VERSION 5.7 ;
  NOWIREEXTENSIONATPIN ON ;
  DIVIDERCHAR "/" ;
  BUSBITCHARS "[]" ;
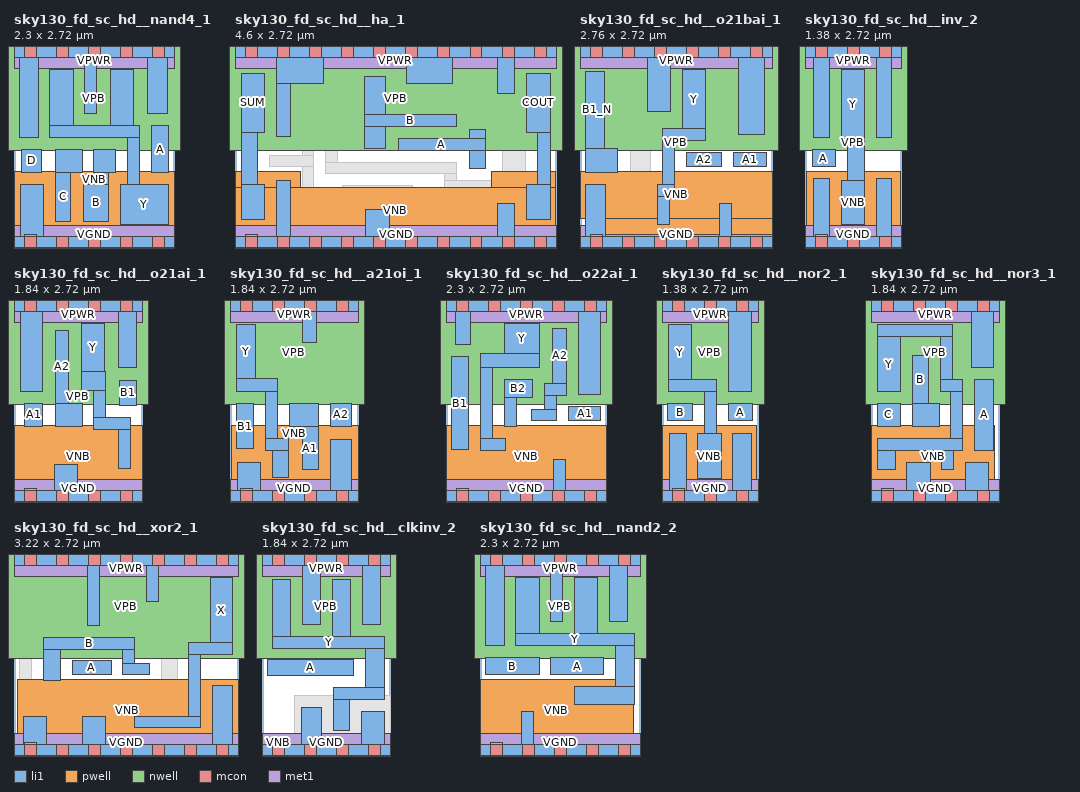
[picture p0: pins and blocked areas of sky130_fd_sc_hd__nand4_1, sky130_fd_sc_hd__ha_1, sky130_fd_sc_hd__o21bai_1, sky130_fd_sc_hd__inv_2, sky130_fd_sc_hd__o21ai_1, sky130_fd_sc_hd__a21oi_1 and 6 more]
MACRO sky130_fd_sc_hd__nand4_1
  CLASS BLOCK ;
  FOREIGN sky130_fd_sc_hd__nand4_1 ;
  ORIGIN 0.000 0.000 ;
  SIZE 2.300 BY 2.720 ;
  PIN C
    ANTENNAGATEAREA 0.247500 ;
    PORT
      LAYER li1 ;
        RECT 0.595 0.995 0.975 1.325 ;
        RECT 0.595 0.300 0.810 0.995 ;
    END
  END C
  PIN B
    ANTENNAGATEAREA 0.247500 ;
    PORT
      LAYER li1 ;
        RECT 1.145 0.995 1.455 1.325 ;
        RECT 1.145 0.825 1.350 0.995 ;
        RECT 1.000 0.300 1.350 0.825 ;
    END
  END B
  PIN Y
    ANTENNADIFFAREA 0.795000 ;
    PORT
      LAYER li1 ;
        RECT 0.515 1.665 0.845 2.465 ;
        RECT 1.385 1.665 1.715 2.465 ;
        RECT 0.515 1.495 1.795 1.665 ;
        RECT 1.625 0.825 1.795 1.495 ;
        RECT 1.520 0.255 2.215 0.825 ;
    END
  END Y
  PIN D
    ANTENNAGATEAREA 0.247500 ;
    PORT
      LAYER li1 ;
        RECT 0.110 0.995 0.395 1.325 ;
    END
  END D
  PIN A
    ANTENNAGATEAREA 0.247500 ;
    PORT
      LAYER li1 ;
        RECT 1.975 0.995 2.215 1.665 ;
    END
  END A
  PIN VNB
    PORT
      LAYER pwell ;
        RECT 0.005 0.105 2.295 1.015 ;
        RECT 0.150 -0.085 0.320 0.105 ;
    END
  END VNB
  PIN VPB
    PORT
      LAYER nwell ;
        RECT -0.190 1.305 2.490 2.910 ;
    END
  END VPB
  PIN VPWR
    USE POWER ;
    PORT
      LAYER li1 ;
        RECT 0.000 2.635 2.300 2.805 ;
        RECT 0.085 1.495 0.345 2.635 ;
        RECT 1.015 1.835 1.185 2.635 ;
        RECT 1.915 1.835 2.195 2.635 ;
      LAYER mcon ;
        RECT 0.145 2.635 0.315 2.805 ;
        RECT 0.605 2.635 0.775 2.805 ;
        RECT 1.065 2.635 1.235 2.805 ;
        RECT 1.525 2.635 1.695 2.805 ;
        RECT 1.985 2.635 2.155 2.805 ;
      LAYER met1 ;
        RECT 0.000 2.480 2.300 2.960 ;
    END
  END VPWR
  PIN VGND
    USE GROUND ;
    PORT
      LAYER li1 ;
        RECT 0.090 0.085 0.425 0.825 ;
        RECT 0.000 -0.085 2.300 0.085 ;
      LAYER mcon ;
        RECT 0.145 -0.085 0.315 0.085 ;
        RECT 0.605 -0.085 0.775 0.085 ;
        RECT 1.065 -0.085 1.235 0.085 ;
        RECT 1.525 -0.085 1.695 0.085 ;
        RECT 1.985 -0.085 2.155 0.085 ;
      LAYER met1 ;
        RECT 0.000 -0.240 2.300 0.240 ;
    END
  END VGND
END sky130_fd_sc_hd__nand4_1
MACRO sky130_fd_sc_hd__ha_1
  CLASS BLOCK ;
  FOREIGN sky130_fd_sc_hd__ha_1 ;
  ORIGIN 0.000 0.000 ;
  SIZE 4.600 BY 2.720 ;
  PIN B
    ANTENNAGATEAREA 0.252000 ;
    PORT
      LAYER li1 ;
        RECT 1.850 1.825 2.155 2.375 ;
        RECT 1.850 1.655 3.165 1.825 ;
        RECT 1.850 1.345 2.155 1.655 ;
    END
  END B
  PIN A
    ANTENNAGATEAREA 0.252000 ;
    PORT
      LAYER li1 ;
        RECT 3.360 1.485 3.585 1.615 ;
        RECT 2.335 1.315 3.585 1.485 ;
        RECT 3.360 1.055 3.585 1.315 ;
    END
  END A
  PIN COUT
    ANTENNADIFFAREA 0.429000 ;
    PORT
      LAYER li1 ;
        RECT 4.175 1.565 4.515 2.415 ;
        RECT 4.330 0.825 4.515 1.565 ;
        RECT 4.175 0.315 4.515 0.825 ;
    END
  END COUT
  PIN SUM
    ANTENNADIFFAREA 0.429000 ;
    PORT
      LAYER li1 ;
        RECT 0.090 1.565 0.425 2.415 ;
        RECT 0.090 0.825 0.320 1.565 ;
        RECT 0.090 0.315 0.425 0.825 ;
    END
  END SUM
  PIN VNB
    PORT
      LAYER pwell ;
        RECT 0.005 0.785 0.935 1.015 ;
        RECT 3.675 0.785 4.595 1.015 ;
        RECT 0.005 0.105 4.595 0.785 ;
        RECT 0.150 -0.085 0.320 0.105 ;
    END
  END VNB
  PIN VPB
    PORT
      LAYER nwell ;
        RECT -0.190 1.305 4.790 2.910 ;
    END
  END VPB
  PIN VGND
    USE GROUND ;
    PORT
      LAYER li1 ;
        RECT 0.595 0.085 0.790 0.885 ;
        RECT 1.875 0.085 2.205 0.465 ;
        RECT 3.755 0.085 4.005 0.545 ;
        RECT 0.000 -0.085 4.600 0.085 ;
      LAYER mcon ;
        RECT 0.145 -0.085 0.315 0.085 ;
        RECT 0.605 -0.085 0.775 0.085 ;
        RECT 1.065 -0.085 1.235 0.085 ;
        RECT 1.525 -0.085 1.695 0.085 ;
        RECT 1.985 -0.085 2.155 0.085 ;
        RECT 2.445 -0.085 2.615 0.085 ;
        RECT 2.905 -0.085 3.075 0.085 ;
        RECT 3.365 -0.085 3.535 0.085 ;
        RECT 3.825 -0.085 3.995 0.085 ;
        RECT 4.285 -0.085 4.455 0.085 ;
      LAYER met1 ;
        RECT 0.000 -0.240 4.600 0.240 ;
    END
  END VGND
  PIN VPWR
    USE POWER ;
    PORT
      LAYER li1 ;
        RECT 0.000 2.635 4.600 2.805 ;
        RECT 0.595 2.275 1.260 2.635 ;
        RECT 2.450 2.275 3.120 2.635 ;
        RECT 0.595 1.515 0.790 2.275 ;
        RECT 3.755 2.125 4.005 2.635 ;
      LAYER mcon ;
        RECT 0.145 2.635 0.315 2.805 ;
        RECT 0.605 2.635 0.775 2.805 ;
        RECT 1.065 2.635 1.235 2.805 ;
        RECT 1.525 2.635 1.695 2.805 ;
        RECT 1.985 2.635 2.155 2.805 ;
        RECT 2.445 2.635 2.615 2.805 ;
        RECT 2.905 2.635 3.075 2.805 ;
        RECT 3.365 2.635 3.535 2.805 ;
        RECT 3.825 2.635 3.995 2.805 ;
        RECT 4.285 2.635 4.455 2.805 ;
      LAYER met1 ;
        RECT 0.000 2.480 4.600 2.960 ;
    END
  END VPWR
  OBS
      LAYER li1 ;
        RECT 1.510 2.105 1.680 2.355 ;
        RECT 0.960 1.935 1.680 2.105 ;
        RECT 3.350 1.955 3.520 2.355 ;
        RECT 0.960 1.245 1.130 1.935 ;
        RECT 3.350 1.785 4.005 1.955 ;
        RECT 3.835 1.325 4.005 1.785 ;
        RECT 0.490 1.075 1.130 1.245 ;
        RECT 0.960 0.675 1.130 1.075 ;
        RECT 1.300 1.145 1.470 1.325 ;
        RECT 1.300 0.975 3.170 1.145 ;
        RECT 3.000 0.885 3.170 0.975 ;
        RECT 3.835 0.995 4.160 1.325 ;
        RECT 3.835 0.885 4.005 0.995 ;
        RECT 0.960 0.345 1.285 0.675 ;
        RECT 1.535 0.635 2.545 0.805 ;
        RECT 1.535 0.345 1.705 0.635 ;
        RECT 2.375 0.345 2.545 0.635 ;
        RECT 3.000 0.715 4.005 0.885 ;
        RECT 3.000 0.345 3.170 0.715 ;
  END
END sky130_fd_sc_hd__ha_1
MACRO sky130_fd_sc_hd__o21bai_1
  CLASS BLOCK ;
  FOREIGN sky130_fd_sc_hd__o21bai_1 ;
  ORIGIN 0.000 0.000 ;
  SIZE 2.760 BY 2.720 ;
  PIN A1
    ANTENNAGATEAREA 0.247500 ;
    PORT
      LAYER li1 ;
        RECT 2.195 1.075 2.675 1.285 ;
    END
  END A1
  PIN Y
    ANTENNADIFFAREA 0.474000 ;
    PORT
      LAYER li1 ;
        RECT 1.470 1.625 1.795 2.465 ;
        RECT 1.185 1.455 1.795 1.625 ;
        RECT 1.185 0.825 1.355 1.455 ;
        RECT 1.115 0.645 1.355 0.825 ;
        RECT 1.115 0.255 1.285 0.645 ;
    END
  END Y
  PIN B1_N
    ANTENNAGATEAREA 0.126000 ;
    PORT
      LAYER li1 ;
        RECT 0.085 1.345 0.355 2.445 ;
        RECT 0.085 0.995 0.535 1.345 ;
    END
  END B1_N
  PIN A2
    ANTENNAGATEAREA 0.247500 ;
    PORT
      LAYER li1 ;
        RECT 1.525 1.075 2.025 1.285 ;
    END
  END A2
  PIN VNB
    PORT
      LAYER pwell ;
        RECT 0.005 0.335 2.755 1.015 ;
        RECT 0.145 0.105 2.755 0.335 ;
        RECT 0.145 -0.085 0.315 0.105 ;
    END
  END VNB
  PIN VPB
    PORT
      LAYER nwell ;
        RECT -0.190 1.305 2.950 2.910 ;
    END
  END VPB
  PIN VPWR
    USE POWER ;
    PORT
      LAYER li1 ;
        RECT 0.000 2.635 2.760 2.805 ;
        RECT 0.970 1.875 1.300 2.635 ;
        RECT 2.270 1.535 2.645 2.635 ;
      LAYER mcon ;
        RECT 0.145 2.635 0.315 2.805 ;
        RECT 0.605 2.635 0.775 2.805 ;
        RECT 1.065 2.635 1.235 2.805 ;
        RECT 1.525 2.635 1.695 2.805 ;
        RECT 1.985 2.635 2.155 2.805 ;
        RECT 2.445 2.635 2.615 2.805 ;
      LAYER met1 ;
        RECT 0.000 2.480 2.760 2.960 ;
    END
  END VPWR
  PIN VGND
    USE GROUND ;
    PORT
      LAYER li1 ;
        RECT 0.085 0.085 0.360 0.825 ;
        RECT 1.995 0.085 2.165 0.555 ;
        RECT 0.000 -0.085 2.760 0.085 ;
      LAYER mcon ;
        RECT 0.145 -0.085 0.315 0.085 ;
        RECT 0.605 -0.085 0.775 0.085 ;
        RECT 1.065 -0.085 1.235 0.085 ;
        RECT 1.525 -0.085 1.695 0.085 ;
        RECT 1.985 -0.085 2.155 0.085 ;
        RECT 2.445 -0.085 2.615 0.085 ;
      LAYER met1 ;
        RECT 0.000 -0.240 2.760 0.240 ;
    END
  END VGND
  OBS
      LAYER li1 ;
        RECT 0.525 1.705 0.800 2.210 ;
        RECT 0.525 1.535 1.015 1.705 ;
        RECT 0.720 0.995 1.015 1.535 ;
        RECT 0.720 0.825 0.890 0.995 ;
        RECT 0.580 0.655 0.890 0.825 ;
        RECT 1.570 0.735 2.665 0.905 ;
        RECT 0.580 0.495 0.770 0.655 ;
        RECT 1.570 0.485 1.740 0.735 ;
        RECT 1.490 0.255 1.820 0.485 ;
        RECT 2.335 0.270 2.665 0.735 ;
  END
END sky130_fd_sc_hd__o21bai_1
MACRO sky130_fd_sc_hd__inv_2
  CLASS BLOCK ;
  FOREIGN sky130_fd_sc_hd__inv_2 ;
  ORIGIN 0.000 0.000 ;
  SIZE 1.380 BY 2.720 ;
  PIN A
    ANTENNAGATEAREA 0.495000 ;
    PORT
      LAYER li1 ;
        RECT 0.105 1.075 0.435 1.325 ;
    END
  END A
  PIN Y
    ANTENNADIFFAREA 0.445500 ;
    PORT
      LAYER li1 ;
        RECT 0.525 1.485 0.855 2.465 ;
        RECT 0.605 0.885 0.855 1.485 ;
        RECT 0.525 0.255 0.855 0.885 ;
    END
  END Y
  PIN VNB
    PORT
      LAYER pwell ;
        RECT 0.015 0.105 1.365 1.015 ;
        RECT 0.145 -0.085 0.315 0.105 ;
    END
  END VNB
  PIN VPB
    PORT
      LAYER nwell ;
        RECT -0.190 1.305 1.570 2.910 ;
    END
  END VPB
  PIN VPWR
    USE POWER ;
    PORT
      LAYER li1 ;
        RECT 0.000 2.635 1.380 2.805 ;
        RECT 0.125 1.495 0.355 2.635 ;
        RECT 1.025 1.495 1.235 2.635 ;
      LAYER mcon ;
        RECT 0.145 2.635 0.315 2.805 ;
        RECT 0.605 2.635 0.775 2.805 ;
        RECT 1.065 2.635 1.235 2.805 ;
      LAYER met1 ;
        RECT 0.000 2.480 1.380 2.960 ;
    END
  END VPWR
  PIN VGND
    USE GROUND ;
    PORT
      LAYER li1 ;
        RECT 0.125 0.085 0.355 0.905 ;
        RECT 1.025 0.085 1.235 0.905 ;
        RECT 0.000 -0.085 1.380 0.085 ;
      LAYER mcon ;
        RECT 0.145 -0.085 0.315 0.085 ;
        RECT 0.605 -0.085 0.775 0.085 ;
        RECT 1.065 -0.085 1.235 0.085 ;
      LAYER met1 ;
        RECT 0.000 -0.240 1.380 0.240 ;
    END
  END VGND
END sky130_fd_sc_hd__inv_2
MACRO sky130_fd_sc_hd__o21ai_1
  CLASS BLOCK ;
  FOREIGN sky130_fd_sc_hd__o21ai_1 ;
  ORIGIN 0.000 0.000 ;
  SIZE 1.840 BY 2.720 ;
  PIN A2
    ANTENNAGATEAREA 0.247500 ;
    PORT
      LAYER li1 ;
        RECT 0.590 1.325 0.785 2.375 ;
        RECT 0.590 0.995 0.975 1.325 ;
    END
  END A2
  PIN A1
    ANTENNAGATEAREA 0.247500 ;
    PORT
      LAYER li1 ;
        RECT 0.150 0.995 0.410 1.325 ;
    END
  END A1
  PIN B1
    ANTENNAGATEAREA 0.202500 ;
    PORT
      LAYER li1 ;
        RECT 1.505 1.295 1.750 1.655 ;
    END
  END B1
  PIN Y
    ANTENNADIFFAREA 0.517000 ;
    PORT
      LAYER li1 ;
        RECT 0.965 1.785 1.295 2.465 ;
        RECT 0.965 1.505 1.315 1.785 ;
        RECT 1.145 1.125 1.315 1.505 ;
        RECT 1.145 0.955 1.665 1.125 ;
        RECT 1.495 0.390 1.665 0.955 ;
    END
  END Y
  PIN VNB
    PORT
      LAYER pwell ;
        RECT 0.005 0.105 1.835 1.015 ;
        RECT 0.150 -0.085 0.320 0.105 ;
    END
  END VNB
  PIN VPB
    PORT
      LAYER nwell ;
        RECT -0.190 1.305 2.030 2.910 ;
    END
  END VPB
  PIN VGND
    USE GROUND ;
    PORT
      LAYER li1 ;
        RECT 0.575 0.085 0.905 0.445 ;
        RECT 0.000 -0.085 1.840 0.085 ;
      LAYER mcon ;
        RECT 0.145 -0.085 0.315 0.085 ;
        RECT 0.605 -0.085 0.775 0.085 ;
        RECT 1.065 -0.085 1.235 0.085 ;
        RECT 1.525 -0.085 1.695 0.085 ;
      LAYER met1 ;
        RECT 0.000 -0.240 1.840 0.240 ;
    END
  END VGND
  PIN VPWR
    USE POWER ;
    PORT
      LAYER li1 ;
        RECT 0.000 2.635 1.840 2.805 ;
        RECT 0.090 1.495 0.410 2.635 ;
        RECT 1.495 1.835 1.750 2.635 ;
      LAYER mcon ;
        RECT 0.145 2.635 0.315 2.805 ;
        RECT 0.605 2.635 0.775 2.805 ;
        RECT 1.065 2.635 1.235 2.805 ;
        RECT 1.525 2.635 1.695 2.805 ;
      LAYER met1 ;
        RECT 0.000 2.480 1.840 2.960 ;
    END
  END VPWR
  OBS
      LAYER li1 ;
        RECT 0.090 0.615 1.305 0.785 ;
        RECT 0.090 0.265 0.380 0.615 ;
        RECT 1.075 0.310 1.305 0.615 ;
  END
END sky130_fd_sc_hd__o21ai_1
MACRO sky130_fd_sc_hd__a21oi_1
  CLASS BLOCK ;
  FOREIGN sky130_fd_sc_hd__a21oi_1 ;
  ORIGIN 0.000 0.000 ;
  SIZE 1.840 BY 2.720 ;
  PIN A1
    ANTENNAGATEAREA 0.247500 ;
    PORT
      LAYER li1 ;
        RECT 0.850 0.995 1.265 1.325 ;
        RECT 1.035 0.375 1.265 0.995 ;
    END
  END A1
  PIN B1
    ANTENNAGATEAREA 0.247500 ;
    PORT
      LAYER li1 ;
        RECT 0.095 0.675 0.335 1.325 ;
    END
  END B1
  PIN Y
    ANTENNADIFFAREA 0.447000 ;
    PORT
      LAYER li1 ;
        RECT 0.095 1.685 0.370 2.455 ;
        RECT 0.095 1.495 0.680 1.685 ;
        RECT 0.505 0.825 0.680 1.495 ;
        RECT 0.505 0.645 0.835 0.825 ;
        RECT 0.610 0.265 0.835 0.645 ;
    END
  END Y
  PIN A2
    ANTENNAGATEAREA 0.247500 ;
    PORT
      LAYER li1 ;
        RECT 1.445 0.995 1.740 1.325 ;
    END
  END A2
  PIN VNB
    PORT
      LAYER pwell ;
        RECT 0.020 0.105 1.835 1.015 ;
        RECT 0.145 -0.085 0.315 0.105 ;
    END
  END VNB
  PIN VPB
    PORT
      LAYER nwell ;
        RECT -0.190 1.305 2.030 2.910 ;
    END
  END VPB
  PIN VPWR
    USE POWER ;
    PORT
      LAYER li1 ;
        RECT 0.000 2.635 1.840 2.805 ;
        RECT 1.040 2.195 1.235 2.635 ;
      LAYER mcon ;
        RECT 0.145 2.635 0.315 2.805 ;
        RECT 0.605 2.635 0.775 2.805 ;
        RECT 1.065 2.635 1.235 2.805 ;
        RECT 1.525 2.635 1.695 2.805 ;
      LAYER met1 ;
        RECT 0.000 2.480 1.840 2.960 ;
    END
  END VPWR
  PIN VGND
    USE GROUND ;
    PORT
      LAYER li1 ;
        RECT 0.110 0.085 0.440 0.475 ;
        RECT 1.445 0.085 1.745 0.815 ;
        RECT 0.000 -0.085 1.840 0.085 ;
      LAYER mcon ;
        RECT 0.145 -0.085 0.315 0.085 ;
        RECT 0.605 -0.085 0.775 0.085 ;
        RECT 1.065 -0.085 1.235 0.085 ;
        RECT 1.525 -0.085 1.695 0.085 ;
      LAYER met1 ;
        RECT 0.000 -0.240 1.840 0.240 ;
    END
  END VGND
  OBS
      LAYER li1 ;
        RECT 0.540 2.025 0.870 2.455 ;
        RECT 1.415 2.025 1.745 2.455 ;
        RECT 0.540 1.855 1.745 2.025 ;
        RECT 0.850 1.525 1.745 1.855 ;
  END
END sky130_fd_sc_hd__a21oi_1
MACRO sky130_fd_sc_hd__o22ai_1
  CLASS BLOCK ;
  FOREIGN sky130_fd_sc_hd__o22ai_1 ;
  ORIGIN 0.000 0.000 ;
  SIZE 2.300 BY 2.720 ;
  PIN A2
    ANTENNAGATEAREA 0.247500 ;
    PORT
      LAYER li1 ;
        RECT 1.525 1.615 1.725 2.405 ;
        RECT 1.405 1.445 1.725 1.615 ;
        RECT 1.405 1.245 1.585 1.445 ;
        RECT 1.220 1.075 1.585 1.245 ;
    END
  END A2
  PIN B1
    ANTENNAGATEAREA 0.247500 ;
    PORT
      LAYER li1 ;
        RECT 0.085 0.665 0.325 1.990 ;
    END
  END B1
  PIN Y
    ANTENNADIFFAREA 0.650250 ;
    PORT
      LAYER li1 ;
        RECT 0.835 2.045 1.335 2.465 ;
        RECT 0.495 1.835 1.335 2.045 ;
        RECT 0.495 0.825 0.665 1.835 ;
        RECT 0.495 0.645 0.845 0.825 ;
    END
  END Y
  PIN A1
    ANTENNAGATEAREA 0.247500 ;
    PORT
      LAYER li1 ;
        RECT 1.755 1.075 2.215 1.275 ;
    END
  END A1
  PIN B2
    ANTENNAGATEAREA 0.247500 ;
    PORT
      LAYER li1 ;
        RECT 0.835 1.415 1.235 1.665 ;
        RECT 0.835 0.995 1.005 1.415 ;
    END
  END B2
  PIN VNB
    PORT
      LAYER pwell ;
        RECT 0.005 0.105 2.295 1.015 ;
        RECT 0.145 -0.085 0.315 0.105 ;
    END
  END VNB
  PIN VPB
    PORT
      LAYER nwell ;
        RECT -0.190 1.305 2.490 2.910 ;
    END
  END VPB
  PIN VGND
    USE GROUND ;
    PORT
      LAYER li1 ;
        RECT 1.535 0.085 1.705 0.525 ;
        RECT 0.000 -0.085 2.300 0.085 ;
      LAYER mcon ;
        RECT 0.145 -0.085 0.315 0.085 ;
        RECT 0.605 -0.085 0.775 0.085 ;
        RECT 1.065 -0.085 1.235 0.085 ;
        RECT 1.525 -0.085 1.695 0.085 ;
        RECT 1.985 -0.085 2.155 0.085 ;
      LAYER met1 ;
        RECT 0.000 -0.240 2.300 0.240 ;
    END
  END VGND
  PIN VPWR
    USE POWER ;
    PORT
      LAYER li1 ;
        RECT 0.000 2.635 2.300 2.805 ;
        RECT 0.135 2.175 0.345 2.635 ;
        RECT 1.895 1.455 2.215 2.635 ;
      LAYER mcon ;
        RECT 0.145 2.635 0.315 2.805 ;
        RECT 0.605 2.635 0.775 2.805 ;
        RECT 1.065 2.635 1.235 2.805 ;
        RECT 1.525 2.635 1.695 2.805 ;
        RECT 1.985 2.635 2.155 2.805 ;
      LAYER met1 ;
        RECT 0.000 2.480 2.300 2.960 ;
    END
  END VPWR
  OBS
      LAYER li1 ;
        RECT 1.185 0.825 2.215 0.865 ;
        RECT 1.015 0.695 2.215 0.825 ;
        RECT 1.015 0.475 1.345 0.695 ;
        RECT 0.085 0.295 1.345 0.475 ;
        RECT 1.875 0.280 2.215 0.695 ;
  END
END sky130_fd_sc_hd__o22ai_1
MACRO VIA_via4_1600x1600
  CLASS BLOCK ;
  FOREIGN VIA_via4_1600x1600 ;
  ORIGIN 0.800 0.800 ;
  SIZE 1.600 BY 1.600 ;
  OBS
      LAYER met4 ;
        RECT -0.800 -0.800 0.800 0.800 ;
      LAYER via4 ;
        RECT -0.590 -0.590 0.590 0.590 ;
      LAYER met5 ;
        RECT -0.800 -0.800 0.800 0.800 ;
  END
END VIA_via4_1600x1600
MACRO sky130_fd_sc_hd__nor2_1
  CLASS BLOCK ;
  FOREIGN sky130_fd_sc_hd__nor2_1 ;
  ORIGIN 0.000 0.000 ;
  SIZE 1.380 BY 2.720 ;
  PIN B
    ANTENNAGATEAREA 0.247500 ;
    PORT
      LAYER li1 ;
        RECT 0.085 1.075 0.435 1.325 ;
    END
  END B
  PIN Y
    ANTENNADIFFAREA 0.435500 ;
    PORT
      LAYER li1 ;
        RECT 0.095 1.665 0.425 2.450 ;
        RECT 0.095 1.495 0.775 1.665 ;
        RECT 0.605 0.895 0.775 1.495 ;
        RECT 0.515 0.255 0.845 0.895 ;
    END
  END Y
  PIN A
    ANTENNAGATEAREA 0.247500 ;
    PORT
      LAYER li1 ;
        RECT 0.945 1.075 1.295 1.325 ;
    END
  END A
  PIN VNB
    PORT
      LAYER pwell ;
        RECT 0.005 0.105 1.355 1.015 ;
        RECT 0.150 -0.085 0.320 0.105 ;
    END
  END VNB
  PIN VPB
    PORT
      LAYER nwell ;
        RECT -0.190 1.305 1.570 2.910 ;
    END
  END VPB
  PIN VGND
    USE GROUND ;
    PORT
      LAYER li1 ;
        RECT 0.105 0.085 0.345 0.895 ;
        RECT 1.015 0.085 1.285 0.895 ;
        RECT 0.000 -0.085 1.380 0.085 ;
      LAYER mcon ;
        RECT 0.145 -0.085 0.315 0.085 ;
        RECT 0.605 -0.085 0.775 0.085 ;
        RECT 1.065 -0.085 1.235 0.085 ;
      LAYER met1 ;
        RECT 0.000 -0.240 1.380 0.240 ;
    END
  END VGND
  PIN VPWR
    USE POWER ;
    PORT
      LAYER li1 ;
        RECT 0.000 2.635 1.380 2.805 ;
        RECT 0.955 1.495 1.285 2.635 ;
      LAYER mcon ;
        RECT 0.145 2.635 0.315 2.805 ;
        RECT 0.605 2.635 0.775 2.805 ;
        RECT 1.065 2.635 1.235 2.805 ;
      LAYER met1 ;
        RECT 0.000 2.480 1.380 2.960 ;
    END
  END VPWR
END sky130_fd_sc_hd__nor2_1
MACRO sky130_fd_sc_hd__nor3_1
  CLASS BLOCK ;
  FOREIGN sky130_fd_sc_hd__nor3_1 ;
  ORIGIN 0.000 0.000 ;
  SIZE 1.840 BY 2.720 ;
  PIN C
    ANTENNAGATEAREA 0.247500 ;
    PORT
      LAYER li1 ;
        RECT 0.090 0.995 0.425 1.325 ;
    END
  END C
  PIN Y
    ANTENNADIFFAREA 0.604500 ;
    PORT
      LAYER li1 ;
        RECT 0.090 2.280 1.170 2.450 ;
        RECT 0.090 1.495 0.425 2.280 ;
        RECT 1.000 1.665 1.170 2.280 ;
        RECT 1.000 1.495 1.315 1.665 ;
        RECT 1.145 0.825 1.315 1.495 ;
        RECT 0.090 0.655 1.315 0.825 ;
        RECT 0.090 0.385 0.345 0.655 ;
        RECT 1.015 0.385 1.185 0.655 ;
    END
  END Y
  PIN A
    ANTENNAGATEAREA 0.247500 ;
    PORT
      LAYER li1 ;
        RECT 1.485 0.655 1.755 1.665 ;
    END
  END A
  PIN B
    ANTENNAGATEAREA 0.247500 ;
    PORT
      LAYER li1 ;
        RECT 0.595 1.325 0.830 2.005 ;
        RECT 0.595 0.995 0.975 1.325 ;
    END
  END B
  PIN VNB
    PORT
      LAYER pwell ;
        RECT 0.005 0.105 1.775 1.015 ;
        RECT 0.150 -0.085 0.320 0.105 ;
    END
  END VNB
  PIN VPB
    PORT
      LAYER nwell ;
        RECT -0.190 1.305 2.030 2.910 ;
    END
  END VPB
  PIN VGND
    USE GROUND ;
    PORT
      LAYER li1 ;
        RECT 0.515 0.085 0.845 0.485 ;
        RECT 1.355 0.085 1.685 0.485 ;
        RECT 0.000 -0.085 1.840 0.085 ;
      LAYER mcon ;
        RECT 0.145 -0.085 0.315 0.085 ;
        RECT 0.605 -0.085 0.775 0.085 ;
        RECT 1.065 -0.085 1.235 0.085 ;
        RECT 1.525 -0.085 1.695 0.085 ;
      LAYER met1 ;
        RECT 0.000 -0.240 1.840 0.240 ;
    END
  END VGND
  PIN VPWR
    USE POWER ;
    PORT
      LAYER li1 ;
        RECT 0.000 2.635 1.840 2.805 ;
        RECT 1.435 1.835 1.750 2.635 ;
      LAYER mcon ;
        RECT 0.145 2.635 0.315 2.805 ;
        RECT 0.605 2.635 0.775 2.805 ;
        RECT 1.065 2.635 1.235 2.805 ;
        RECT 1.525 2.635 1.695 2.805 ;
      LAYER met1 ;
        RECT 0.000 2.480 1.840 2.960 ;
    END
  END VPWR
END sky130_fd_sc_hd__nor3_1
MACRO VIA_via4_4200x1600
  CLASS BLOCK ;
  FOREIGN VIA_via4_4200x1600 ;
  ORIGIN 2.100 0.800 ;
  SIZE 4.200 BY 1.600 ;
  OBS
      LAYER met4 ;
        RECT -2.100 -0.800 2.100 0.800 ;
      LAYER via4 ;
        RECT -1.390 -0.590 -0.210 0.590 ;
        RECT 0.210 -0.590 1.390 0.590 ;
      LAYER met5 ;
        RECT -2.100 -0.800 2.100 0.800 ;
  END
END VIA_via4_4200x1600
MACRO sky130_fd_sc_hd__xor2_1
  CLASS BLOCK ;
  FOREIGN sky130_fd_sc_hd__xor2_1 ;
  ORIGIN 0.000 0.000 ;
  SIZE 3.220 BY 2.720 ;
  PIN B
    ANTENNAGATEAREA 0.495000 ;
    PORT
      LAYER li1 ;
        RECT 0.425 1.445 1.730 1.615 ;
        RECT 0.425 0.995 0.670 1.445 ;
        RECT 1.560 1.245 1.730 1.445 ;
        RECT 1.560 1.075 1.935 1.245 ;
    END
  END B
  PIN X
    ANTENNADIFFAREA 0.800500 ;
    PORT
      LAYER li1 ;
        RECT 2.815 1.535 3.135 2.465 ;
        RECT 2.505 1.365 3.135 1.535 ;
        RECT 2.505 0.485 2.675 1.365 ;
        RECT 1.720 0.315 2.675 0.485 ;
    END
  END X
  PIN A
    ANTENNAGATEAREA 0.495000 ;
    PORT
      LAYER li1 ;
        RECT 0.840 1.075 1.390 1.275 ;
    END
  END A
  PIN VNB
    PORT
      LAYER pwell ;
        RECT 0.045 0.105 3.215 1.015 ;
        RECT 0.145 -0.085 0.315 0.105 ;
    END
  END VNB
  PIN VPB
    PORT
      LAYER nwell ;
        RECT -0.190 1.305 3.410 2.910 ;
    END
  END VPB
  PIN VPWR
    USE POWER ;
    PORT
      LAYER li1 ;
        RECT 0.000 2.635 3.220 2.805 ;
        RECT 1.055 1.785 1.225 2.635 ;
        RECT 1.895 2.125 2.065 2.635 ;
      LAYER mcon ;
        RECT 0.145 2.635 0.315 2.805 ;
        RECT 0.605 2.635 0.775 2.805 ;
        RECT 1.065 2.635 1.235 2.805 ;
        RECT 1.525 2.635 1.695 2.805 ;
        RECT 1.985 2.635 2.155 2.805 ;
        RECT 2.445 2.635 2.615 2.805 ;
        RECT 2.905 2.635 3.075 2.805 ;
      LAYER met1 ;
        RECT 0.000 2.480 3.220 2.960 ;
    END
  END VPWR
  PIN VGND
    USE GROUND ;
    PORT
      LAYER li1 ;
        RECT 0.135 0.085 0.465 0.475 ;
        RECT 0.975 0.085 1.305 0.475 ;
        RECT 2.845 0.085 3.135 0.920 ;
        RECT 0.000 -0.085 3.220 0.085 ;
      LAYER mcon ;
        RECT 0.145 -0.085 0.315 0.085 ;
        RECT 0.605 -0.085 0.775 0.085 ;
        RECT 1.065 -0.085 1.235 0.085 ;
        RECT 1.525 -0.085 1.695 0.085 ;
        RECT 1.985 -0.085 2.155 0.085 ;
        RECT 2.445 -0.085 2.615 0.085 ;
        RECT 2.905 -0.085 3.075 0.085 ;
      LAYER met1 ;
        RECT 0.000 -0.240 3.220 0.240 ;
    END
  END VGND
  OBS
      LAYER li1 ;
        RECT 0.085 1.785 0.465 2.465 ;
        RECT 1.395 1.955 1.725 2.465 ;
        RECT 2.235 1.955 2.635 2.465 ;
        RECT 1.395 1.785 2.635 1.955 ;
        RECT 0.085 0.825 0.255 1.785 ;
        RECT 2.105 0.825 2.335 1.325 ;
        RECT 0.085 0.655 2.335 0.825 ;
        RECT 0.635 0.335 0.805 0.655 ;
  END
END sky130_fd_sc_hd__xor2_1
MACRO sky130_fd_sc_hd__clkinv_2
  CLASS BLOCK ;
  FOREIGN sky130_fd_sc_hd__clkinv_2 ;
  ORIGIN 0.000 0.000 ;
  SIZE 1.840 BY 2.720 ;
  PIN Y
    ANTENNADIFFAREA 0.662600 ;
    PORT
      LAYER li1 ;
        RECT 0.155 1.630 0.410 2.435 ;
        RECT 1.010 1.630 1.270 2.435 ;
        RECT 0.155 1.460 1.755 1.630 ;
        RECT 1.475 0.895 1.755 1.460 ;
        RECT 1.025 0.725 1.755 0.895 ;
        RECT 1.025 0.280 1.250 0.725 ;
    END
  END Y
  PIN A
    ANTENNAGATEAREA 0.576000 ;
    PORT
      LAYER li1 ;
        RECT 0.085 1.065 1.305 1.290 ;
    END
  END A
  PIN VNB
    PORT
      LAYER pwell ;
        RECT 0.145 -0.085 0.315 0.085 ;
    END
  END VNB
  PIN VPB
    PORT
      LAYER nwell ;
        RECT -0.190 1.305 2.030 2.910 ;
    END
  END VPB
  PIN VPWR
    USE POWER ;
    PORT
      LAYER li1 ;
        RECT 0.000 2.635 1.840 2.805 ;
        RECT 0.580 1.800 0.840 2.635 ;
        RECT 1.440 1.800 1.695 2.635 ;
      LAYER mcon ;
        RECT 0.145 2.635 0.315 2.805 ;
        RECT 0.605 2.635 0.775 2.805 ;
        RECT 1.065 2.635 1.235 2.805 ;
        RECT 1.525 2.635 1.695 2.805 ;
      LAYER met1 ;
        RECT 0.000 2.480 1.840 2.960 ;
    END
  END VPWR
  PIN VGND
    USE GROUND ;
    PORT
      LAYER li1 ;
        RECT 0.560 0.085 0.855 0.610 ;
        RECT 1.420 0.085 1.750 0.555 ;
        RECT 0.000 -0.085 1.840 0.085 ;
      LAYER mcon ;
        RECT 0.145 -0.085 0.315 0.085 ;
        RECT 0.605 -0.085 0.775 0.085 ;
        RECT 1.065 -0.085 1.235 0.085 ;
        RECT 1.525 -0.085 1.695 0.085 ;
      LAYER met1 ;
        RECT 0.000 -0.240 1.840 0.240 ;
    END
  END VGND
  OBS
      LAYER pwell ;
        RECT 0.470 0.105 1.835 0.785 ;
  END
END sky130_fd_sc_hd__clkinv_2
MACRO sky130_fd_sc_hd__nand2_2
  CLASS BLOCK ;
  FOREIGN sky130_fd_sc_hd__nand2_2 ;
  ORIGIN 0.000 0.000 ;
  SIZE 2.300 BY 2.720 ;
  PIN Y
    ANTENNADIFFAREA 0.715500 ;
    PORT
      LAYER li1 ;
        RECT 0.515 1.665 0.845 2.465 ;
        RECT 1.355 1.665 1.685 2.465 ;
        RECT 0.515 1.495 2.215 1.665 ;
        RECT 1.935 0.905 2.215 1.495 ;
        RECT 1.355 0.655 2.215 0.905 ;
    END
  END Y
  PIN A
    ANTENNAGATEAREA 0.495000 ;
    PORT
      LAYER li1 ;
        RECT 1.015 1.075 1.765 1.325 ;
    END
  END A
  PIN B
    ANTENNAGATEAREA 0.495000 ;
    PORT
      LAYER li1 ;
        RECT 0.085 1.075 0.845 1.325 ;
    END
  END B
  PIN VNB
    PORT
      LAYER pwell ;
        RECT 0.005 0.105 2.195 1.015 ;
        RECT 0.150 -0.085 0.320 0.105 ;
    END
  END VNB
  PIN VPB
    PORT
      LAYER nwell ;
        RECT -0.190 1.305 2.490 2.910 ;
    END
  END VPB
  PIN VGND
    USE GROUND ;
    PORT
      LAYER li1 ;
        RECT 0.595 0.085 0.765 0.545 ;
        RECT 0.000 -0.085 2.300 0.085 ;
      LAYER mcon ;
        RECT 0.145 -0.085 0.315 0.085 ;
        RECT 0.605 -0.085 0.775 0.085 ;
        RECT 1.065 -0.085 1.235 0.085 ;
        RECT 1.525 -0.085 1.695 0.085 ;
        RECT 1.985 -0.085 2.155 0.085 ;
      LAYER met1 ;
        RECT 0.000 -0.240 2.300 0.240 ;
    END
  END VGND
  PIN VPWR
    USE POWER ;
    PORT
      LAYER li1 ;
        RECT 0.000 2.635 2.300 2.805 ;
        RECT 0.085 1.495 0.345 2.635 ;
        RECT 1.015 1.835 1.185 2.635 ;
        RECT 1.855 1.835 2.110 2.635 ;
      LAYER mcon ;
        RECT 0.145 2.635 0.315 2.805 ;
        RECT 0.605 2.635 0.775 2.805 ;
        RECT 1.065 2.635 1.235 2.805 ;
        RECT 1.525 2.635 1.695 2.805 ;
        RECT 1.985 2.635 2.155 2.805 ;
      LAYER met1 ;
        RECT 0.000 2.480 2.300 2.960 ;
    END
  END VPWR
  OBS
      LAYER li1 ;
        RECT 0.085 0.715 1.185 0.885 ;
        RECT 0.085 0.255 0.425 0.715 ;
        RECT 0.935 0.465 1.185 0.715 ;
        RECT 1.775 0.465 2.105 0.485 ;
        RECT 0.935 0.255 2.105 0.465 ;
  END
END sky130_fd_sc_hd__nand2_2
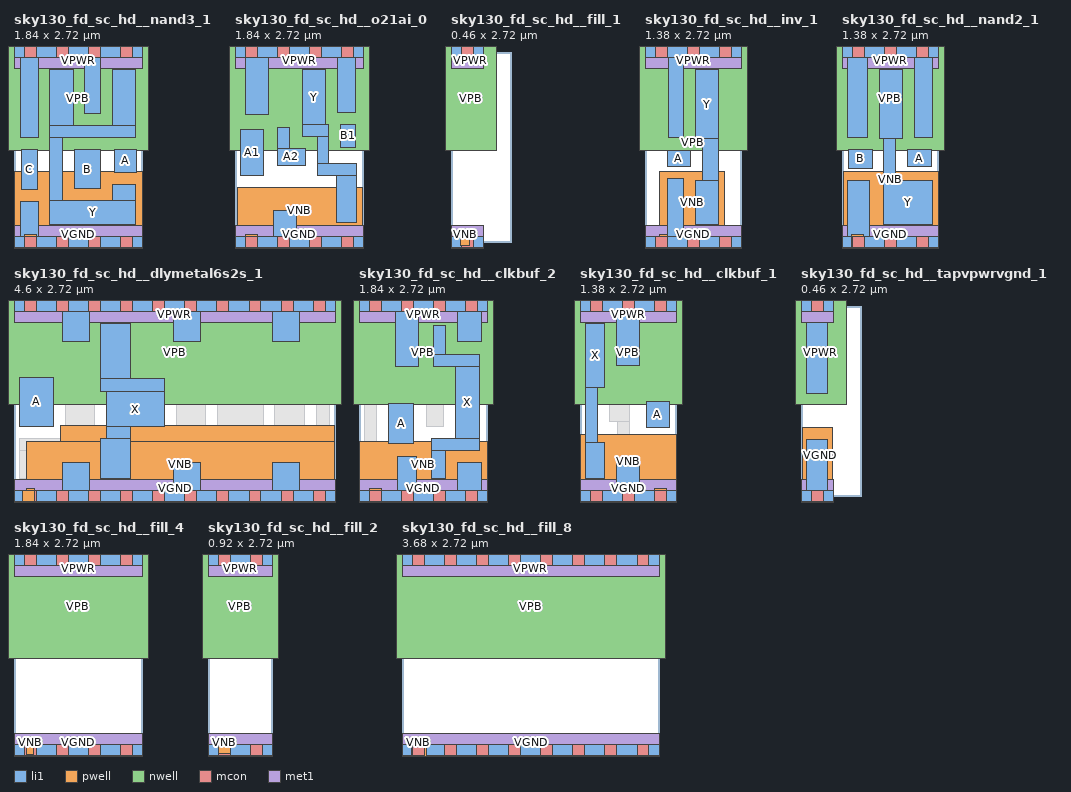
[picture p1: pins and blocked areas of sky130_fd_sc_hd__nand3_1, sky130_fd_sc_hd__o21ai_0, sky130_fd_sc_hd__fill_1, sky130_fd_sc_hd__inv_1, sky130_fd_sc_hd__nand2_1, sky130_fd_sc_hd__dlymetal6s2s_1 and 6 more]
MACRO sky130_fd_sc_hd__nand3_1
  CLASS BLOCK ;
  FOREIGN sky130_fd_sc_hd__nand3_1 ;
  ORIGIN 0.000 0.000 ;
  SIZE 1.840 BY 2.720 ;
  PIN Y
    ANTENNADIFFAREA 0.699000 ;
    PORT
      LAYER li1 ;
        RECT 0.515 1.665 0.845 2.465 ;
        RECT 1.415 1.665 1.745 2.465 ;
        RECT 0.515 1.495 1.745 1.665 ;
        RECT 0.515 0.595 0.695 1.495 ;
        RECT 1.415 0.595 1.745 0.825 ;
        RECT 0.515 0.255 1.745 0.595 ;
    END
  END Y
  PIN A
    ANTENNAGATEAREA 0.247500 ;
    PORT
      LAYER li1 ;
        RECT 1.445 0.995 1.755 1.325 ;
    END
  END A
  PIN C
    ANTENNAGATEAREA 0.247500 ;
    PORT
      LAYER li1 ;
        RECT 0.110 0.745 0.330 1.325 ;
    END
  END C
  PIN B
    ANTENNAGATEAREA 0.247500 ;
    PORT
      LAYER li1 ;
        RECT 0.865 0.765 1.240 1.325 ;
    END
  END B
  PIN VNB
    PORT
      LAYER pwell ;
        RECT 0.005 0.105 1.835 1.015 ;
        RECT 0.150 -0.085 0.320 0.105 ;
    END
  END VNB
  PIN VPB
    PORT
      LAYER nwell ;
        RECT -0.190 1.305 2.030 2.910 ;
    END
  END VPB
  PIN VGND
    USE GROUND ;
    PORT
      LAYER li1 ;
        RECT 0.090 0.085 0.345 0.575 ;
        RECT 0.000 -0.085 1.840 0.085 ;
      LAYER mcon ;
        RECT 0.145 -0.085 0.315 0.085 ;
        RECT 0.605 -0.085 0.775 0.085 ;
        RECT 1.065 -0.085 1.235 0.085 ;
        RECT 1.525 -0.085 1.695 0.085 ;
      LAYER met1 ;
        RECT 0.000 -0.240 1.840 0.240 ;
    END
  END VGND
  PIN VPWR
    USE POWER ;
    PORT
      LAYER li1 ;
        RECT 0.000 2.635 1.840 2.805 ;
        RECT 0.090 1.495 0.345 2.635 ;
        RECT 1.015 1.835 1.245 2.635 ;
      LAYER mcon ;
        RECT 0.145 2.635 0.315 2.805 ;
        RECT 0.605 2.635 0.775 2.805 ;
        RECT 1.065 2.635 1.235 2.805 ;
        RECT 1.525 2.635 1.695 2.805 ;
      LAYER met1 ;
        RECT 0.000 2.480 1.840 2.960 ;
    END
  END VPWR
END sky130_fd_sc_hd__nand3_1
MACRO sky130_fd_sc_hd__o21ai_0
  CLASS BLOCK ;
  FOREIGN sky130_fd_sc_hd__o21ai_0 ;
  ORIGIN 0.000 0.000 ;
  SIZE 1.840 BY 2.720 ;
  PIN Y
    ANTENNADIFFAREA 0.290500 ;
    PORT
      LAYER li1 ;
        RECT 0.965 1.680 1.300 2.465 ;
        RECT 0.965 1.510 1.345 1.680 ;
        RECT 1.175 1.125 1.345 1.510 ;
        RECT 1.175 0.955 1.740 1.125 ;
        RECT 1.455 0.280 1.740 0.955 ;
    END
  END Y
  PIN B1
    ANTENNAGATEAREA 0.159000 ;
    PORT
      LAYER li1 ;
        RECT 1.515 1.355 1.730 1.685 ;
    END
  END B1
  PIN A2
    ANTENNAGATEAREA 0.159000 ;
    PORT
      LAYER li1 ;
        RECT 0.605 1.340 0.775 1.645 ;
        RECT 0.605 1.100 1.005 1.340 ;
    END
  END A2
  PIN A1
    ANTENNAGATEAREA 0.159000 ;
    PORT
      LAYER li1 ;
        RECT 0.085 0.955 0.415 1.615 ;
    END
  END A1
  PIN VNB
    PORT
      LAYER pwell ;
        RECT 0.030 0.105 1.830 0.785 ;
        RECT 0.145 -0.085 0.315 0.105 ;
    END
  END VNB
  PIN VPB
    PORT
      LAYER nwell ;
        RECT -0.190 1.305 2.030 2.910 ;
    END
  END VPB
  PIN VGND
    USE GROUND ;
    PORT
      LAYER li1 ;
        RECT 0.550 0.085 0.880 0.445 ;
        RECT 0.000 -0.085 1.840 0.085 ;
      LAYER mcon ;
        RECT 0.145 -0.085 0.315 0.085 ;
        RECT 0.605 -0.085 0.775 0.085 ;
        RECT 1.065 -0.085 1.235 0.085 ;
        RECT 1.525 -0.085 1.695 0.085 ;
      LAYER met1 ;
        RECT 0.000 -0.240 1.840 0.240 ;
    END
  END VGND
  PIN VPWR
    USE POWER ;
    PORT
      LAYER li1 ;
        RECT 0.000 2.635 1.840 2.805 ;
        RECT 0.145 1.825 0.475 2.635 ;
        RECT 1.470 1.855 1.725 2.635 ;
      LAYER mcon ;
        RECT 0.145 2.635 0.315 2.805 ;
        RECT 0.605 2.635 0.775 2.805 ;
        RECT 1.065 2.635 1.235 2.805 ;
        RECT 1.525 2.635 1.695 2.805 ;
      LAYER met1 ;
        RECT 0.000 2.480 1.840 2.960 ;
    END
  END VPWR
  OBS
      LAYER li1 ;
        RECT 0.120 0.615 1.285 0.785 ;
        RECT 0.120 0.280 0.380 0.615 ;
        RECT 1.050 0.280 1.285 0.615 ;
  END
END sky130_fd_sc_hd__o21ai_0
MACRO sky130_fd_sc_hd__fill_1
  CLASS BLOCK ;
  FOREIGN sky130_fd_sc_hd__fill_1 ;
  ORIGIN 0.000 0.000 ;
  SIZE 0.460 BY 2.720 ;
  PIN VNB
    PORT
      LAYER pwell ;
        RECT 0.140 -0.055 0.260 0.055 ;
    END
  END VNB
  PIN VPB
    PORT
      LAYER nwell ;
        RECT -0.190 1.305 0.650 2.910 ;
    END
  END VPB
  PIN VPWR
    USE POWER ;
    PORT
      LAYER li1 ;
        RECT 0.000 2.635 0.460 2.805 ;
      LAYER mcon ;
        RECT 0.145 2.635 0.315 2.805 ;
      LAYER met1 ;
        RECT 0.000 2.480 0.460 2.960 ;
    END
  END VPWR
  PIN VGND
    USE GROUND ;
    PORT
      LAYER li1 ;
        RECT 0.000 -0.085 0.460 0.085 ;
      LAYER mcon ;
        RECT 0.145 -0.085 0.315 0.085 ;
      LAYER met1 ;
        RECT 0.000 -0.240 0.460 0.240 ;
    END
  END VGND
END sky130_fd_sc_hd__fill_1
MACRO sky130_fd_sc_hd__inv_1
  CLASS BLOCK ;
  FOREIGN sky130_fd_sc_hd__inv_1 ;
  ORIGIN 0.000 0.000 ;
  SIZE 1.380 BY 2.720 ;
  PIN Y
    ANTENNADIFFAREA 0.429000 ;
    PORT
      LAYER li1 ;
        RECT 0.720 1.485 1.050 2.465 ;
        RECT 0.820 0.885 1.050 1.485 ;
        RECT 0.720 0.255 1.050 0.885 ;
    END
  END Y
  PIN A
    ANTENNAGATEAREA 0.247500 ;
    PORT
      LAYER li1 ;
        RECT 0.320 1.075 0.650 1.315 ;
    END
  END A
  PIN VNB
    PORT
      LAYER pwell ;
        RECT 0.210 0.105 1.140 1.015 ;
        RECT 0.210 0.085 0.315 0.105 ;
        RECT 0.145 -0.085 0.315 0.085 ;
    END
  END VNB
  PIN VPB
    PORT
      LAYER nwell ;
        RECT -0.190 1.305 1.570 2.910 ;
    END
  END VPB
  PIN VGND
    USE GROUND ;
    PORT
      LAYER li1 ;
        RECT 0.320 0.085 0.550 0.905 ;
        RECT 0.000 -0.085 1.380 0.085 ;
      LAYER mcon ;
        RECT 0.145 -0.085 0.315 0.085 ;
        RECT 0.605 -0.085 0.775 0.085 ;
        RECT 1.065 -0.085 1.235 0.085 ;
      LAYER met1 ;
        RECT 0.000 -0.240 1.380 0.240 ;
    END
  END VGND
  PIN VPWR
    USE POWER ;
    PORT
      LAYER li1 ;
        RECT 0.000 2.635 1.380 2.805 ;
        RECT 0.340 1.495 0.550 2.635 ;
      LAYER mcon ;
        RECT 0.145 2.635 0.315 2.805 ;
        RECT 0.605 2.635 0.775 2.805 ;
        RECT 1.065 2.635 1.235 2.805 ;
      LAYER met1 ;
        RECT 0.000 2.480 1.380 2.960 ;
    END
  END VPWR
END sky130_fd_sc_hd__inv_1
MACRO VIA_M1M2_PR
  CLASS BLOCK ;
  FOREIGN VIA_M1M2_PR ;
  ORIGIN 0.160 0.160 ;
  SIZE 0.320 BY 0.320 ;
  OBS
      LAYER met1 ;
        RECT -0.160 -0.130 0.160 0.130 ;
      LAYER via ;
        RECT -0.130 -0.130 0.130 0.130 ;
      LAYER met2 ;
        RECT -0.130 -0.160 0.130 0.160 ;
  END
END VIA_M1M2_PR
MACRO VIA_L1M1_PR_MR
  CLASS BLOCK ;
  FOREIGN VIA_L1M1_PR_MR ;
  ORIGIN 0.145 0.115 ;
  SIZE 0.290 BY 0.230 ;
  OBS
      LAYER li1 ;
        RECT -0.085 -0.085 0.085 0.085 ;
      LAYER met1 ;
        RECT -0.145 -0.115 0.145 0.115 ;
  END
END VIA_L1M1_PR_MR
MACRO sky130_fd_sc_hd__nand2_1
  CLASS BLOCK ;
  FOREIGN sky130_fd_sc_hd__nand2_1 ;
  ORIGIN 0.000 0.000 ;
  SIZE 1.380 BY 2.720 ;
  PIN Y
    ANTENNADIFFAREA 0.439000 ;
    PORT
      LAYER li1 ;
        RECT 0.535 1.485 0.865 2.465 ;
        RECT 0.600 0.885 0.770 1.485 ;
        RECT 0.600 0.255 1.295 0.885 ;
    END
  END Y
  PIN B
    ANTENNAGATEAREA 0.247500 ;
    PORT
      LAYER li1 ;
        RECT 0.095 1.055 0.430 1.325 ;
    END
  END B
  PIN A
    ANTENNAGATEAREA 0.247500 ;
    PORT
      LAYER li1 ;
        RECT 0.940 1.075 1.275 1.325 ;
    END
  END A
  PIN VNB
    PORT
      LAYER pwell ;
        RECT 0.025 0.105 1.375 1.015 ;
        RECT 0.140 -0.085 0.310 0.105 ;
    END
  END VNB
  PIN VPB
    PORT
      LAYER nwell ;
        RECT -0.190 1.305 1.570 2.910 ;
    END
  END VPB
  PIN VGND
    USE GROUND ;
    PORT
      LAYER li1 ;
        RECT 0.085 0.085 0.395 0.885 ;
        RECT 0.000 -0.085 1.380 0.085 ;
      LAYER mcon ;
        RECT 0.145 -0.085 0.315 0.085 ;
        RECT 0.605 -0.085 0.775 0.085 ;
        RECT 1.065 -0.085 1.235 0.085 ;
      LAYER met1 ;
        RECT 0.000 -0.240 1.380 0.240 ;
    END
  END VGND
  PIN VPWR
    USE POWER ;
    PORT
      LAYER li1 ;
        RECT 0.000 2.635 1.380 2.805 ;
        RECT 0.085 1.495 0.365 2.635 ;
        RECT 1.035 1.495 1.295 2.635 ;
      LAYER mcon ;
        RECT 0.145 2.635 0.315 2.805 ;
        RECT 0.605 2.635 0.775 2.805 ;
        RECT 1.065 2.635 1.235 2.805 ;
      LAYER met1 ;
        RECT 0.000 2.480 1.380 2.960 ;
    END
  END VPWR
END sky130_fd_sc_hd__nand2_1
MACRO sky130_fd_sc_hd__dlymetal6s2s_1
  CLASS BLOCK ;
  FOREIGN sky130_fd_sc_hd__dlymetal6s2s_1 ;
  ORIGIN 0.000 0.000 ;
  SIZE 4.600 BY 2.720 ;
  PIN A
    ANTENNAGATEAREA 0.126000 ;
    PORT
      LAYER li1 ;
        RECT 0.085 0.995 0.570 1.700 ;
    END
  END A
  PIN X
    ANTENNAGATEAREA 0.126000 ;
    ANTENNADIFFAREA 0.429000 ;
    PORT
      LAYER li1 ;
        RECT 1.245 1.675 1.670 2.465 ;
        RECT 1.245 1.495 2.150 1.675 ;
        RECT 1.320 0.995 2.150 1.495 ;
        RECT 1.320 0.825 1.670 0.995 ;
        RECT 1.245 0.255 1.670 0.825 ;
    END
  END X
  PIN VNB
    PORT
      LAYER pwell ;
        RECT 0.665 0.785 4.595 1.015 ;
        RECT 0.180 0.105 4.595 0.785 ;
        RECT 0.180 0.085 0.290 0.105 ;
        RECT 0.120 -0.085 0.290 0.085 ;
    END
  END VNB
  PIN VPB
    PORT
      LAYER nwell ;
        RECT -0.190 1.305 4.790 2.910 ;
    END
  END VPB
  PIN VPWR
    USE POWER ;
    PORT
      LAYER li1 ;
        RECT 0.000 2.635 4.600 2.805 ;
        RECT 0.690 2.210 1.075 2.635 ;
        RECT 2.285 2.210 2.670 2.635 ;
        RECT 3.700 2.210 4.085 2.635 ;
      LAYER mcon ;
        RECT 0.145 2.635 0.315 2.805 ;
        RECT 0.605 2.635 0.775 2.805 ;
        RECT 1.065 2.635 1.235 2.805 ;
        RECT 1.525 2.635 1.695 2.805 ;
        RECT 1.985 2.635 2.155 2.805 ;
        RECT 2.445 2.635 2.615 2.805 ;
        RECT 2.905 2.635 3.075 2.805 ;
        RECT 3.365 2.635 3.535 2.805 ;
        RECT 3.825 2.635 3.995 2.805 ;
        RECT 4.285 2.635 4.455 2.805 ;
      LAYER met1 ;
        RECT 0.000 2.480 4.600 2.960 ;
    END
  END VPWR
  PIN VGND
    USE GROUND ;
    PORT
      LAYER li1 ;
        RECT 0.690 0.085 1.075 0.485 ;
        RECT 2.285 0.085 2.670 0.485 ;
        RECT 3.700 0.085 4.085 0.485 ;
        RECT 0.000 -0.085 4.600 0.085 ;
      LAYER mcon ;
        RECT 0.145 -0.085 0.315 0.085 ;
        RECT 0.605 -0.085 0.775 0.085 ;
        RECT 1.065 -0.085 1.235 0.085 ;
        RECT 1.525 -0.085 1.695 0.085 ;
        RECT 1.985 -0.085 2.155 0.085 ;
        RECT 2.445 -0.085 2.615 0.085 ;
        RECT 2.905 -0.085 3.075 0.085 ;
        RECT 3.365 -0.085 3.535 0.085 ;
        RECT 3.825 -0.085 3.995 0.085 ;
        RECT 4.285 -0.085 4.455 0.085 ;
      LAYER met1 ;
        RECT 0.000 -0.240 4.600 0.240 ;
    END
  END VGND
  OBS
      LAYER li1 ;
        RECT 0.085 2.040 0.520 2.465 ;
        RECT 1.840 2.040 2.115 2.465 ;
        RECT 0.085 1.870 1.075 2.040 ;
        RECT 0.740 1.325 1.075 1.870 ;
        RECT 1.840 1.845 2.670 2.040 ;
        RECT 2.320 1.325 2.670 1.845 ;
        RECT 2.840 1.675 3.085 2.465 ;
        RECT 3.275 2.040 3.530 2.465 ;
        RECT 3.275 1.845 4.085 2.040 ;
        RECT 2.840 1.495 3.565 1.675 ;
        RECT 0.740 0.995 1.150 1.325 ;
        RECT 2.320 0.995 2.745 1.325 ;
        RECT 2.915 0.995 3.565 1.495 ;
        RECT 3.735 1.325 4.085 1.845 ;
        RECT 4.255 1.495 4.515 2.465 ;
        RECT 3.735 0.995 4.160 1.325 ;
        RECT 0.740 0.825 1.075 0.995 ;
        RECT 2.320 0.825 2.670 0.995 ;
        RECT 2.915 0.825 3.085 0.995 ;
        RECT 3.735 0.825 4.085 0.995 ;
        RECT 4.330 0.825 4.515 1.495 ;
        RECT 0.085 0.655 1.075 0.825 ;
        RECT 1.860 0.655 2.670 0.825 ;
        RECT 0.085 0.255 0.520 0.655 ;
        RECT 1.860 0.255 2.115 0.655 ;
        RECT 2.840 0.255 3.085 0.825 ;
        RECT 3.275 0.655 4.085 0.825 ;
        RECT 3.275 0.255 3.530 0.655 ;
        RECT 4.255 0.255 4.515 0.825 ;
  END
END sky130_fd_sc_hd__dlymetal6s2s_1
MACRO sky130_fd_sc_hd__clkbuf_2
  CLASS BLOCK ;
  FOREIGN sky130_fd_sc_hd__clkbuf_2 ;
  ORIGIN 0.000 0.000 ;
  SIZE 1.840 BY 2.720 ;
  PIN A
    ANTENNAGATEAREA 0.213000 ;
    PORT
      LAYER li1 ;
        RECT 0.425 0.745 0.785 1.325 ;
    END
  END A
  PIN X
    ANTENNADIFFAREA 0.383400 ;
    PORT
      LAYER li1 ;
        RECT 1.060 2.030 1.245 2.435 ;
        RECT 1.060 1.855 1.725 2.030 ;
        RECT 1.385 0.825 1.725 1.855 ;
        RECT 1.040 0.655 1.725 0.825 ;
        RECT 1.040 0.255 1.245 0.655 ;
    END
  END X
  PIN VNB
    PORT
      LAYER pwell ;
        RECT 0.005 0.105 1.835 0.785 ;
        RECT 0.145 -0.085 0.315 0.105 ;
    END
  END VNB
  PIN VPB
    PORT
      LAYER nwell ;
        RECT -0.190 1.305 2.030 2.910 ;
    END
  END VPB
  PIN VGND
    USE GROUND ;
    PORT
      LAYER li1 ;
        RECT 0.555 0.085 0.830 0.565 ;
        RECT 1.415 0.085 1.750 0.485 ;
        RECT 0.000 -0.085 1.840 0.085 ;
      LAYER mcon ;
        RECT 0.145 -0.085 0.315 0.085 ;
        RECT 0.605 -0.085 0.775 0.085 ;
        RECT 1.065 -0.085 1.235 0.085 ;
        RECT 1.525 -0.085 1.695 0.085 ;
      LAYER met1 ;
        RECT 0.000 -0.240 1.840 0.240 ;
    END
  END VGND
  PIN VPWR
    USE POWER ;
    PORT
      LAYER li1 ;
        RECT 0.000 2.635 1.840 2.805 ;
        RECT 0.525 1.855 0.855 2.635 ;
        RECT 1.415 2.210 1.750 2.635 ;
      LAYER mcon ;
        RECT 0.145 2.635 0.315 2.805 ;
        RECT 0.605 2.635 0.775 2.805 ;
        RECT 1.065 2.635 1.235 2.805 ;
        RECT 1.525 2.635 1.695 2.805 ;
      LAYER met1 ;
        RECT 0.000 2.480 1.840 2.960 ;
    END
  END VPWR
  OBS
      LAYER li1 ;
        RECT 0.085 1.665 0.355 2.435 ;
        RECT 0.085 1.495 1.215 1.665 ;
        RECT 0.085 0.585 0.255 1.495 ;
        RECT 0.965 0.995 1.215 1.495 ;
        RECT 0.085 0.255 0.345 0.585 ;
  END
END sky130_fd_sc_hd__clkbuf_2
MACRO sky130_fd_sc_hd__clkbuf_1
  CLASS BLOCK ;
  FOREIGN sky130_fd_sc_hd__clkbuf_1 ;
  ORIGIN 0.000 0.000 ;
  SIZE 1.380 BY 2.720 ;
  PIN X
    ANTENNADIFFAREA 0.340600 ;
    PORT
      LAYER li1 ;
        RECT 0.085 1.560 0.355 2.465 ;
        RECT 0.085 0.760 0.255 1.560 ;
        RECT 0.085 0.255 0.345 0.760 ;
    END
  END X
  PIN A
    ANTENNAGATEAREA 0.196500 ;
    PORT
      LAYER li1 ;
        RECT 0.945 0.985 1.275 1.355 ;
    END
  END A
  PIN VNB
    PORT
      LAYER pwell ;
        RECT 0.005 0.105 1.375 0.885 ;
        RECT 1.065 -0.085 1.235 0.105 ;
    END
  END VNB
  PIN VPB
    PORT
      LAYER nwell ;
        RECT -0.190 1.305 1.570 2.910 ;
    END
  END VPB
  PIN VGND
    USE GROUND ;
    PORT
      LAYER li1 ;
        RECT 0.525 0.085 0.855 0.465 ;
        RECT 0.000 -0.085 1.380 0.085 ;
      LAYER mcon ;
        RECT 0.145 -0.085 0.315 0.085 ;
        RECT 0.605 -0.085 0.775 0.085 ;
        RECT 1.065 -0.085 1.235 0.085 ;
      LAYER met1 ;
        RECT 0.000 -0.240 1.380 0.240 ;
    END
  END VGND
  PIN VPWR
    USE POWER ;
    PORT
      LAYER li1 ;
        RECT 0.000 2.635 1.380 2.805 ;
        RECT 0.525 1.875 0.855 2.635 ;
      LAYER mcon ;
        RECT 0.145 2.635 0.315 2.805 ;
        RECT 0.605 2.635 0.775 2.805 ;
        RECT 1.065 2.635 1.235 2.805 ;
      LAYER met1 ;
        RECT 0.000 2.480 1.380 2.960 ;
    END
  END VPWR
  OBS
      LAYER li1 ;
        RECT 1.035 1.705 1.205 2.465 ;
        RECT 0.540 1.535 1.205 1.705 ;
        RECT 0.540 1.390 0.710 1.535 ;
        RECT 0.425 1.060 0.710 1.390 ;
        RECT 0.540 0.805 0.710 1.060 ;
        RECT 0.540 0.635 1.205 0.805 ;
        RECT 1.035 0.255 1.205 0.635 ;
  END
END sky130_fd_sc_hd__clkbuf_1
MACRO sky130_fd_sc_hd__tapvpwrvgnd_1
  CLASS BLOCK ;
  FOREIGN sky130_fd_sc_hd__tapvpwrvgnd_1 ;
  ORIGIN 0.000 0.000 ;
  SIZE 0.460 BY 2.720 ;
  PIN VPWR
    USE POWER ;
    PORT
      LAYER nwell ;
        RECT -0.190 1.305 0.650 2.910 ;
      LAYER li1 ;
        RECT 0.000 2.635 0.460 2.805 ;
        RECT 0.085 1.470 0.375 2.635 ;
      LAYER mcon ;
        RECT 0.145 2.635 0.315 2.805 ;
      LAYER met1 ;
        RECT 0.000 2.480 0.460 2.960 ;
    END
  END VPWR
  PIN VGND
    USE GROUND ;
    PORT
      LAYER pwell ;
        RECT 0.015 0.190 0.445 0.975 ;
      LAYER li1 ;
        RECT 0.085 0.085 0.375 0.810 ;
        RECT 0.000 -0.085 0.460 0.085 ;
      LAYER mcon ;
        RECT 0.145 -0.085 0.315 0.085 ;
      LAYER met1 ;
        RECT 0.000 -0.240 0.460 0.240 ;
    END
  END VGND
END sky130_fd_sc_hd__tapvpwrvgnd_1
MACRO sky130_fd_sc_hd__fill_4
  CLASS BLOCK ;
  FOREIGN sky130_fd_sc_hd__fill_4 ;
  ORIGIN 0.000 0.000 ;
  SIZE 1.840 BY 2.720 ;
  PIN VNB
    PORT
      LAYER pwell ;
        RECT 0.175 -0.060 0.285 0.060 ;
    END
  END VNB
  PIN VPB
    PORT
      LAYER nwell ;
        RECT -0.190 1.305 2.030 2.910 ;
    END
  END VPB
  PIN VGND
    USE GROUND ;
    PORT
      LAYER li1 ;
        RECT 0.000 -0.085 1.840 0.085 ;
      LAYER mcon ;
        RECT 0.145 -0.085 0.315 0.085 ;
        RECT 0.605 -0.085 0.775 0.085 ;
        RECT 1.065 -0.085 1.235 0.085 ;
        RECT 1.525 -0.085 1.695 0.085 ;
      LAYER met1 ;
        RECT 0.000 -0.240 1.840 0.240 ;
    END
  END VGND
  PIN VPWR
    USE POWER ;
    PORT
      LAYER li1 ;
        RECT 0.000 2.635 1.840 2.805 ;
      LAYER mcon ;
        RECT 0.145 2.635 0.315 2.805 ;
        RECT 0.605 2.635 0.775 2.805 ;
        RECT 1.065 2.635 1.235 2.805 ;
        RECT 1.525 2.635 1.695 2.805 ;
      LAYER met1 ;
        RECT 0.000 2.480 1.840 2.960 ;
    END
  END VPWR
END sky130_fd_sc_hd__fill_4
MACRO sky130_fd_sc_hd__fill_2
  CLASS BLOCK ;
  FOREIGN sky130_fd_sc_hd__fill_2 ;
  ORIGIN 0.000 0.000 ;
  SIZE 0.920 BY 2.720 ;
  PIN VNB
    PORT
      LAYER pwell ;
        RECT 0.155 -0.050 0.315 0.060 ;
    END
  END VNB
  PIN VPB
    PORT
      LAYER nwell ;
        RECT -0.190 1.305 1.110 2.910 ;
    END
  END VPB
  PIN VGND
    USE GROUND ;
    PORT
      LAYER li1 ;
        RECT 0.000 -0.085 0.920 0.085 ;
      LAYER mcon ;
        RECT 0.145 -0.085 0.315 0.085 ;
        RECT 0.605 -0.085 0.775 0.085 ;
      LAYER met1 ;
        RECT 0.000 -0.240 0.920 0.240 ;
    END
  END VGND
  PIN VPWR
    USE POWER ;
    PORT
      LAYER li1 ;
        RECT 0.000 2.635 0.920 2.805 ;
      LAYER mcon ;
        RECT 0.145 2.635 0.315 2.805 ;
        RECT 0.605 2.635 0.775 2.805 ;
      LAYER met1 ;
        RECT 0.000 2.480 0.920 2.960 ;
    END
  END VPWR
END sky130_fd_sc_hd__fill_2
MACRO VIA_via_1600x480
  CLASS BLOCK ;
  FOREIGN VIA_via_1600x480 ;
  ORIGIN 0.800 0.240 ;
  SIZE 1.600 BY 0.480 ;
  OBS
      LAYER met1 ;
        RECT -0.800 -0.240 0.800 0.240 ;
      LAYER via ;
        RECT -0.770 -0.130 -0.510 0.130 ;
        RECT -0.450 -0.130 -0.190 0.130 ;
        RECT -0.130 -0.130 0.130 0.130 ;
        RECT 0.190 -0.130 0.450 0.130 ;
        RECT 0.510 -0.130 0.770 0.130 ;
      LAYER met2 ;
        RECT -0.770 -0.240 0.770 0.240 ;
  END
END VIA_via_1600x480
MACRO VIA_via2_1600x480
  CLASS BLOCK ;
  FOREIGN VIA_via2_1600x480 ;
  ORIGIN 0.800 0.240 ;
  SIZE 1.600 BY 0.480 ;
  OBS
      LAYER met2 ;
        RECT -0.740 -0.240 0.740 0.240 ;
      LAYER via2 ;
        RECT -0.740 -0.140 -0.460 0.140 ;
        RECT -0.340 -0.140 -0.060 0.140 ;
        RECT 0.060 -0.140 0.340 0.140 ;
        RECT 0.460 -0.140 0.740 0.140 ;
      LAYER met3 ;
        RECT -0.800 -0.165 0.800 0.165 ;
  END
END VIA_via2_1600x480
MACRO VIA_via3_1600x480
  CLASS BLOCK ;
  FOREIGN VIA_via3_1600x480 ;
  ORIGIN 0.800 0.240 ;
  SIZE 1.600 BY 0.480 ;
  OBS
      LAYER met3 ;
        RECT -0.800 -0.160 0.800 0.160 ;
      LAYER via3 ;
        RECT -0.760 -0.160 -0.440 0.160 ;
        RECT -0.360 -0.160 -0.040 0.160 ;
        RECT 0.040 -0.160 0.360 0.160 ;
        RECT 0.440 -0.160 0.760 0.160 ;
      LAYER met4 ;
        RECT -0.800 -0.240 0.800 0.240 ;
  END
END VIA_via3_1600x480
MACRO sky130_fd_sc_hd__fill_8
  CLASS BLOCK ;
  FOREIGN sky130_fd_sc_hd__fill_8 ;
  ORIGIN 0.000 0.000 ;
  SIZE 3.680 BY 2.720 ;
  PIN VNB
    PORT
      LAYER pwell ;
        RECT 0.130 -0.120 0.350 0.050 ;
    END
  END VNB
  PIN VPB
    PORT
      LAYER nwell ;
        RECT -0.190 1.305 3.870 2.910 ;
    END
  END VPB
  PIN VGND
    USE GROUND ;
    PORT
      LAYER li1 ;
        RECT 0.000 -0.085 3.680 0.085 ;
      LAYER mcon ;
        RECT 0.145 -0.085 0.315 0.085 ;
        RECT 0.605 -0.085 0.775 0.085 ;
        RECT 1.065 -0.085 1.235 0.085 ;
        RECT 1.525 -0.085 1.695 0.085 ;
        RECT 1.985 -0.085 2.155 0.085 ;
        RECT 2.445 -0.085 2.615 0.085 ;
        RECT 2.905 -0.085 3.075 0.085 ;
        RECT 3.365 -0.085 3.535 0.085 ;
      LAYER met1 ;
        RECT 0.000 -0.240 3.680 0.240 ;
    END
  END VGND
  PIN VPWR
    USE POWER ;
    PORT
      LAYER li1 ;
        RECT 0.000 2.635 3.680 2.805 ;
      LAYER mcon ;
        RECT 0.145 2.635 0.315 2.805 ;
        RECT 0.605 2.635 0.775 2.805 ;
        RECT 1.065 2.635 1.235 2.805 ;
        RECT 1.525 2.635 1.695 2.805 ;
        RECT 1.985 2.635 2.155 2.805 ;
        RECT 2.445 2.635 2.615 2.805 ;
        RECT 2.905 2.635 3.075 2.805 ;
        RECT 3.365 2.635 3.535 2.805 ;
      LAYER met1 ;
        RECT 0.000 2.480 3.680 2.960 ;
    END
  END VPWR
END sky130_fd_sc_hd__fill_8
MACRO VIA_via3_4200x480
  CLASS BLOCK ;
  FOREIGN VIA_via3_4200x480 ;
  ORIGIN 2.100 0.240 ;
  SIZE 4.200 BY 0.480 ;
  OBS
      LAYER met3 ;
        RECT -2.100 -0.160 2.100 0.160 ;
      LAYER via3 ;
        RECT -1.960 -0.160 -1.640 0.160 ;
        RECT -1.560 -0.160 -1.240 0.160 ;
        RECT -1.160 -0.160 -0.840 0.160 ;
        RECT -0.760 -0.160 -0.440 0.160 ;
        RECT -0.360 -0.160 -0.040 0.160 ;
        RECT 0.040 -0.160 0.360 0.160 ;
        RECT 0.440 -0.160 0.760 0.160 ;
        RECT 0.840 -0.160 1.160 0.160 ;
        RECT 1.240 -0.160 1.560 0.160 ;
        RECT 1.640 -0.160 1.960 0.160 ;
      LAYER met4 ;
        RECT -2.100 -0.240 2.100 0.240 ;
  END
END VIA_via3_4200x480
MACRO VIA_via2_4200x480
  CLASS BLOCK ;
  FOREIGN VIA_via2_4200x480 ;
  ORIGIN 2.100 0.240 ;
  SIZE 4.200 BY 0.480 ;
  OBS
      LAYER met2 ;
        RECT -1.940 -0.240 1.940 0.240 ;
      LAYER via2 ;
        RECT -1.940 -0.140 -1.660 0.140 ;
        RECT -1.540 -0.140 -1.260 0.140 ;
        RECT -1.140 -0.140 -0.860 0.140 ;
        RECT -0.740 -0.140 -0.460 0.140 ;
        RECT -0.340 -0.140 -0.060 0.140 ;
        RECT 0.060 -0.140 0.340 0.140 ;
        RECT 0.460 -0.140 0.740 0.140 ;
        RECT 0.860 -0.140 1.140 0.140 ;
        RECT 1.260 -0.140 1.540 0.140 ;
        RECT 1.660 -0.140 1.940 0.140 ;
      LAYER met3 ;
        RECT -2.100 -0.165 2.100 0.165 ;
  END
END VIA_via2_4200x480
MACRO VIA_via_4200x480
  CLASS BLOCK ;
  FOREIGN VIA_via_4200x480 ;
  ORIGIN 2.100 0.240 ;
  SIZE 4.200 BY 0.480 ;
  OBS
      LAYER met1 ;
        RECT -2.100 -0.240 2.100 0.240 ;
      LAYER via ;
        RECT -2.050 -0.130 -1.790 0.130 ;
        RECT -1.730 -0.130 -1.470 0.130 ;
        RECT -1.410 -0.130 -1.150 0.130 ;
        RECT -1.090 -0.130 -0.830 0.130 ;
        RECT -0.770 -0.130 -0.510 0.130 ;
        RECT -0.450 -0.130 -0.190 0.130 ;
        RECT -0.130 -0.130 0.130 0.130 ;
        RECT 0.190 -0.130 0.450 0.130 ;
        RECT 0.510 -0.130 0.770 0.130 ;
        RECT 0.830 -0.130 1.090 0.130 ;
        RECT 1.150 -0.130 1.410 0.130 ;
        RECT 1.470 -0.130 1.730 0.130 ;
        RECT 1.790 -0.130 2.050 0.130 ;
      LAYER met2 ;
        RECT -2.050 -0.240 2.050 0.240 ;
  END
END VIA_via_4200x480
MACRO VIA_via4_1600x4200
  CLASS BLOCK ;
  FOREIGN VIA_via4_1600x4200 ;
  ORIGIN 0.800 2.100 ;
  SIZE 1.600 BY 4.200 ;
  OBS
      LAYER met4 ;
        RECT -0.800 -2.100 0.800 2.100 ;
      LAYER via4 ;
        RECT -0.590 0.210 0.590 1.390 ;
        RECT -0.590 -1.390 0.590 -0.210 ;
      LAYER met5 ;
        RECT -0.800 -2.100 0.800 2.100 ;
  END
END VIA_via4_1600x4200
MACRO VIA_via4_4200x4200
  CLASS BLOCK ;
  FOREIGN VIA_via4_4200x4200 ;
  ORIGIN 2.100 2.100 ;
  SIZE 4.200 BY 4.200 ;
  OBS
      LAYER met4 ;
        RECT -2.100 -2.100 2.100 2.100 ;
      LAYER via4 ;
        RECT -1.390 -1.390 1.390 1.390 ;
      LAYER met5 ;
        RECT -2.100 -2.100 2.100 2.100 ;
  END
END VIA_via4_4200x4200
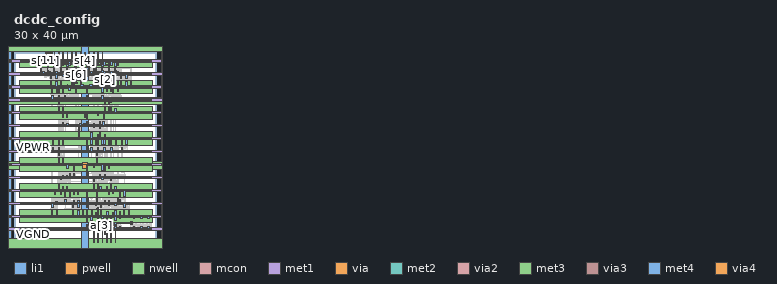
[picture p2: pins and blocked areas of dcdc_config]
MACRO dcdc_config
  CLASS BLOCK ;
  FOREIGN dcdc_config ;
  ORIGIN 0.000 0.000 ;
  SIZE 30.000 BY 40.000 ;
  PIN VPWR
    USE POWER ;
    PORT
      LAYER nwell ;
        RECT 1.190 36.665 29.170 38.270 ;
        RECT 1.190 31.225 29.170 34.055 ;
        RECT 1.190 25.785 29.170 28.615 ;
        RECT 1.190 20.345 29.170 23.175 ;
        RECT 1.190 14.905 29.170 17.735 ;
        RECT 1.190 9.465 29.170 12.295 ;
        RECT 1.190 4.025 29.170 6.855 ;
      LAYER li1 ;
        RECT 1.380 37.995 28.980 38.165 ;
        RECT 6.045 37.235 6.375 37.995 ;
        RECT 7.425 37.235 7.755 37.995 ;
        RECT 8.805 37.235 9.135 37.995 ;
        RECT 10.185 37.235 10.515 37.995 ;
        RECT 11.565 37.235 11.895 37.995 ;
        RECT 12.760 36.855 12.970 37.995 ;
        RECT 14.325 37.235 14.655 37.995 ;
        RECT 15.265 36.830 15.555 37.995 ;
        RECT 16.165 37.235 16.495 37.995 ;
        RECT 17.545 37.235 17.875 37.995 ;
        RECT 18.925 37.235 19.255 37.995 ;
        RECT 20.305 37.235 20.635 37.995 ;
        RECT 21.685 37.235 22.015 37.995 ;
        RECT 7.700 32.725 7.910 33.865 ;
        RECT 8.825 32.725 9.105 33.865 ;
        RECT 9.775 32.725 10.035 33.865 ;
        RECT 11.160 32.725 11.355 33.165 ;
        RECT 12.485 32.725 12.815 33.485 ;
        RECT 13.935 33.085 14.130 33.845 ;
        RECT 13.935 32.725 14.600 33.085 ;
        RECT 15.790 32.725 16.460 33.085 ;
        RECT 17.095 32.725 17.345 33.235 ;
        RECT 18.280 32.725 18.490 33.865 ;
        RECT 19.405 32.725 19.685 33.865 ;
        RECT 20.355 32.725 20.615 33.865 ;
        RECT 20.785 32.725 21.065 33.865 ;
        RECT 21.735 32.725 21.995 33.865 ;
        RECT 22.420 32.725 22.630 33.865 ;
        RECT 23.545 32.725 23.825 33.865 ;
        RECT 24.495 32.725 24.755 33.865 ;
        RECT 1.380 32.555 28.980 32.725 ;
        RECT 7.905 31.415 8.185 32.555 ;
        RECT 8.855 31.415 9.115 32.555 ;
        RECT 9.285 31.415 9.565 32.555 ;
        RECT 10.235 31.415 10.495 32.555 ;
        RECT 11.550 31.795 11.880 32.555 ;
        RECT 12.850 31.455 13.225 32.555 ;
        RECT 15.265 31.390 15.555 32.555 ;
        RECT 18.485 31.415 18.745 32.555 ;
        RECT 19.415 31.755 19.585 32.555 ;
        RECT 20.315 31.755 20.595 32.555 ;
        RECT 20.790 31.415 21.045 32.555 ;
        RECT 21.715 31.755 21.945 32.555 ;
        RECT 9.285 27.285 9.565 28.425 ;
        RECT 10.235 27.285 10.495 28.425 ;
        RECT 18.985 27.285 19.215 28.425 ;
        RECT 19.885 27.285 20.095 28.425 ;
        RECT 20.330 27.285 20.585 28.425 ;
        RECT 21.255 27.285 21.485 28.085 ;
        RECT 1.380 27.115 28.980 27.285 ;
        RECT 10.240 26.280 10.500 27.115 ;
        RECT 11.100 26.280 11.355 27.115 ;
        RECT 14.775 26.315 15.090 27.115 ;
        RECT 15.265 25.950 15.555 27.115 ;
        RECT 17.600 26.675 17.795 27.115 ;
        RECT 18.740 25.975 18.950 27.115 ;
        RECT 13.680 21.845 13.890 22.985 ;
        RECT 16.190 21.845 16.510 22.985 ;
        RECT 17.595 21.845 17.850 22.645 ;
        RECT 18.030 21.845 18.285 22.985 ;
        RECT 18.955 21.845 19.185 22.645 ;
        RECT 1.380 21.675 28.980 21.845 ;
        RECT 8.160 20.535 8.370 21.675 ;
        RECT 9.285 20.535 9.565 21.675 ;
        RECT 10.235 20.535 10.495 21.675 ;
        RECT 15.265 20.510 15.555 21.675 ;
        RECT 16.185 20.535 16.465 21.675 ;
        RECT 17.135 20.535 17.395 21.675 ;
        RECT 17.565 20.535 17.845 21.675 ;
        RECT 18.515 20.535 18.775 21.675 ;
        RECT 18.945 20.535 19.225 21.675 ;
        RECT 19.895 20.535 20.155 21.675 ;
        RECT 20.325 20.535 20.605 21.675 ;
        RECT 21.275 20.535 21.535 21.675 ;
        RECT 22.625 20.535 22.905 21.675 ;
        RECT 23.575 20.535 23.835 21.675 ;
        RECT 9.285 16.405 9.565 17.545 ;
        RECT 10.235 16.405 10.495 17.545 ;
        RECT 17.360 16.405 17.570 17.545 ;
        RECT 1.380 16.235 28.980 16.405 ;
        RECT 11.095 15.435 11.410 16.235 ;
        RECT 12.455 15.095 12.785 16.235 ;
        RECT 15.265 15.070 15.555 16.235 ;
        RECT 16.695 15.775 16.905 16.235 ;
        RECT 18.455 15.055 18.775 16.235 ;
        RECT 18.950 15.095 19.205 16.235 ;
        RECT 19.875 15.435 20.105 16.235 ;
        RECT 9.285 10.965 9.545 12.105 ;
        RECT 10.215 10.965 10.385 11.765 ;
        RECT 11.055 10.965 11.310 11.765 ;
        RECT 16.645 10.965 16.925 12.105 ;
        RECT 17.595 10.965 17.855 12.105 ;
        RECT 18.085 10.965 18.415 11.775 ;
        RECT 19.410 10.965 19.665 11.745 ;
        RECT 20.330 10.965 20.585 12.105 ;
        RECT 21.255 10.965 21.485 11.765 ;
        RECT 1.380 10.795 28.980 10.965 ;
        RECT 8.425 9.985 8.755 10.795 ;
        RECT 9.750 10.015 10.005 10.795 ;
        RECT 10.665 9.655 10.945 10.795 ;
        RECT 11.615 9.655 11.875 10.795 ;
        RECT 12.540 9.960 12.800 10.795 ;
        RECT 13.400 9.960 13.655 10.795 ;
        RECT 15.265 9.630 15.555 10.795 ;
        RECT 17.360 9.655 17.570 10.795 ;
        RECT 19.915 9.945 20.085 10.795 ;
        RECT 20.755 10.285 20.925 10.795 ;
        RECT 22.165 9.655 22.445 10.795 ;
        RECT 23.115 9.655 23.375 10.795 ;
        RECT 7.905 5.525 8.185 6.665 ;
        RECT 8.855 5.525 9.115 6.665 ;
        RECT 12.300 5.525 12.510 6.665 ;
        RECT 13.425 5.525 13.705 6.665 ;
        RECT 14.375 5.525 14.635 6.665 ;
        RECT 15.265 5.525 15.545 6.665 ;
        RECT 16.215 5.525 16.475 6.665 ;
        RECT 17.085 5.525 17.415 6.285 ;
        RECT 18.280 5.525 18.490 6.665 ;
        RECT 19.465 5.525 19.795 6.335 ;
        RECT 20.790 5.525 21.045 6.305 ;
        RECT 21.250 5.525 21.505 6.665 ;
        RECT 22.175 5.525 22.405 6.325 ;
        RECT 23.085 5.525 23.365 6.665 ;
        RECT 24.035 5.525 24.295 6.665 ;
        RECT 1.380 5.355 28.980 5.525 ;
        RECT 15.265 4.190 15.555 5.355 ;
        RECT 16.165 4.595 16.495 5.355 ;
        RECT 17.545 4.575 17.875 5.355 ;
        RECT 18.435 4.930 18.770 5.355 ;
        RECT 19.385 4.575 19.715 5.355 ;
        RECT 20.275 4.930 20.610 5.355 ;
        RECT 21.225 4.575 21.555 5.355 ;
        RECT 22.115 4.930 22.450 5.355 ;
        RECT 25.070 4.930 25.455 5.355 ;
        RECT 26.665 4.930 27.050 5.355 ;
        RECT 28.080 4.930 28.465 5.355 ;
      LAYER mcon ;
        RECT 1.525 37.995 1.695 38.165 ;
        RECT 1.985 37.995 2.155 38.165 ;
        RECT 2.445 37.995 2.615 38.165 ;
        RECT 2.905 37.995 3.075 38.165 ;
        RECT 3.365 37.995 3.535 38.165 ;
        RECT 3.825 37.995 3.995 38.165 ;
        RECT 4.285 37.995 4.455 38.165 ;
        RECT 4.745 37.995 4.915 38.165 ;
        RECT 5.205 37.995 5.375 38.165 ;
        RECT 5.665 37.995 5.835 38.165 ;
        RECT 6.125 37.995 6.295 38.165 ;
        RECT 6.585 37.995 6.755 38.165 ;
        RECT 7.045 37.995 7.215 38.165 ;
        RECT 7.505 37.995 7.675 38.165 ;
        RECT 7.965 37.995 8.135 38.165 ;
        RECT 8.425 37.995 8.595 38.165 ;
        RECT 8.885 37.995 9.055 38.165 ;
        RECT 9.345 37.995 9.515 38.165 ;
        RECT 9.805 37.995 9.975 38.165 ;
        RECT 10.265 37.995 10.435 38.165 ;
        RECT 10.725 37.995 10.895 38.165 ;
        RECT 11.185 37.995 11.355 38.165 ;
        RECT 11.645 37.995 11.815 38.165 ;
        RECT 12.105 37.995 12.275 38.165 ;
        RECT 12.565 37.995 12.735 38.165 ;
        RECT 13.025 37.995 13.195 38.165 ;
        RECT 13.485 37.995 13.655 38.165 ;
        RECT 13.945 37.995 14.115 38.165 ;
        RECT 14.405 37.995 14.575 38.165 ;
        RECT 14.865 37.995 15.035 38.165 ;
        RECT 15.325 37.995 15.495 38.165 ;
        RECT 15.785 37.995 15.955 38.165 ;
        RECT 16.245 37.995 16.415 38.165 ;
        RECT 16.705 37.995 16.875 38.165 ;
        RECT 17.165 37.995 17.335 38.165 ;
        RECT 17.625 37.995 17.795 38.165 ;
        RECT 18.085 37.995 18.255 38.165 ;
        RECT 18.545 37.995 18.715 38.165 ;
        RECT 19.005 37.995 19.175 38.165 ;
        RECT 19.465 37.995 19.635 38.165 ;
        RECT 19.925 37.995 20.095 38.165 ;
        RECT 20.385 37.995 20.555 38.165 ;
        RECT 20.845 37.995 21.015 38.165 ;
        RECT 21.305 37.995 21.475 38.165 ;
        RECT 21.765 37.995 21.935 38.165 ;
        RECT 22.225 37.995 22.395 38.165 ;
        RECT 22.685 37.995 22.855 38.165 ;
        RECT 23.145 37.995 23.315 38.165 ;
        RECT 23.605 37.995 23.775 38.165 ;
        RECT 24.065 37.995 24.235 38.165 ;
        RECT 24.525 37.995 24.695 38.165 ;
        RECT 24.985 37.995 25.155 38.165 ;
        RECT 25.445 37.995 25.615 38.165 ;
        RECT 25.905 37.995 26.075 38.165 ;
        RECT 26.365 37.995 26.535 38.165 ;
        RECT 26.825 37.995 26.995 38.165 ;
        RECT 27.285 37.995 27.455 38.165 ;
        RECT 27.745 37.995 27.915 38.165 ;
        RECT 28.205 37.995 28.375 38.165 ;
        RECT 28.665 37.995 28.835 38.165 ;
        RECT 1.525 32.555 1.695 32.725 ;
        RECT 1.985 32.555 2.155 32.725 ;
        RECT 2.445 32.555 2.615 32.725 ;
        RECT 2.905 32.555 3.075 32.725 ;
        RECT 3.365 32.555 3.535 32.725 ;
        RECT 3.825 32.555 3.995 32.725 ;
        RECT 4.285 32.555 4.455 32.725 ;
        RECT 4.745 32.555 4.915 32.725 ;
        RECT 5.205 32.555 5.375 32.725 ;
        RECT 5.665 32.555 5.835 32.725 ;
        RECT 6.125 32.555 6.295 32.725 ;
        RECT 6.585 32.555 6.755 32.725 ;
        RECT 7.045 32.555 7.215 32.725 ;
        RECT 7.505 32.555 7.675 32.725 ;
        RECT 7.965 32.555 8.135 32.725 ;
        RECT 8.425 32.555 8.595 32.725 ;
        RECT 8.885 32.555 9.055 32.725 ;
        RECT 9.345 32.555 9.515 32.725 ;
        RECT 9.805 32.555 9.975 32.725 ;
        RECT 10.265 32.555 10.435 32.725 ;
        RECT 10.725 32.555 10.895 32.725 ;
        RECT 11.185 32.555 11.355 32.725 ;
        RECT 11.645 32.555 11.815 32.725 ;
        RECT 12.105 32.555 12.275 32.725 ;
        RECT 12.565 32.555 12.735 32.725 ;
        RECT 13.025 32.555 13.195 32.725 ;
        RECT 13.485 32.555 13.655 32.725 ;
        RECT 13.945 32.555 14.115 32.725 ;
        RECT 14.405 32.555 14.575 32.725 ;
        RECT 14.865 32.555 15.035 32.725 ;
        RECT 15.325 32.555 15.495 32.725 ;
        RECT 15.785 32.555 15.955 32.725 ;
        RECT 16.245 32.555 16.415 32.725 ;
        RECT 16.705 32.555 16.875 32.725 ;
        RECT 17.165 32.555 17.335 32.725 ;
        RECT 17.625 32.555 17.795 32.725 ;
        RECT 18.085 32.555 18.255 32.725 ;
        RECT 18.545 32.555 18.715 32.725 ;
        RECT 19.005 32.555 19.175 32.725 ;
        RECT 19.465 32.555 19.635 32.725 ;
        RECT 19.925 32.555 20.095 32.725 ;
        RECT 20.385 32.555 20.555 32.725 ;
        RECT 20.845 32.555 21.015 32.725 ;
        RECT 21.305 32.555 21.475 32.725 ;
        RECT 21.765 32.555 21.935 32.725 ;
        RECT 22.225 32.555 22.395 32.725 ;
        RECT 22.685 32.555 22.855 32.725 ;
        RECT 23.145 32.555 23.315 32.725 ;
        RECT 23.605 32.555 23.775 32.725 ;
        RECT 24.065 32.555 24.235 32.725 ;
        RECT 24.525 32.555 24.695 32.725 ;
        RECT 24.985 32.555 25.155 32.725 ;
        RECT 25.445 32.555 25.615 32.725 ;
        RECT 25.905 32.555 26.075 32.725 ;
        RECT 26.365 32.555 26.535 32.725 ;
        RECT 26.825 32.555 26.995 32.725 ;
        RECT 27.285 32.555 27.455 32.725 ;
        RECT 27.745 32.555 27.915 32.725 ;
        RECT 28.205 32.555 28.375 32.725 ;
        RECT 28.665 32.555 28.835 32.725 ;
        RECT 1.525 27.115 1.695 27.285 ;
        RECT 1.985 27.115 2.155 27.285 ;
        RECT 2.445 27.115 2.615 27.285 ;
        RECT 2.905 27.115 3.075 27.285 ;
        RECT 3.365 27.115 3.535 27.285 ;
        RECT 3.825 27.115 3.995 27.285 ;
        RECT 4.285 27.115 4.455 27.285 ;
        RECT 4.745 27.115 4.915 27.285 ;
        RECT 5.205 27.115 5.375 27.285 ;
        RECT 5.665 27.115 5.835 27.285 ;
        RECT 6.125 27.115 6.295 27.285 ;
        RECT 6.585 27.115 6.755 27.285 ;
        RECT 7.045 27.115 7.215 27.285 ;
        RECT 7.505 27.115 7.675 27.285 ;
        RECT 7.965 27.115 8.135 27.285 ;
        RECT 8.425 27.115 8.595 27.285 ;
        RECT 8.885 27.115 9.055 27.285 ;
        RECT 9.345 27.115 9.515 27.285 ;
        RECT 9.805 27.115 9.975 27.285 ;
        RECT 10.265 27.115 10.435 27.285 ;
        RECT 10.725 27.115 10.895 27.285 ;
        RECT 11.185 27.115 11.355 27.285 ;
        RECT 11.645 27.115 11.815 27.285 ;
        RECT 12.105 27.115 12.275 27.285 ;
        RECT 12.565 27.115 12.735 27.285 ;
        RECT 13.025 27.115 13.195 27.285 ;
        RECT 13.485 27.115 13.655 27.285 ;
        RECT 13.945 27.115 14.115 27.285 ;
        RECT 14.405 27.115 14.575 27.285 ;
        RECT 14.865 27.115 15.035 27.285 ;
        RECT 15.325 27.115 15.495 27.285 ;
        RECT 15.785 27.115 15.955 27.285 ;
        RECT 16.245 27.115 16.415 27.285 ;
        RECT 16.705 27.115 16.875 27.285 ;
        RECT 17.165 27.115 17.335 27.285 ;
        RECT 17.625 27.115 17.795 27.285 ;
        RECT 18.085 27.115 18.255 27.285 ;
        RECT 18.545 27.115 18.715 27.285 ;
        RECT 19.005 27.115 19.175 27.285 ;
        RECT 19.465 27.115 19.635 27.285 ;
        RECT 19.925 27.115 20.095 27.285 ;
        RECT 20.385 27.115 20.555 27.285 ;
        RECT 20.845 27.115 21.015 27.285 ;
        RECT 21.305 27.115 21.475 27.285 ;
        RECT 21.765 27.115 21.935 27.285 ;
        RECT 22.225 27.115 22.395 27.285 ;
        RECT 22.685 27.115 22.855 27.285 ;
        RECT 23.145 27.115 23.315 27.285 ;
        RECT 23.605 27.115 23.775 27.285 ;
        RECT 24.065 27.115 24.235 27.285 ;
        RECT 24.525 27.115 24.695 27.285 ;
        RECT 24.985 27.115 25.155 27.285 ;
        RECT 25.445 27.115 25.615 27.285 ;
        RECT 25.905 27.115 26.075 27.285 ;
        RECT 26.365 27.115 26.535 27.285 ;
        RECT 26.825 27.115 26.995 27.285 ;
        RECT 27.285 27.115 27.455 27.285 ;
        RECT 27.745 27.115 27.915 27.285 ;
        RECT 28.205 27.115 28.375 27.285 ;
        RECT 28.665 27.115 28.835 27.285 ;
        RECT 1.525 21.675 1.695 21.845 ;
        RECT 1.985 21.675 2.155 21.845 ;
        RECT 2.445 21.675 2.615 21.845 ;
        RECT 2.905 21.675 3.075 21.845 ;
        RECT 3.365 21.675 3.535 21.845 ;
        RECT 3.825 21.675 3.995 21.845 ;
        RECT 4.285 21.675 4.455 21.845 ;
        RECT 4.745 21.675 4.915 21.845 ;
        RECT 5.205 21.675 5.375 21.845 ;
        RECT 5.665 21.675 5.835 21.845 ;
        RECT 6.125 21.675 6.295 21.845 ;
        RECT 6.585 21.675 6.755 21.845 ;
        RECT 7.045 21.675 7.215 21.845 ;
        RECT 7.505 21.675 7.675 21.845 ;
        RECT 7.965 21.675 8.135 21.845 ;
        RECT 8.425 21.675 8.595 21.845 ;
        RECT 8.885 21.675 9.055 21.845 ;
        RECT 9.345 21.675 9.515 21.845 ;
        RECT 9.805 21.675 9.975 21.845 ;
        RECT 10.265 21.675 10.435 21.845 ;
        RECT 10.725 21.675 10.895 21.845 ;
        RECT 11.185 21.675 11.355 21.845 ;
        RECT 11.645 21.675 11.815 21.845 ;
        RECT 12.105 21.675 12.275 21.845 ;
        RECT 12.565 21.675 12.735 21.845 ;
        RECT 13.025 21.675 13.195 21.845 ;
        RECT 13.485 21.675 13.655 21.845 ;
        RECT 13.945 21.675 14.115 21.845 ;
        RECT 14.405 21.675 14.575 21.845 ;
        RECT 14.865 21.675 15.035 21.845 ;
        RECT 15.325 21.675 15.495 21.845 ;
        RECT 15.785 21.675 15.955 21.845 ;
        RECT 16.245 21.675 16.415 21.845 ;
        RECT 16.705 21.675 16.875 21.845 ;
        RECT 17.165 21.675 17.335 21.845 ;
        RECT 17.625 21.675 17.795 21.845 ;
        RECT 18.085 21.675 18.255 21.845 ;
        RECT 18.545 21.675 18.715 21.845 ;
        RECT 19.005 21.675 19.175 21.845 ;
        RECT 19.465 21.675 19.635 21.845 ;
        RECT 19.925 21.675 20.095 21.845 ;
        RECT 20.385 21.675 20.555 21.845 ;
        RECT 20.845 21.675 21.015 21.845 ;
        RECT 21.305 21.675 21.475 21.845 ;
        RECT 21.765 21.675 21.935 21.845 ;
        RECT 22.225 21.675 22.395 21.845 ;
        RECT 22.685 21.675 22.855 21.845 ;
        RECT 23.145 21.675 23.315 21.845 ;
        RECT 23.605 21.675 23.775 21.845 ;
        RECT 24.065 21.675 24.235 21.845 ;
        RECT 24.525 21.675 24.695 21.845 ;
        RECT 24.985 21.675 25.155 21.845 ;
        RECT 25.445 21.675 25.615 21.845 ;
        RECT 25.905 21.675 26.075 21.845 ;
        RECT 26.365 21.675 26.535 21.845 ;
        RECT 26.825 21.675 26.995 21.845 ;
        RECT 27.285 21.675 27.455 21.845 ;
        RECT 27.745 21.675 27.915 21.845 ;
        RECT 28.205 21.675 28.375 21.845 ;
        RECT 28.665 21.675 28.835 21.845 ;
        RECT 1.525 16.235 1.695 16.405 ;
        RECT 1.985 16.235 2.155 16.405 ;
        RECT 2.445 16.235 2.615 16.405 ;
        RECT 2.905 16.235 3.075 16.405 ;
        RECT 3.365 16.235 3.535 16.405 ;
        RECT 3.825 16.235 3.995 16.405 ;
        RECT 4.285 16.235 4.455 16.405 ;
        RECT 4.745 16.235 4.915 16.405 ;
        RECT 5.205 16.235 5.375 16.405 ;
        RECT 5.665 16.235 5.835 16.405 ;
        RECT 6.125 16.235 6.295 16.405 ;
        RECT 6.585 16.235 6.755 16.405 ;
        RECT 7.045 16.235 7.215 16.405 ;
        RECT 7.505 16.235 7.675 16.405 ;
        RECT 7.965 16.235 8.135 16.405 ;
        RECT 8.425 16.235 8.595 16.405 ;
        RECT 8.885 16.235 9.055 16.405 ;
        RECT 9.345 16.235 9.515 16.405 ;
        RECT 9.805 16.235 9.975 16.405 ;
        RECT 10.265 16.235 10.435 16.405 ;
        RECT 10.725 16.235 10.895 16.405 ;
        RECT 11.185 16.235 11.355 16.405 ;
        RECT 11.645 16.235 11.815 16.405 ;
        RECT 12.105 16.235 12.275 16.405 ;
        RECT 12.565 16.235 12.735 16.405 ;
        RECT 13.025 16.235 13.195 16.405 ;
        RECT 13.485 16.235 13.655 16.405 ;
        RECT 13.945 16.235 14.115 16.405 ;
        RECT 14.405 16.235 14.575 16.405 ;
        RECT 14.865 16.235 15.035 16.405 ;
        RECT 15.325 16.235 15.495 16.405 ;
        RECT 15.785 16.235 15.955 16.405 ;
        RECT 16.245 16.235 16.415 16.405 ;
        RECT 16.705 16.235 16.875 16.405 ;
        RECT 17.165 16.235 17.335 16.405 ;
        RECT 17.625 16.235 17.795 16.405 ;
        RECT 18.085 16.235 18.255 16.405 ;
        RECT 18.545 16.235 18.715 16.405 ;
        RECT 19.005 16.235 19.175 16.405 ;
        RECT 19.465 16.235 19.635 16.405 ;
        RECT 19.925 16.235 20.095 16.405 ;
        RECT 20.385 16.235 20.555 16.405 ;
        RECT 20.845 16.235 21.015 16.405 ;
        RECT 21.305 16.235 21.475 16.405 ;
        RECT 21.765 16.235 21.935 16.405 ;
        RECT 22.225 16.235 22.395 16.405 ;
        RECT 22.685 16.235 22.855 16.405 ;
        RECT 23.145 16.235 23.315 16.405 ;
        RECT 23.605 16.235 23.775 16.405 ;
        RECT 24.065 16.235 24.235 16.405 ;
        RECT 24.525 16.235 24.695 16.405 ;
        RECT 24.985 16.235 25.155 16.405 ;
        RECT 25.445 16.235 25.615 16.405 ;
        RECT 25.905 16.235 26.075 16.405 ;
        RECT 26.365 16.235 26.535 16.405 ;
        RECT 26.825 16.235 26.995 16.405 ;
        RECT 27.285 16.235 27.455 16.405 ;
        RECT 27.745 16.235 27.915 16.405 ;
        RECT 28.205 16.235 28.375 16.405 ;
        RECT 28.665 16.235 28.835 16.405 ;
        RECT 1.525 10.795 1.695 10.965 ;
        RECT 1.985 10.795 2.155 10.965 ;
        RECT 2.445 10.795 2.615 10.965 ;
        RECT 2.905 10.795 3.075 10.965 ;
        RECT 3.365 10.795 3.535 10.965 ;
        RECT 3.825 10.795 3.995 10.965 ;
        RECT 4.285 10.795 4.455 10.965 ;
        RECT 4.745 10.795 4.915 10.965 ;
        RECT 5.205 10.795 5.375 10.965 ;
        RECT 5.665 10.795 5.835 10.965 ;
        RECT 6.125 10.795 6.295 10.965 ;
        RECT 6.585 10.795 6.755 10.965 ;
        RECT 7.045 10.795 7.215 10.965 ;
        RECT 7.505 10.795 7.675 10.965 ;
        RECT 7.965 10.795 8.135 10.965 ;
        RECT 8.425 10.795 8.595 10.965 ;
        RECT 8.885 10.795 9.055 10.965 ;
        RECT 9.345 10.795 9.515 10.965 ;
        RECT 9.805 10.795 9.975 10.965 ;
        RECT 10.265 10.795 10.435 10.965 ;
        RECT 10.725 10.795 10.895 10.965 ;
        RECT 11.185 10.795 11.355 10.965 ;
        RECT 11.645 10.795 11.815 10.965 ;
        RECT 12.105 10.795 12.275 10.965 ;
        RECT 12.565 10.795 12.735 10.965 ;
        RECT 13.025 10.795 13.195 10.965 ;
        RECT 13.485 10.795 13.655 10.965 ;
        RECT 13.945 10.795 14.115 10.965 ;
        RECT 14.405 10.795 14.575 10.965 ;
        RECT 14.865 10.795 15.035 10.965 ;
        RECT 15.325 10.795 15.495 10.965 ;
        RECT 15.785 10.795 15.955 10.965 ;
        RECT 16.245 10.795 16.415 10.965 ;
        RECT 16.705 10.795 16.875 10.965 ;
        RECT 17.165 10.795 17.335 10.965 ;
        RECT 17.625 10.795 17.795 10.965 ;
        RECT 18.085 10.795 18.255 10.965 ;
        RECT 18.545 10.795 18.715 10.965 ;
        RECT 19.005 10.795 19.175 10.965 ;
        RECT 19.465 10.795 19.635 10.965 ;
        RECT 19.925 10.795 20.095 10.965 ;
        RECT 20.385 10.795 20.555 10.965 ;
        RECT 20.845 10.795 21.015 10.965 ;
        RECT 21.305 10.795 21.475 10.965 ;
        RECT 21.765 10.795 21.935 10.965 ;
        RECT 22.225 10.795 22.395 10.965 ;
        RECT 22.685 10.795 22.855 10.965 ;
        RECT 23.145 10.795 23.315 10.965 ;
        RECT 23.605 10.795 23.775 10.965 ;
        RECT 24.065 10.795 24.235 10.965 ;
        RECT 24.525 10.795 24.695 10.965 ;
        RECT 24.985 10.795 25.155 10.965 ;
        RECT 25.445 10.795 25.615 10.965 ;
        RECT 25.905 10.795 26.075 10.965 ;
        RECT 26.365 10.795 26.535 10.965 ;
        RECT 26.825 10.795 26.995 10.965 ;
        RECT 27.285 10.795 27.455 10.965 ;
        RECT 27.745 10.795 27.915 10.965 ;
        RECT 28.205 10.795 28.375 10.965 ;
        RECT 28.665 10.795 28.835 10.965 ;
        RECT 1.525 5.355 1.695 5.525 ;
        RECT 1.985 5.355 2.155 5.525 ;
        RECT 2.445 5.355 2.615 5.525 ;
        RECT 2.905 5.355 3.075 5.525 ;
        RECT 3.365 5.355 3.535 5.525 ;
        RECT 3.825 5.355 3.995 5.525 ;
        RECT 4.285 5.355 4.455 5.525 ;
        RECT 4.745 5.355 4.915 5.525 ;
        RECT 5.205 5.355 5.375 5.525 ;
        RECT 5.665 5.355 5.835 5.525 ;
        RECT 6.125 5.355 6.295 5.525 ;
        RECT 6.585 5.355 6.755 5.525 ;
        RECT 7.045 5.355 7.215 5.525 ;
        RECT 7.505 5.355 7.675 5.525 ;
        RECT 7.965 5.355 8.135 5.525 ;
        RECT 8.425 5.355 8.595 5.525 ;
        RECT 8.885 5.355 9.055 5.525 ;
        RECT 9.345 5.355 9.515 5.525 ;
        RECT 9.805 5.355 9.975 5.525 ;
        RECT 10.265 5.355 10.435 5.525 ;
        RECT 10.725 5.355 10.895 5.525 ;
        RECT 11.185 5.355 11.355 5.525 ;
        RECT 11.645 5.355 11.815 5.525 ;
        RECT 12.105 5.355 12.275 5.525 ;
        RECT 12.565 5.355 12.735 5.525 ;
        RECT 13.025 5.355 13.195 5.525 ;
        RECT 13.485 5.355 13.655 5.525 ;
        RECT 13.945 5.355 14.115 5.525 ;
        RECT 14.405 5.355 14.575 5.525 ;
        RECT 14.865 5.355 15.035 5.525 ;
        RECT 15.325 5.355 15.495 5.525 ;
        RECT 15.785 5.355 15.955 5.525 ;
        RECT 16.245 5.355 16.415 5.525 ;
        RECT 16.705 5.355 16.875 5.525 ;
        RECT 17.165 5.355 17.335 5.525 ;
        RECT 17.625 5.355 17.795 5.525 ;
        RECT 18.085 5.355 18.255 5.525 ;
        RECT 18.545 5.355 18.715 5.525 ;
        RECT 19.005 5.355 19.175 5.525 ;
        RECT 19.465 5.355 19.635 5.525 ;
        RECT 19.925 5.355 20.095 5.525 ;
        RECT 20.385 5.355 20.555 5.525 ;
        RECT 20.845 5.355 21.015 5.525 ;
        RECT 21.305 5.355 21.475 5.525 ;
        RECT 21.765 5.355 21.935 5.525 ;
        RECT 22.225 5.355 22.395 5.525 ;
        RECT 22.685 5.355 22.855 5.525 ;
        RECT 23.145 5.355 23.315 5.525 ;
        RECT 23.605 5.355 23.775 5.525 ;
        RECT 24.065 5.355 24.235 5.525 ;
        RECT 24.525 5.355 24.695 5.525 ;
        RECT 24.985 5.355 25.155 5.525 ;
        RECT 25.445 5.355 25.615 5.525 ;
        RECT 25.905 5.355 26.075 5.525 ;
        RECT 26.365 5.355 26.535 5.525 ;
        RECT 26.825 5.355 26.995 5.525 ;
        RECT 27.285 5.355 27.455 5.525 ;
        RECT 27.745 5.355 27.915 5.525 ;
        RECT 28.205 5.355 28.375 5.525 ;
        RECT 28.665 5.355 28.835 5.525 ;
      LAYER met1 ;
        RECT -10.620 37.840 40.980 38.320 ;
        RECT -10.620 32.400 40.980 32.880 ;
        RECT -10.620 26.960 40.980 27.440 ;
        RECT -10.620 21.520 40.980 22.000 ;
        RECT -10.620 16.080 40.980 16.560 ;
        RECT -10.620 10.640 40.980 11.120 ;
        RECT -10.620 5.200 40.980 5.680 ;
      LAYER via ;
        RECT -4.770 37.950 -4.510 38.210 ;
        RECT -4.450 37.950 -4.190 38.210 ;
        RECT -4.130 37.950 -3.870 38.210 ;
        RECT -3.810 37.950 -3.550 38.210 ;
        RECT -3.490 37.950 -3.230 38.210 ;
        RECT -3.170 37.950 -2.910 38.210 ;
        RECT -2.850 37.950 -2.590 38.210 ;
        RECT -2.530 37.950 -2.270 38.210 ;
        RECT -2.210 37.950 -1.950 38.210 ;
        RECT -1.890 37.950 -1.630 38.210 ;
        RECT -1.570 37.950 -1.310 38.210 ;
        RECT -1.250 37.950 -0.990 38.210 ;
        RECT -0.930 37.950 -0.670 38.210 ;
        RECT 31.030 37.950 31.290 38.210 ;
        RECT 31.350 37.950 31.610 38.210 ;
        RECT 31.670 37.950 31.930 38.210 ;
        RECT 31.990 37.950 32.250 38.210 ;
        RECT 32.310 37.950 32.570 38.210 ;
        RECT 32.630 37.950 32.890 38.210 ;
        RECT 32.950 37.950 33.210 38.210 ;
        RECT 33.270 37.950 33.530 38.210 ;
        RECT 33.590 37.950 33.850 38.210 ;
        RECT 33.910 37.950 34.170 38.210 ;
        RECT 34.230 37.950 34.490 38.210 ;
        RECT 34.550 37.950 34.810 38.210 ;
        RECT 34.870 37.950 35.130 38.210 ;
        RECT -4.770 32.510 -4.510 32.770 ;
        RECT -4.450 32.510 -4.190 32.770 ;
        RECT -4.130 32.510 -3.870 32.770 ;
        RECT -3.810 32.510 -3.550 32.770 ;
        RECT -3.490 32.510 -3.230 32.770 ;
        RECT -3.170 32.510 -2.910 32.770 ;
        RECT -2.850 32.510 -2.590 32.770 ;
        RECT -2.530 32.510 -2.270 32.770 ;
        RECT -2.210 32.510 -1.950 32.770 ;
        RECT -1.890 32.510 -1.630 32.770 ;
        RECT -1.570 32.510 -1.310 32.770 ;
        RECT -1.250 32.510 -0.990 32.770 ;
        RECT -0.930 32.510 -0.670 32.770 ;
        RECT 31.030 32.510 31.290 32.770 ;
        RECT 31.350 32.510 31.610 32.770 ;
        RECT 31.670 32.510 31.930 32.770 ;
        RECT 31.990 32.510 32.250 32.770 ;
        RECT 32.310 32.510 32.570 32.770 ;
        RECT 32.630 32.510 32.890 32.770 ;
        RECT 32.950 32.510 33.210 32.770 ;
        RECT 33.270 32.510 33.530 32.770 ;
        RECT 33.590 32.510 33.850 32.770 ;
        RECT 33.910 32.510 34.170 32.770 ;
        RECT 34.230 32.510 34.490 32.770 ;
        RECT 34.550 32.510 34.810 32.770 ;
        RECT 34.870 32.510 35.130 32.770 ;
        RECT -4.770 27.070 -4.510 27.330 ;
        RECT -4.450 27.070 -4.190 27.330 ;
        RECT -4.130 27.070 -3.870 27.330 ;
        RECT -3.810 27.070 -3.550 27.330 ;
        RECT -3.490 27.070 -3.230 27.330 ;
        RECT -3.170 27.070 -2.910 27.330 ;
        RECT -2.850 27.070 -2.590 27.330 ;
        RECT -2.530 27.070 -2.270 27.330 ;
        RECT -2.210 27.070 -1.950 27.330 ;
        RECT -1.890 27.070 -1.630 27.330 ;
        RECT -1.570 27.070 -1.310 27.330 ;
        RECT -1.250 27.070 -0.990 27.330 ;
        RECT -0.930 27.070 -0.670 27.330 ;
        RECT 31.030 27.070 31.290 27.330 ;
        RECT 31.350 27.070 31.610 27.330 ;
        RECT 31.670 27.070 31.930 27.330 ;
        RECT 31.990 27.070 32.250 27.330 ;
        RECT 32.310 27.070 32.570 27.330 ;
        RECT 32.630 27.070 32.890 27.330 ;
        RECT 32.950 27.070 33.210 27.330 ;
        RECT 33.270 27.070 33.530 27.330 ;
        RECT 33.590 27.070 33.850 27.330 ;
        RECT 33.910 27.070 34.170 27.330 ;
        RECT 34.230 27.070 34.490 27.330 ;
        RECT 34.550 27.070 34.810 27.330 ;
        RECT 34.870 27.070 35.130 27.330 ;
        RECT -4.770 21.630 -4.510 21.890 ;
        RECT -4.450 21.630 -4.190 21.890 ;
        RECT -4.130 21.630 -3.870 21.890 ;
        RECT -3.810 21.630 -3.550 21.890 ;
        RECT -3.490 21.630 -3.230 21.890 ;
        RECT -3.170 21.630 -2.910 21.890 ;
        RECT -2.850 21.630 -2.590 21.890 ;
        RECT -2.530 21.630 -2.270 21.890 ;
        RECT -2.210 21.630 -1.950 21.890 ;
        RECT -1.890 21.630 -1.630 21.890 ;
        RECT -1.570 21.630 -1.310 21.890 ;
        RECT -1.250 21.630 -0.990 21.890 ;
        RECT -0.930 21.630 -0.670 21.890 ;
        RECT 31.030 21.630 31.290 21.890 ;
        RECT 31.350 21.630 31.610 21.890 ;
        RECT 31.670 21.630 31.930 21.890 ;
        RECT 31.990 21.630 32.250 21.890 ;
        RECT 32.310 21.630 32.570 21.890 ;
        RECT 32.630 21.630 32.890 21.890 ;
        RECT 32.950 21.630 33.210 21.890 ;
        RECT 33.270 21.630 33.530 21.890 ;
        RECT 33.590 21.630 33.850 21.890 ;
        RECT 33.910 21.630 34.170 21.890 ;
        RECT 34.230 21.630 34.490 21.890 ;
        RECT 34.550 21.630 34.810 21.890 ;
        RECT 34.870 21.630 35.130 21.890 ;
        RECT -4.770 16.190 -4.510 16.450 ;
        RECT -4.450 16.190 -4.190 16.450 ;
        RECT -4.130 16.190 -3.870 16.450 ;
        RECT -3.810 16.190 -3.550 16.450 ;
        RECT -3.490 16.190 -3.230 16.450 ;
        RECT -3.170 16.190 -2.910 16.450 ;
        RECT -2.850 16.190 -2.590 16.450 ;
        RECT -2.530 16.190 -2.270 16.450 ;
        RECT -2.210 16.190 -1.950 16.450 ;
        RECT -1.890 16.190 -1.630 16.450 ;
        RECT -1.570 16.190 -1.310 16.450 ;
        RECT -1.250 16.190 -0.990 16.450 ;
        RECT -0.930 16.190 -0.670 16.450 ;
        RECT 31.030 16.190 31.290 16.450 ;
        RECT 31.350 16.190 31.610 16.450 ;
        RECT 31.670 16.190 31.930 16.450 ;
        RECT 31.990 16.190 32.250 16.450 ;
        RECT 32.310 16.190 32.570 16.450 ;
        RECT 32.630 16.190 32.890 16.450 ;
        RECT 32.950 16.190 33.210 16.450 ;
        RECT 33.270 16.190 33.530 16.450 ;
        RECT 33.590 16.190 33.850 16.450 ;
        RECT 33.910 16.190 34.170 16.450 ;
        RECT 34.230 16.190 34.490 16.450 ;
        RECT 34.550 16.190 34.810 16.450 ;
        RECT 34.870 16.190 35.130 16.450 ;
        RECT -4.770 10.750 -4.510 11.010 ;
        RECT -4.450 10.750 -4.190 11.010 ;
        RECT -4.130 10.750 -3.870 11.010 ;
        RECT -3.810 10.750 -3.550 11.010 ;
        RECT -3.490 10.750 -3.230 11.010 ;
        RECT -3.170 10.750 -2.910 11.010 ;
        RECT -2.850 10.750 -2.590 11.010 ;
        RECT -2.530 10.750 -2.270 11.010 ;
        RECT -2.210 10.750 -1.950 11.010 ;
        RECT -1.890 10.750 -1.630 11.010 ;
        RECT -1.570 10.750 -1.310 11.010 ;
        RECT -1.250 10.750 -0.990 11.010 ;
        RECT -0.930 10.750 -0.670 11.010 ;
        RECT 31.030 10.750 31.290 11.010 ;
        RECT 31.350 10.750 31.610 11.010 ;
        RECT 31.670 10.750 31.930 11.010 ;
        RECT 31.990 10.750 32.250 11.010 ;
        RECT 32.310 10.750 32.570 11.010 ;
        RECT 32.630 10.750 32.890 11.010 ;
        RECT 32.950 10.750 33.210 11.010 ;
        RECT 33.270 10.750 33.530 11.010 ;
        RECT 33.590 10.750 33.850 11.010 ;
        RECT 33.910 10.750 34.170 11.010 ;
        RECT 34.230 10.750 34.490 11.010 ;
        RECT 34.550 10.750 34.810 11.010 ;
        RECT 34.870 10.750 35.130 11.010 ;
        RECT -4.770 5.310 -4.510 5.570 ;
        RECT -4.450 5.310 -4.190 5.570 ;
        RECT -4.130 5.310 -3.870 5.570 ;
        RECT -3.810 5.310 -3.550 5.570 ;
        RECT -3.490 5.310 -3.230 5.570 ;
        RECT -3.170 5.310 -2.910 5.570 ;
        RECT -2.850 5.310 -2.590 5.570 ;
        RECT -2.530 5.310 -2.270 5.570 ;
        RECT -2.210 5.310 -1.950 5.570 ;
        RECT -1.890 5.310 -1.630 5.570 ;
        RECT -1.570 5.310 -1.310 5.570 ;
        RECT -1.250 5.310 -0.990 5.570 ;
        RECT -0.930 5.310 -0.670 5.570 ;
        RECT 31.030 5.310 31.290 5.570 ;
        RECT 31.350 5.310 31.610 5.570 ;
        RECT 31.670 5.310 31.930 5.570 ;
        RECT 31.990 5.310 32.250 5.570 ;
        RECT 32.310 5.310 32.570 5.570 ;
        RECT 32.630 5.310 32.890 5.570 ;
        RECT 32.950 5.310 33.210 5.570 ;
        RECT 33.270 5.310 33.530 5.570 ;
        RECT 33.590 5.310 33.850 5.570 ;
        RECT 33.910 5.310 34.170 5.570 ;
        RECT 34.230 5.310 34.490 5.570 ;
        RECT 34.550 5.310 34.810 5.570 ;
        RECT 34.870 5.310 35.130 5.570 ;
      LAYER met2 ;
        RECT -4.770 37.840 -0.670 38.320 ;
        RECT 31.030 37.840 35.130 38.320 ;
        RECT -4.770 32.400 -0.670 32.880 ;
        RECT 31.030 32.400 35.130 32.880 ;
        RECT -4.770 26.960 -0.670 27.440 ;
        RECT 31.030 26.960 35.130 27.440 ;
        RECT -4.770 21.520 -0.670 22.000 ;
        RECT 31.030 21.520 35.130 22.000 ;
        RECT -4.770 16.080 -0.670 16.560 ;
        RECT 31.030 16.080 35.130 16.560 ;
        RECT -4.770 10.640 -0.670 11.120 ;
        RECT 31.030 10.640 35.130 11.120 ;
        RECT -4.770 5.200 -0.670 5.680 ;
        RECT 31.030 5.200 35.130 5.680 ;
      LAYER via2 ;
        RECT -4.660 37.940 -4.380 38.220 ;
        RECT -4.260 37.940 -3.980 38.220 ;
        RECT -3.860 37.940 -3.580 38.220 ;
        RECT -3.460 37.940 -3.180 38.220 ;
        RECT -3.060 37.940 -2.780 38.220 ;
        RECT -2.660 37.940 -2.380 38.220 ;
        RECT -2.260 37.940 -1.980 38.220 ;
        RECT -1.860 37.940 -1.580 38.220 ;
        RECT -1.460 37.940 -1.180 38.220 ;
        RECT -1.060 37.940 -0.780 38.220 ;
        RECT 31.140 37.940 31.420 38.220 ;
        RECT 31.540 37.940 31.820 38.220 ;
        RECT 31.940 37.940 32.220 38.220 ;
        RECT 32.340 37.940 32.620 38.220 ;
        RECT 32.740 37.940 33.020 38.220 ;
        RECT 33.140 37.940 33.420 38.220 ;
        RECT 33.540 37.940 33.820 38.220 ;
        RECT 33.940 37.940 34.220 38.220 ;
        RECT 34.340 37.940 34.620 38.220 ;
        RECT 34.740 37.940 35.020 38.220 ;
        RECT -4.660 32.500 -4.380 32.780 ;
        RECT -4.260 32.500 -3.980 32.780 ;
        RECT -3.860 32.500 -3.580 32.780 ;
        RECT -3.460 32.500 -3.180 32.780 ;
        RECT -3.060 32.500 -2.780 32.780 ;
        RECT -2.660 32.500 -2.380 32.780 ;
        RECT -2.260 32.500 -1.980 32.780 ;
        RECT -1.860 32.500 -1.580 32.780 ;
        RECT -1.460 32.500 -1.180 32.780 ;
        RECT -1.060 32.500 -0.780 32.780 ;
        RECT 31.140 32.500 31.420 32.780 ;
        RECT 31.540 32.500 31.820 32.780 ;
        RECT 31.940 32.500 32.220 32.780 ;
        RECT 32.340 32.500 32.620 32.780 ;
        RECT 32.740 32.500 33.020 32.780 ;
        RECT 33.140 32.500 33.420 32.780 ;
        RECT 33.540 32.500 33.820 32.780 ;
        RECT 33.940 32.500 34.220 32.780 ;
        RECT 34.340 32.500 34.620 32.780 ;
        RECT 34.740 32.500 35.020 32.780 ;
        RECT -4.660 27.060 -4.380 27.340 ;
        RECT -4.260 27.060 -3.980 27.340 ;
        RECT -3.860 27.060 -3.580 27.340 ;
        RECT -3.460 27.060 -3.180 27.340 ;
        RECT -3.060 27.060 -2.780 27.340 ;
        RECT -2.660 27.060 -2.380 27.340 ;
        RECT -2.260 27.060 -1.980 27.340 ;
        RECT -1.860 27.060 -1.580 27.340 ;
        RECT -1.460 27.060 -1.180 27.340 ;
        RECT -1.060 27.060 -0.780 27.340 ;
        RECT 31.140 27.060 31.420 27.340 ;
        RECT 31.540 27.060 31.820 27.340 ;
        RECT 31.940 27.060 32.220 27.340 ;
        RECT 32.340 27.060 32.620 27.340 ;
        RECT 32.740 27.060 33.020 27.340 ;
        RECT 33.140 27.060 33.420 27.340 ;
        RECT 33.540 27.060 33.820 27.340 ;
        RECT 33.940 27.060 34.220 27.340 ;
        RECT 34.340 27.060 34.620 27.340 ;
        RECT 34.740 27.060 35.020 27.340 ;
        RECT -4.660 21.620 -4.380 21.900 ;
        RECT -4.260 21.620 -3.980 21.900 ;
        RECT -3.860 21.620 -3.580 21.900 ;
        RECT -3.460 21.620 -3.180 21.900 ;
        RECT -3.060 21.620 -2.780 21.900 ;
        RECT -2.660 21.620 -2.380 21.900 ;
        RECT -2.260 21.620 -1.980 21.900 ;
        RECT -1.860 21.620 -1.580 21.900 ;
        RECT -1.460 21.620 -1.180 21.900 ;
        RECT -1.060 21.620 -0.780 21.900 ;
        RECT 31.140 21.620 31.420 21.900 ;
        RECT 31.540 21.620 31.820 21.900 ;
        RECT 31.940 21.620 32.220 21.900 ;
        RECT 32.340 21.620 32.620 21.900 ;
        RECT 32.740 21.620 33.020 21.900 ;
        RECT 33.140 21.620 33.420 21.900 ;
        RECT 33.540 21.620 33.820 21.900 ;
        RECT 33.940 21.620 34.220 21.900 ;
        RECT 34.340 21.620 34.620 21.900 ;
        RECT 34.740 21.620 35.020 21.900 ;
        RECT -4.660 16.180 -4.380 16.460 ;
        RECT -4.260 16.180 -3.980 16.460 ;
        RECT -3.860 16.180 -3.580 16.460 ;
        RECT -3.460 16.180 -3.180 16.460 ;
        RECT -3.060 16.180 -2.780 16.460 ;
        RECT -2.660 16.180 -2.380 16.460 ;
        RECT -2.260 16.180 -1.980 16.460 ;
        RECT -1.860 16.180 -1.580 16.460 ;
        RECT -1.460 16.180 -1.180 16.460 ;
        RECT -1.060 16.180 -0.780 16.460 ;
        RECT 31.140 16.180 31.420 16.460 ;
        RECT 31.540 16.180 31.820 16.460 ;
        RECT 31.940 16.180 32.220 16.460 ;
        RECT 32.340 16.180 32.620 16.460 ;
        RECT 32.740 16.180 33.020 16.460 ;
        RECT 33.140 16.180 33.420 16.460 ;
        RECT 33.540 16.180 33.820 16.460 ;
        RECT 33.940 16.180 34.220 16.460 ;
        RECT 34.340 16.180 34.620 16.460 ;
        RECT 34.740 16.180 35.020 16.460 ;
        RECT -4.660 10.740 -4.380 11.020 ;
        RECT -4.260 10.740 -3.980 11.020 ;
        RECT -3.860 10.740 -3.580 11.020 ;
        RECT -3.460 10.740 -3.180 11.020 ;
        RECT -3.060 10.740 -2.780 11.020 ;
        RECT -2.660 10.740 -2.380 11.020 ;
        RECT -2.260 10.740 -1.980 11.020 ;
        RECT -1.860 10.740 -1.580 11.020 ;
        RECT -1.460 10.740 -1.180 11.020 ;
        RECT -1.060 10.740 -0.780 11.020 ;
        RECT 31.140 10.740 31.420 11.020 ;
        RECT 31.540 10.740 31.820 11.020 ;
        RECT 31.940 10.740 32.220 11.020 ;
        RECT 32.340 10.740 32.620 11.020 ;
        RECT 32.740 10.740 33.020 11.020 ;
        RECT 33.140 10.740 33.420 11.020 ;
        RECT 33.540 10.740 33.820 11.020 ;
        RECT 33.940 10.740 34.220 11.020 ;
        RECT 34.340 10.740 34.620 11.020 ;
        RECT 34.740 10.740 35.020 11.020 ;
        RECT -4.660 5.300 -4.380 5.580 ;
        RECT -4.260 5.300 -3.980 5.580 ;
        RECT -3.860 5.300 -3.580 5.580 ;
        RECT -3.460 5.300 -3.180 5.580 ;
        RECT -3.060 5.300 -2.780 5.580 ;
        RECT -2.660 5.300 -2.380 5.580 ;
        RECT -2.260 5.300 -1.980 5.580 ;
        RECT -1.860 5.300 -1.580 5.580 ;
        RECT -1.460 5.300 -1.180 5.580 ;
        RECT -1.060 5.300 -0.780 5.580 ;
        RECT 31.140 5.300 31.420 5.580 ;
        RECT 31.540 5.300 31.820 5.580 ;
        RECT 31.940 5.300 32.220 5.580 ;
        RECT 32.340 5.300 32.620 5.580 ;
        RECT 32.740 5.300 33.020 5.580 ;
        RECT 33.140 5.300 33.420 5.580 ;
        RECT 33.540 5.300 33.820 5.580 ;
        RECT 33.940 5.300 34.220 5.580 ;
        RECT 34.340 5.300 34.620 5.580 ;
        RECT 34.740 5.300 35.020 5.580 ;
      LAYER met3 ;
        RECT -4.820 37.915 -0.620 38.245 ;
        RECT 30.980 37.915 35.180 38.245 ;
        RECT -4.820 32.475 -0.620 32.805 ;
        RECT 30.980 32.475 35.180 32.805 ;
        RECT -4.820 27.035 -0.620 27.365 ;
        RECT 30.980 27.035 35.180 27.365 ;
        RECT -4.820 21.595 -0.620 21.925 ;
        RECT 30.980 21.595 35.180 21.925 ;
        RECT -4.820 16.155 -0.620 16.485 ;
        RECT 30.980 16.155 35.180 16.485 ;
        RECT -4.820 10.715 -0.620 11.045 ;
        RECT 30.980 10.715 35.180 11.045 ;
        RECT -4.820 5.275 -0.620 5.605 ;
        RECT 30.980 5.275 35.180 5.605 ;
      LAYER via3 ;
        RECT -4.680 37.920 -4.360 38.240 ;
        RECT -4.280 37.920 -3.960 38.240 ;
        RECT -3.880 37.920 -3.560 38.240 ;
        RECT -3.480 37.920 -3.160 38.240 ;
        RECT -3.080 37.920 -2.760 38.240 ;
        RECT -2.680 37.920 -2.360 38.240 ;
        RECT -2.280 37.920 -1.960 38.240 ;
        RECT -1.880 37.920 -1.560 38.240 ;
        RECT -1.480 37.920 -1.160 38.240 ;
        RECT -1.080 37.920 -0.760 38.240 ;
        RECT 31.120 37.920 31.440 38.240 ;
        RECT 31.520 37.920 31.840 38.240 ;
        RECT 31.920 37.920 32.240 38.240 ;
        RECT 32.320 37.920 32.640 38.240 ;
        RECT 32.720 37.920 33.040 38.240 ;
        RECT 33.120 37.920 33.440 38.240 ;
        RECT 33.520 37.920 33.840 38.240 ;
        RECT 33.920 37.920 34.240 38.240 ;
        RECT 34.320 37.920 34.640 38.240 ;
        RECT 34.720 37.920 35.040 38.240 ;
        RECT -4.680 32.480 -4.360 32.800 ;
        RECT -4.280 32.480 -3.960 32.800 ;
        RECT -3.880 32.480 -3.560 32.800 ;
        RECT -3.480 32.480 -3.160 32.800 ;
        RECT -3.080 32.480 -2.760 32.800 ;
        RECT -2.680 32.480 -2.360 32.800 ;
        RECT -2.280 32.480 -1.960 32.800 ;
        RECT -1.880 32.480 -1.560 32.800 ;
        RECT -1.480 32.480 -1.160 32.800 ;
        RECT -1.080 32.480 -0.760 32.800 ;
        RECT 31.120 32.480 31.440 32.800 ;
        RECT 31.520 32.480 31.840 32.800 ;
        RECT 31.920 32.480 32.240 32.800 ;
        RECT 32.320 32.480 32.640 32.800 ;
        RECT 32.720 32.480 33.040 32.800 ;
        RECT 33.120 32.480 33.440 32.800 ;
        RECT 33.520 32.480 33.840 32.800 ;
        RECT 33.920 32.480 34.240 32.800 ;
        RECT 34.320 32.480 34.640 32.800 ;
        RECT 34.720 32.480 35.040 32.800 ;
        RECT -4.680 27.040 -4.360 27.360 ;
        RECT -4.280 27.040 -3.960 27.360 ;
        RECT -3.880 27.040 -3.560 27.360 ;
        RECT -3.480 27.040 -3.160 27.360 ;
        RECT -3.080 27.040 -2.760 27.360 ;
        RECT -2.680 27.040 -2.360 27.360 ;
        RECT -2.280 27.040 -1.960 27.360 ;
        RECT -1.880 27.040 -1.560 27.360 ;
        RECT -1.480 27.040 -1.160 27.360 ;
        RECT -1.080 27.040 -0.760 27.360 ;
        RECT 31.120 27.040 31.440 27.360 ;
        RECT 31.520 27.040 31.840 27.360 ;
        RECT 31.920 27.040 32.240 27.360 ;
        RECT 32.320 27.040 32.640 27.360 ;
        RECT 32.720 27.040 33.040 27.360 ;
        RECT 33.120 27.040 33.440 27.360 ;
        RECT 33.520 27.040 33.840 27.360 ;
        RECT 33.920 27.040 34.240 27.360 ;
        RECT 34.320 27.040 34.640 27.360 ;
        RECT 34.720 27.040 35.040 27.360 ;
        RECT -4.680 21.600 -4.360 21.920 ;
        RECT -4.280 21.600 -3.960 21.920 ;
        RECT -3.880 21.600 -3.560 21.920 ;
        RECT -3.480 21.600 -3.160 21.920 ;
        RECT -3.080 21.600 -2.760 21.920 ;
        RECT -2.680 21.600 -2.360 21.920 ;
        RECT -2.280 21.600 -1.960 21.920 ;
        RECT -1.880 21.600 -1.560 21.920 ;
        RECT -1.480 21.600 -1.160 21.920 ;
        RECT -1.080 21.600 -0.760 21.920 ;
        RECT 31.120 21.600 31.440 21.920 ;
        RECT 31.520 21.600 31.840 21.920 ;
        RECT 31.920 21.600 32.240 21.920 ;
        RECT 32.320 21.600 32.640 21.920 ;
        RECT 32.720 21.600 33.040 21.920 ;
        RECT 33.120 21.600 33.440 21.920 ;
        RECT 33.520 21.600 33.840 21.920 ;
        RECT 33.920 21.600 34.240 21.920 ;
        RECT 34.320 21.600 34.640 21.920 ;
        RECT 34.720 21.600 35.040 21.920 ;
        RECT -4.680 16.160 -4.360 16.480 ;
        RECT -4.280 16.160 -3.960 16.480 ;
        RECT -3.880 16.160 -3.560 16.480 ;
        RECT -3.480 16.160 -3.160 16.480 ;
        RECT -3.080 16.160 -2.760 16.480 ;
        RECT -2.680 16.160 -2.360 16.480 ;
        RECT -2.280 16.160 -1.960 16.480 ;
        RECT -1.880 16.160 -1.560 16.480 ;
        RECT -1.480 16.160 -1.160 16.480 ;
        RECT -1.080 16.160 -0.760 16.480 ;
        RECT 31.120 16.160 31.440 16.480 ;
        RECT 31.520 16.160 31.840 16.480 ;
        RECT 31.920 16.160 32.240 16.480 ;
        RECT 32.320 16.160 32.640 16.480 ;
        RECT 32.720 16.160 33.040 16.480 ;
        RECT 33.120 16.160 33.440 16.480 ;
        RECT 33.520 16.160 33.840 16.480 ;
        RECT 33.920 16.160 34.240 16.480 ;
        RECT 34.320 16.160 34.640 16.480 ;
        RECT 34.720 16.160 35.040 16.480 ;
        RECT -4.680 10.720 -4.360 11.040 ;
        RECT -4.280 10.720 -3.960 11.040 ;
        RECT -3.880 10.720 -3.560 11.040 ;
        RECT -3.480 10.720 -3.160 11.040 ;
        RECT -3.080 10.720 -2.760 11.040 ;
        RECT -2.680 10.720 -2.360 11.040 ;
        RECT -2.280 10.720 -1.960 11.040 ;
        RECT -1.880 10.720 -1.560 11.040 ;
        RECT -1.480 10.720 -1.160 11.040 ;
        RECT -1.080 10.720 -0.760 11.040 ;
        RECT 31.120 10.720 31.440 11.040 ;
        RECT 31.520 10.720 31.840 11.040 ;
        RECT 31.920 10.720 32.240 11.040 ;
        RECT 32.320 10.720 32.640 11.040 ;
        RECT 32.720 10.720 33.040 11.040 ;
        RECT 33.120 10.720 33.440 11.040 ;
        RECT 33.520 10.720 33.840 11.040 ;
        RECT 33.920 10.720 34.240 11.040 ;
        RECT 34.320 10.720 34.640 11.040 ;
        RECT 34.720 10.720 35.040 11.040 ;
        RECT -4.680 5.280 -4.360 5.600 ;
        RECT -4.280 5.280 -3.960 5.600 ;
        RECT -3.880 5.280 -3.560 5.600 ;
        RECT -3.480 5.280 -3.160 5.600 ;
        RECT -3.080 5.280 -2.760 5.600 ;
        RECT -2.680 5.280 -2.360 5.600 ;
        RECT -2.280 5.280 -1.960 5.600 ;
        RECT -1.880 5.280 -1.560 5.600 ;
        RECT -1.480 5.280 -1.160 5.600 ;
        RECT -1.080 5.280 -0.760 5.600 ;
        RECT 31.120 5.280 31.440 5.600 ;
        RECT 31.520 5.280 31.840 5.600 ;
        RECT 31.920 5.280 32.240 5.600 ;
        RECT 32.320 5.280 32.640 5.600 ;
        RECT 32.720 5.280 33.040 5.600 ;
        RECT 33.120 5.280 33.440 5.600 ;
        RECT 33.520 5.280 33.840 5.600 ;
        RECT 33.920 5.280 34.240 5.600 ;
        RECT 34.320 5.280 34.640 5.600 ;
        RECT 34.720 5.280 35.040 5.600 ;
      LAYER met4 ;
        RECT -4.820 -3.480 -0.620 44.280 ;
        RECT 30.980 -3.480 35.180 44.280 ;
      LAYER via4 ;
        RECT -4.110 40.790 -1.330 43.570 ;
        RECT -4.110 29.090 -2.930 30.270 ;
        RECT -2.510 29.090 -1.330 30.270 ;
        RECT -4.110 -2.770 -1.330 0.010 ;
        RECT 31.690 40.790 34.470 43.570 ;
        RECT 31.690 29.090 32.870 30.270 ;
        RECT 33.290 29.090 34.470 30.270 ;
        RECT 31.690 -2.770 34.470 0.010 ;
      LAYER met5 ;
        RECT -4.820 40.080 35.180 44.280 ;
        RECT -10.620 28.880 40.980 30.480 ;
        RECT -4.820 -3.480 35.180 0.720 ;
    END
  END VPWR
  PIN VGND
    USE GROUND ;
    PORT
      LAYER pwell ;
        RECT 15.195 35.550 15.625 36.335 ;
        RECT 15.195 30.110 15.625 30.895 ;
        RECT 15.195 24.670 15.625 25.455 ;
        RECT 15.195 19.230 15.625 20.015 ;
        RECT 15.195 13.790 15.625 14.575 ;
        RECT 15.195 8.350 15.625 9.135 ;
        RECT 15.195 2.910 15.625 3.695 ;
      LAYER li1 ;
        RECT 6.045 35.445 6.375 35.825 ;
        RECT 7.425 35.445 7.755 35.825 ;
        RECT 8.805 35.445 9.135 35.825 ;
        RECT 10.185 35.445 10.515 35.825 ;
        RECT 11.565 35.445 11.895 35.825 ;
        RECT 12.740 35.445 12.970 36.265 ;
        RECT 14.325 35.445 14.655 35.825 ;
        RECT 15.265 35.445 15.555 36.170 ;
        RECT 16.165 35.445 16.495 35.825 ;
        RECT 17.545 35.445 17.875 35.825 ;
        RECT 18.925 35.445 19.255 35.825 ;
        RECT 20.305 35.445 20.635 35.825 ;
        RECT 21.685 35.445 22.015 35.825 ;
        RECT 1.380 35.275 28.980 35.445 ;
        RECT 7.680 34.455 7.910 35.275 ;
        RECT 8.825 34.475 9.135 35.275 ;
        RECT 10.230 34.885 10.560 35.275 ;
        RECT 11.565 34.545 11.865 35.275 ;
        RECT 12.485 34.895 12.815 35.275 ;
        RECT 13.935 34.475 14.130 35.275 ;
        RECT 15.215 34.895 15.545 35.275 ;
        RECT 17.095 34.815 17.345 35.275 ;
        RECT 18.260 34.455 18.490 35.275 ;
        RECT 19.405 34.475 19.715 35.275 ;
        RECT 20.785 34.475 21.095 35.275 ;
        RECT 22.400 34.455 22.630 35.275 ;
        RECT 23.545 34.475 23.855 35.275 ;
        RECT 7.905 30.005 8.215 30.805 ;
        RECT 9.285 30.005 9.595 30.805 ;
        RECT 10.665 30.005 10.940 30.745 ;
        RECT 12.575 30.005 12.745 30.475 ;
        RECT 15.265 30.005 15.555 30.730 ;
        RECT 18.490 30.005 18.825 30.745 ;
        RECT 20.790 30.005 21.045 30.495 ;
        RECT 1.380 29.835 28.980 30.005 ;
        RECT 9.285 29.035 9.595 29.835 ;
        RECT 18.985 29.015 19.215 29.835 ;
        RECT 19.885 29.015 20.095 29.835 ;
        RECT 20.330 29.345 20.585 29.835 ;
        RECT 10.220 24.565 10.515 25.090 ;
        RECT 11.080 24.565 11.410 25.035 ;
        RECT 13.855 24.565 14.185 24.965 ;
        RECT 14.695 24.565 15.025 24.965 ;
        RECT 15.265 24.565 15.555 25.290 ;
        RECT 16.670 24.565 17.000 24.955 ;
        RECT 18.005 24.565 18.305 25.295 ;
        RECT 18.720 24.565 18.950 25.385 ;
        RECT 1.380 24.395 28.980 24.565 ;
        RECT 13.660 23.575 13.890 24.395 ;
        RECT 16.675 24.035 17.005 24.395 ;
        RECT 18.030 23.905 18.285 24.395 ;
        RECT 8.140 19.125 8.370 19.945 ;
        RECT 9.285 19.125 9.595 19.925 ;
        RECT 15.265 19.125 15.555 19.850 ;
        RECT 16.185 19.125 16.495 19.925 ;
        RECT 17.565 19.125 17.875 19.925 ;
        RECT 18.945 19.125 19.255 19.925 ;
        RECT 20.325 19.125 20.635 19.925 ;
        RECT 22.625 19.125 22.935 19.925 ;
        RECT 1.380 18.955 28.980 19.125 ;
        RECT 9.285 18.155 9.595 18.955 ;
        RECT 17.340 18.135 17.570 18.955 ;
        RECT 10.175 13.685 10.505 14.085 ;
        RECT 11.015 13.685 11.345 14.085 ;
        RECT 11.605 13.685 11.845 14.495 ;
        RECT 12.515 13.685 12.785 14.495 ;
        RECT 15.265 13.685 15.555 14.410 ;
        RECT 18.095 13.685 18.265 14.125 ;
        RECT 18.950 13.685 19.205 14.175 ;
        RECT 1.380 13.515 28.980 13.685 ;
        RECT 9.795 13.055 9.965 13.515 ;
        RECT 16.645 12.715 16.955 13.515 ;
        RECT 18.490 13.155 18.820 13.515 ;
        RECT 20.330 13.025 20.585 13.515 ;
        RECT 8.830 8.245 9.160 8.605 ;
        RECT 10.665 8.245 10.975 9.045 ;
        RECT 12.520 8.245 12.815 8.770 ;
        RECT 13.380 8.245 13.710 8.715 ;
        RECT 15.265 8.245 15.555 8.970 ;
        RECT 17.340 8.245 17.570 9.065 ;
        RECT 18.995 8.245 19.325 8.635 ;
        RECT 19.835 8.245 20.165 8.635 ;
        RECT 21.705 8.245 21.995 9.080 ;
        RECT 22.165 8.245 22.475 9.045 ;
        RECT 1.380 8.075 28.980 8.245 ;
        RECT 7.905 7.275 8.215 8.075 ;
        RECT 12.280 7.255 12.510 8.075 ;
        RECT 13.425 7.275 13.735 8.075 ;
        RECT 15.265 7.275 15.575 8.075 ;
        RECT 17.085 7.695 17.415 8.075 ;
        RECT 18.260 7.255 18.490 8.075 ;
        RECT 19.870 7.715 20.200 8.075 ;
        RECT 21.250 7.585 21.505 8.075 ;
        RECT 23.085 7.275 23.395 8.075 ;
        RECT 15.265 2.805 15.555 3.530 ;
        RECT 16.165 2.805 16.495 3.185 ;
        RECT 17.575 2.805 17.850 3.285 ;
        RECT 18.435 2.805 18.770 3.205 ;
        RECT 19.415 2.805 19.690 3.285 ;
        RECT 20.275 2.805 20.610 3.205 ;
        RECT 21.255 2.805 21.530 3.285 ;
        RECT 22.115 2.805 22.450 3.205 ;
        RECT 25.070 2.805 25.455 3.205 ;
        RECT 26.665 2.805 27.050 3.205 ;
        RECT 28.080 2.805 28.465 3.205 ;
        RECT 1.380 2.635 28.980 2.805 ;
      LAYER mcon ;
        RECT 1.525 35.275 1.695 35.445 ;
        RECT 1.985 35.275 2.155 35.445 ;
        RECT 2.445 35.275 2.615 35.445 ;
        RECT 2.905 35.275 3.075 35.445 ;
        RECT 3.365 35.275 3.535 35.445 ;
        RECT 3.825 35.275 3.995 35.445 ;
        RECT 4.285 35.275 4.455 35.445 ;
        RECT 4.745 35.275 4.915 35.445 ;
        RECT 5.205 35.275 5.375 35.445 ;
        RECT 5.665 35.275 5.835 35.445 ;
        RECT 6.125 35.275 6.295 35.445 ;
        RECT 6.585 35.275 6.755 35.445 ;
        RECT 7.045 35.275 7.215 35.445 ;
        RECT 7.505 35.275 7.675 35.445 ;
        RECT 7.965 35.275 8.135 35.445 ;
        RECT 8.425 35.275 8.595 35.445 ;
        RECT 8.885 35.275 9.055 35.445 ;
        RECT 9.345 35.275 9.515 35.445 ;
        RECT 9.805 35.275 9.975 35.445 ;
        RECT 10.265 35.275 10.435 35.445 ;
        RECT 10.725 35.275 10.895 35.445 ;
        RECT 11.185 35.275 11.355 35.445 ;
        RECT 11.645 35.275 11.815 35.445 ;
        RECT 12.105 35.275 12.275 35.445 ;
        RECT 12.565 35.275 12.735 35.445 ;
        RECT 13.025 35.275 13.195 35.445 ;
        RECT 13.485 35.275 13.655 35.445 ;
        RECT 13.945 35.275 14.115 35.445 ;
        RECT 14.405 35.275 14.575 35.445 ;
        RECT 14.865 35.275 15.035 35.445 ;
        RECT 15.325 35.275 15.495 35.445 ;
        RECT 15.785 35.275 15.955 35.445 ;
        RECT 16.245 35.275 16.415 35.445 ;
        RECT 16.705 35.275 16.875 35.445 ;
        RECT 17.165 35.275 17.335 35.445 ;
        RECT 17.625 35.275 17.795 35.445 ;
        RECT 18.085 35.275 18.255 35.445 ;
        RECT 18.545 35.275 18.715 35.445 ;
        RECT 19.005 35.275 19.175 35.445 ;
        RECT 19.465 35.275 19.635 35.445 ;
        RECT 19.925 35.275 20.095 35.445 ;
        RECT 20.385 35.275 20.555 35.445 ;
        RECT 20.845 35.275 21.015 35.445 ;
        RECT 21.305 35.275 21.475 35.445 ;
        RECT 21.765 35.275 21.935 35.445 ;
        RECT 22.225 35.275 22.395 35.445 ;
        RECT 22.685 35.275 22.855 35.445 ;
        RECT 23.145 35.275 23.315 35.445 ;
        RECT 23.605 35.275 23.775 35.445 ;
        RECT 24.065 35.275 24.235 35.445 ;
        RECT 24.525 35.275 24.695 35.445 ;
        RECT 24.985 35.275 25.155 35.445 ;
        RECT 25.445 35.275 25.615 35.445 ;
        RECT 25.905 35.275 26.075 35.445 ;
        RECT 26.365 35.275 26.535 35.445 ;
        RECT 26.825 35.275 26.995 35.445 ;
        RECT 27.285 35.275 27.455 35.445 ;
        RECT 27.745 35.275 27.915 35.445 ;
        RECT 28.205 35.275 28.375 35.445 ;
        RECT 28.665 35.275 28.835 35.445 ;
        RECT 1.525 29.835 1.695 30.005 ;
        RECT 1.985 29.835 2.155 30.005 ;
        RECT 2.445 29.835 2.615 30.005 ;
        RECT 2.905 29.835 3.075 30.005 ;
        RECT 3.365 29.835 3.535 30.005 ;
        RECT 3.825 29.835 3.995 30.005 ;
        RECT 4.285 29.835 4.455 30.005 ;
        RECT 4.745 29.835 4.915 30.005 ;
        RECT 5.205 29.835 5.375 30.005 ;
        RECT 5.665 29.835 5.835 30.005 ;
        RECT 6.125 29.835 6.295 30.005 ;
        RECT 6.585 29.835 6.755 30.005 ;
        RECT 7.045 29.835 7.215 30.005 ;
        RECT 7.505 29.835 7.675 30.005 ;
        RECT 7.965 29.835 8.135 30.005 ;
        RECT 8.425 29.835 8.595 30.005 ;
        RECT 8.885 29.835 9.055 30.005 ;
        RECT 9.345 29.835 9.515 30.005 ;
        RECT 9.805 29.835 9.975 30.005 ;
        RECT 10.265 29.835 10.435 30.005 ;
        RECT 10.725 29.835 10.895 30.005 ;
        RECT 11.185 29.835 11.355 30.005 ;
        RECT 11.645 29.835 11.815 30.005 ;
        RECT 12.105 29.835 12.275 30.005 ;
        RECT 12.565 29.835 12.735 30.005 ;
        RECT 13.025 29.835 13.195 30.005 ;
        RECT 13.485 29.835 13.655 30.005 ;
        RECT 13.945 29.835 14.115 30.005 ;
        RECT 14.405 29.835 14.575 30.005 ;
        RECT 14.865 29.835 15.035 30.005 ;
        RECT 15.325 29.835 15.495 30.005 ;
        RECT 15.785 29.835 15.955 30.005 ;
        RECT 16.245 29.835 16.415 30.005 ;
        RECT 16.705 29.835 16.875 30.005 ;
        RECT 17.165 29.835 17.335 30.005 ;
        RECT 17.625 29.835 17.795 30.005 ;
        RECT 18.085 29.835 18.255 30.005 ;
        RECT 18.545 29.835 18.715 30.005 ;
        RECT 19.005 29.835 19.175 30.005 ;
        RECT 19.465 29.835 19.635 30.005 ;
        RECT 19.925 29.835 20.095 30.005 ;
        RECT 20.385 29.835 20.555 30.005 ;
        RECT 20.845 29.835 21.015 30.005 ;
        RECT 21.305 29.835 21.475 30.005 ;
        RECT 21.765 29.835 21.935 30.005 ;
        RECT 22.225 29.835 22.395 30.005 ;
        RECT 22.685 29.835 22.855 30.005 ;
        RECT 23.145 29.835 23.315 30.005 ;
        RECT 23.605 29.835 23.775 30.005 ;
        RECT 24.065 29.835 24.235 30.005 ;
        RECT 24.525 29.835 24.695 30.005 ;
        RECT 24.985 29.835 25.155 30.005 ;
        RECT 25.445 29.835 25.615 30.005 ;
        RECT 25.905 29.835 26.075 30.005 ;
        RECT 26.365 29.835 26.535 30.005 ;
        RECT 26.825 29.835 26.995 30.005 ;
        RECT 27.285 29.835 27.455 30.005 ;
        RECT 27.745 29.835 27.915 30.005 ;
        RECT 28.205 29.835 28.375 30.005 ;
        RECT 28.665 29.835 28.835 30.005 ;
        RECT 1.525 24.395 1.695 24.565 ;
        RECT 1.985 24.395 2.155 24.565 ;
        RECT 2.445 24.395 2.615 24.565 ;
        RECT 2.905 24.395 3.075 24.565 ;
        RECT 3.365 24.395 3.535 24.565 ;
        RECT 3.825 24.395 3.995 24.565 ;
        RECT 4.285 24.395 4.455 24.565 ;
        RECT 4.745 24.395 4.915 24.565 ;
        RECT 5.205 24.395 5.375 24.565 ;
        RECT 5.665 24.395 5.835 24.565 ;
        RECT 6.125 24.395 6.295 24.565 ;
        RECT 6.585 24.395 6.755 24.565 ;
        RECT 7.045 24.395 7.215 24.565 ;
        RECT 7.505 24.395 7.675 24.565 ;
        RECT 7.965 24.395 8.135 24.565 ;
        RECT 8.425 24.395 8.595 24.565 ;
        RECT 8.885 24.395 9.055 24.565 ;
        RECT 9.345 24.395 9.515 24.565 ;
        RECT 9.805 24.395 9.975 24.565 ;
        RECT 10.265 24.395 10.435 24.565 ;
        RECT 10.725 24.395 10.895 24.565 ;
        RECT 11.185 24.395 11.355 24.565 ;
        RECT 11.645 24.395 11.815 24.565 ;
        RECT 12.105 24.395 12.275 24.565 ;
        RECT 12.565 24.395 12.735 24.565 ;
        RECT 13.025 24.395 13.195 24.565 ;
        RECT 13.485 24.395 13.655 24.565 ;
        RECT 13.945 24.395 14.115 24.565 ;
        RECT 14.405 24.395 14.575 24.565 ;
        RECT 14.865 24.395 15.035 24.565 ;
        RECT 15.325 24.395 15.495 24.565 ;
        RECT 15.785 24.395 15.955 24.565 ;
        RECT 16.245 24.395 16.415 24.565 ;
        RECT 16.705 24.395 16.875 24.565 ;
        RECT 17.165 24.395 17.335 24.565 ;
        RECT 17.625 24.395 17.795 24.565 ;
        RECT 18.085 24.395 18.255 24.565 ;
        RECT 18.545 24.395 18.715 24.565 ;
        RECT 19.005 24.395 19.175 24.565 ;
        RECT 19.465 24.395 19.635 24.565 ;
        RECT 19.925 24.395 20.095 24.565 ;
        RECT 20.385 24.395 20.555 24.565 ;
        RECT 20.845 24.395 21.015 24.565 ;
        RECT 21.305 24.395 21.475 24.565 ;
        RECT 21.765 24.395 21.935 24.565 ;
        RECT 22.225 24.395 22.395 24.565 ;
        RECT 22.685 24.395 22.855 24.565 ;
        RECT 23.145 24.395 23.315 24.565 ;
        RECT 23.605 24.395 23.775 24.565 ;
        RECT 24.065 24.395 24.235 24.565 ;
        RECT 24.525 24.395 24.695 24.565 ;
        RECT 24.985 24.395 25.155 24.565 ;
        RECT 25.445 24.395 25.615 24.565 ;
        RECT 25.905 24.395 26.075 24.565 ;
        RECT 26.365 24.395 26.535 24.565 ;
        RECT 26.825 24.395 26.995 24.565 ;
        RECT 27.285 24.395 27.455 24.565 ;
        RECT 27.745 24.395 27.915 24.565 ;
        RECT 28.205 24.395 28.375 24.565 ;
        RECT 28.665 24.395 28.835 24.565 ;
        RECT 1.525 18.955 1.695 19.125 ;
        RECT 1.985 18.955 2.155 19.125 ;
        RECT 2.445 18.955 2.615 19.125 ;
        RECT 2.905 18.955 3.075 19.125 ;
        RECT 3.365 18.955 3.535 19.125 ;
        RECT 3.825 18.955 3.995 19.125 ;
        RECT 4.285 18.955 4.455 19.125 ;
        RECT 4.745 18.955 4.915 19.125 ;
        RECT 5.205 18.955 5.375 19.125 ;
        RECT 5.665 18.955 5.835 19.125 ;
        RECT 6.125 18.955 6.295 19.125 ;
        RECT 6.585 18.955 6.755 19.125 ;
        RECT 7.045 18.955 7.215 19.125 ;
        RECT 7.505 18.955 7.675 19.125 ;
        RECT 7.965 18.955 8.135 19.125 ;
        RECT 8.425 18.955 8.595 19.125 ;
        RECT 8.885 18.955 9.055 19.125 ;
        RECT 9.345 18.955 9.515 19.125 ;
        RECT 9.805 18.955 9.975 19.125 ;
        RECT 10.265 18.955 10.435 19.125 ;
        RECT 10.725 18.955 10.895 19.125 ;
        RECT 11.185 18.955 11.355 19.125 ;
        RECT 11.645 18.955 11.815 19.125 ;
        RECT 12.105 18.955 12.275 19.125 ;
        RECT 12.565 18.955 12.735 19.125 ;
        RECT 13.025 18.955 13.195 19.125 ;
        RECT 13.485 18.955 13.655 19.125 ;
        RECT 13.945 18.955 14.115 19.125 ;
        RECT 14.405 18.955 14.575 19.125 ;
        RECT 14.865 18.955 15.035 19.125 ;
        RECT 15.325 18.955 15.495 19.125 ;
        RECT 15.785 18.955 15.955 19.125 ;
        RECT 16.245 18.955 16.415 19.125 ;
        RECT 16.705 18.955 16.875 19.125 ;
        RECT 17.165 18.955 17.335 19.125 ;
        RECT 17.625 18.955 17.795 19.125 ;
        RECT 18.085 18.955 18.255 19.125 ;
        RECT 18.545 18.955 18.715 19.125 ;
        RECT 19.005 18.955 19.175 19.125 ;
        RECT 19.465 18.955 19.635 19.125 ;
        RECT 19.925 18.955 20.095 19.125 ;
        RECT 20.385 18.955 20.555 19.125 ;
        RECT 20.845 18.955 21.015 19.125 ;
        RECT 21.305 18.955 21.475 19.125 ;
        RECT 21.765 18.955 21.935 19.125 ;
        RECT 22.225 18.955 22.395 19.125 ;
        RECT 22.685 18.955 22.855 19.125 ;
        RECT 23.145 18.955 23.315 19.125 ;
        RECT 23.605 18.955 23.775 19.125 ;
        RECT 24.065 18.955 24.235 19.125 ;
        RECT 24.525 18.955 24.695 19.125 ;
        RECT 24.985 18.955 25.155 19.125 ;
        RECT 25.445 18.955 25.615 19.125 ;
        RECT 25.905 18.955 26.075 19.125 ;
        RECT 26.365 18.955 26.535 19.125 ;
        RECT 26.825 18.955 26.995 19.125 ;
        RECT 27.285 18.955 27.455 19.125 ;
        RECT 27.745 18.955 27.915 19.125 ;
        RECT 28.205 18.955 28.375 19.125 ;
        RECT 28.665 18.955 28.835 19.125 ;
        RECT 1.525 13.515 1.695 13.685 ;
        RECT 1.985 13.515 2.155 13.685 ;
        RECT 2.445 13.515 2.615 13.685 ;
        RECT 2.905 13.515 3.075 13.685 ;
        RECT 3.365 13.515 3.535 13.685 ;
        RECT 3.825 13.515 3.995 13.685 ;
        RECT 4.285 13.515 4.455 13.685 ;
        RECT 4.745 13.515 4.915 13.685 ;
        RECT 5.205 13.515 5.375 13.685 ;
        RECT 5.665 13.515 5.835 13.685 ;
        RECT 6.125 13.515 6.295 13.685 ;
        RECT 6.585 13.515 6.755 13.685 ;
        RECT 7.045 13.515 7.215 13.685 ;
        RECT 7.505 13.515 7.675 13.685 ;
        RECT 7.965 13.515 8.135 13.685 ;
        RECT 8.425 13.515 8.595 13.685 ;
        RECT 8.885 13.515 9.055 13.685 ;
        RECT 9.345 13.515 9.515 13.685 ;
        RECT 9.805 13.515 9.975 13.685 ;
        RECT 10.265 13.515 10.435 13.685 ;
        RECT 10.725 13.515 10.895 13.685 ;
        RECT 11.185 13.515 11.355 13.685 ;
        RECT 11.645 13.515 11.815 13.685 ;
        RECT 12.105 13.515 12.275 13.685 ;
        RECT 12.565 13.515 12.735 13.685 ;
        RECT 13.025 13.515 13.195 13.685 ;
        RECT 13.485 13.515 13.655 13.685 ;
        RECT 13.945 13.515 14.115 13.685 ;
        RECT 14.405 13.515 14.575 13.685 ;
        RECT 14.865 13.515 15.035 13.685 ;
        RECT 15.325 13.515 15.495 13.685 ;
        RECT 15.785 13.515 15.955 13.685 ;
        RECT 16.245 13.515 16.415 13.685 ;
        RECT 16.705 13.515 16.875 13.685 ;
        RECT 17.165 13.515 17.335 13.685 ;
        RECT 17.625 13.515 17.795 13.685 ;
        RECT 18.085 13.515 18.255 13.685 ;
        RECT 18.545 13.515 18.715 13.685 ;
        RECT 19.005 13.515 19.175 13.685 ;
        RECT 19.465 13.515 19.635 13.685 ;
        RECT 19.925 13.515 20.095 13.685 ;
        RECT 20.385 13.515 20.555 13.685 ;
        RECT 20.845 13.515 21.015 13.685 ;
        RECT 21.305 13.515 21.475 13.685 ;
        RECT 21.765 13.515 21.935 13.685 ;
        RECT 22.225 13.515 22.395 13.685 ;
        RECT 22.685 13.515 22.855 13.685 ;
        RECT 23.145 13.515 23.315 13.685 ;
        RECT 23.605 13.515 23.775 13.685 ;
        RECT 24.065 13.515 24.235 13.685 ;
        RECT 24.525 13.515 24.695 13.685 ;
        RECT 24.985 13.515 25.155 13.685 ;
        RECT 25.445 13.515 25.615 13.685 ;
        RECT 25.905 13.515 26.075 13.685 ;
        RECT 26.365 13.515 26.535 13.685 ;
        RECT 26.825 13.515 26.995 13.685 ;
        RECT 27.285 13.515 27.455 13.685 ;
        RECT 27.745 13.515 27.915 13.685 ;
        RECT 28.205 13.515 28.375 13.685 ;
        RECT 28.665 13.515 28.835 13.685 ;
        RECT 1.525 8.075 1.695 8.245 ;
        RECT 1.985 8.075 2.155 8.245 ;
        RECT 2.445 8.075 2.615 8.245 ;
        RECT 2.905 8.075 3.075 8.245 ;
        RECT 3.365 8.075 3.535 8.245 ;
        RECT 3.825 8.075 3.995 8.245 ;
        RECT 4.285 8.075 4.455 8.245 ;
        RECT 4.745 8.075 4.915 8.245 ;
        RECT 5.205 8.075 5.375 8.245 ;
        RECT 5.665 8.075 5.835 8.245 ;
        RECT 6.125 8.075 6.295 8.245 ;
        RECT 6.585 8.075 6.755 8.245 ;
        RECT 7.045 8.075 7.215 8.245 ;
        RECT 7.505 8.075 7.675 8.245 ;
        RECT 7.965 8.075 8.135 8.245 ;
        RECT 8.425 8.075 8.595 8.245 ;
        RECT 8.885 8.075 9.055 8.245 ;
        RECT 9.345 8.075 9.515 8.245 ;
        RECT 9.805 8.075 9.975 8.245 ;
        RECT 10.265 8.075 10.435 8.245 ;
        RECT 10.725 8.075 10.895 8.245 ;
        RECT 11.185 8.075 11.355 8.245 ;
        RECT 11.645 8.075 11.815 8.245 ;
        RECT 12.105 8.075 12.275 8.245 ;
        RECT 12.565 8.075 12.735 8.245 ;
        RECT 13.025 8.075 13.195 8.245 ;
        RECT 13.485 8.075 13.655 8.245 ;
        RECT 13.945 8.075 14.115 8.245 ;
        RECT 14.405 8.075 14.575 8.245 ;
        RECT 14.865 8.075 15.035 8.245 ;
        RECT 15.325 8.075 15.495 8.245 ;
        RECT 15.785 8.075 15.955 8.245 ;
        RECT 16.245 8.075 16.415 8.245 ;
        RECT 16.705 8.075 16.875 8.245 ;
        RECT 17.165 8.075 17.335 8.245 ;
        RECT 17.625 8.075 17.795 8.245 ;
        RECT 18.085 8.075 18.255 8.245 ;
        RECT 18.545 8.075 18.715 8.245 ;
        RECT 19.005 8.075 19.175 8.245 ;
        RECT 19.465 8.075 19.635 8.245 ;
        RECT 19.925 8.075 20.095 8.245 ;
        RECT 20.385 8.075 20.555 8.245 ;
        RECT 20.845 8.075 21.015 8.245 ;
        RECT 21.305 8.075 21.475 8.245 ;
        RECT 21.765 8.075 21.935 8.245 ;
        RECT 22.225 8.075 22.395 8.245 ;
        RECT 22.685 8.075 22.855 8.245 ;
        RECT 23.145 8.075 23.315 8.245 ;
        RECT 23.605 8.075 23.775 8.245 ;
        RECT 24.065 8.075 24.235 8.245 ;
        RECT 24.525 8.075 24.695 8.245 ;
        RECT 24.985 8.075 25.155 8.245 ;
        RECT 25.445 8.075 25.615 8.245 ;
        RECT 25.905 8.075 26.075 8.245 ;
        RECT 26.365 8.075 26.535 8.245 ;
        RECT 26.825 8.075 26.995 8.245 ;
        RECT 27.285 8.075 27.455 8.245 ;
        RECT 27.745 8.075 27.915 8.245 ;
        RECT 28.205 8.075 28.375 8.245 ;
        RECT 28.665 8.075 28.835 8.245 ;
        RECT 1.525 2.635 1.695 2.805 ;
        RECT 1.985 2.635 2.155 2.805 ;
        RECT 2.445 2.635 2.615 2.805 ;
        RECT 2.905 2.635 3.075 2.805 ;
        RECT 3.365 2.635 3.535 2.805 ;
        RECT 3.825 2.635 3.995 2.805 ;
        RECT 4.285 2.635 4.455 2.805 ;
        RECT 4.745 2.635 4.915 2.805 ;
        RECT 5.205 2.635 5.375 2.805 ;
        RECT 5.665 2.635 5.835 2.805 ;
        RECT 6.125 2.635 6.295 2.805 ;
        RECT 6.585 2.635 6.755 2.805 ;
        RECT 7.045 2.635 7.215 2.805 ;
        RECT 7.505 2.635 7.675 2.805 ;
        RECT 7.965 2.635 8.135 2.805 ;
        RECT 8.425 2.635 8.595 2.805 ;
        RECT 8.885 2.635 9.055 2.805 ;
        RECT 9.345 2.635 9.515 2.805 ;
        RECT 9.805 2.635 9.975 2.805 ;
        RECT 10.265 2.635 10.435 2.805 ;
        RECT 10.725 2.635 10.895 2.805 ;
        RECT 11.185 2.635 11.355 2.805 ;
        RECT 11.645 2.635 11.815 2.805 ;
        RECT 12.105 2.635 12.275 2.805 ;
        RECT 12.565 2.635 12.735 2.805 ;
        RECT 13.025 2.635 13.195 2.805 ;
        RECT 13.485 2.635 13.655 2.805 ;
        RECT 13.945 2.635 14.115 2.805 ;
        RECT 14.405 2.635 14.575 2.805 ;
        RECT 14.865 2.635 15.035 2.805 ;
        RECT 15.325 2.635 15.495 2.805 ;
        RECT 15.785 2.635 15.955 2.805 ;
        RECT 16.245 2.635 16.415 2.805 ;
        RECT 16.705 2.635 16.875 2.805 ;
        RECT 17.165 2.635 17.335 2.805 ;
        RECT 17.625 2.635 17.795 2.805 ;
        RECT 18.085 2.635 18.255 2.805 ;
        RECT 18.545 2.635 18.715 2.805 ;
        RECT 19.005 2.635 19.175 2.805 ;
        RECT 19.465 2.635 19.635 2.805 ;
        RECT 19.925 2.635 20.095 2.805 ;
        RECT 20.385 2.635 20.555 2.805 ;
        RECT 20.845 2.635 21.015 2.805 ;
        RECT 21.305 2.635 21.475 2.805 ;
        RECT 21.765 2.635 21.935 2.805 ;
        RECT 22.225 2.635 22.395 2.805 ;
        RECT 22.685 2.635 22.855 2.805 ;
        RECT 23.145 2.635 23.315 2.805 ;
        RECT 23.605 2.635 23.775 2.805 ;
        RECT 24.065 2.635 24.235 2.805 ;
        RECT 24.525 2.635 24.695 2.805 ;
        RECT 24.985 2.635 25.155 2.805 ;
        RECT 25.445 2.635 25.615 2.805 ;
        RECT 25.905 2.635 26.075 2.805 ;
        RECT 26.365 2.635 26.535 2.805 ;
        RECT 26.825 2.635 26.995 2.805 ;
        RECT 27.285 2.635 27.455 2.805 ;
        RECT 27.745 2.635 27.915 2.805 ;
        RECT 28.205 2.635 28.375 2.805 ;
        RECT 28.665 2.635 28.835 2.805 ;
      LAYER met1 ;
        RECT -10.620 35.120 40.980 35.600 ;
        RECT -10.620 29.680 40.980 30.160 ;
        RECT -10.620 24.240 40.980 24.720 ;
        RECT -10.620 18.800 40.980 19.280 ;
        RECT -10.620 13.360 40.980 13.840 ;
        RECT -10.620 7.920 40.980 8.400 ;
        RECT -10.620 2.480 40.980 2.960 ;
      LAYER via ;
        RECT -10.570 35.230 -10.310 35.490 ;
        RECT -10.250 35.230 -9.990 35.490 ;
        RECT -9.930 35.230 -9.670 35.490 ;
        RECT -9.610 35.230 -9.350 35.490 ;
        RECT -9.290 35.230 -9.030 35.490 ;
        RECT -8.970 35.230 -8.710 35.490 ;
        RECT -8.650 35.230 -8.390 35.490 ;
        RECT -8.330 35.230 -8.070 35.490 ;
        RECT -8.010 35.230 -7.750 35.490 ;
        RECT -7.690 35.230 -7.430 35.490 ;
        RECT -7.370 35.230 -7.110 35.490 ;
        RECT -7.050 35.230 -6.790 35.490 ;
        RECT -6.730 35.230 -6.470 35.490 ;
        RECT 14.180 35.230 14.440 35.490 ;
        RECT 14.500 35.230 14.760 35.490 ;
        RECT 14.820 35.230 15.080 35.490 ;
        RECT 15.140 35.230 15.400 35.490 ;
        RECT 15.460 35.230 15.720 35.490 ;
        RECT 36.830 35.230 37.090 35.490 ;
        RECT 37.150 35.230 37.410 35.490 ;
        RECT 37.470 35.230 37.730 35.490 ;
        RECT 37.790 35.230 38.050 35.490 ;
        RECT 38.110 35.230 38.370 35.490 ;
        RECT 38.430 35.230 38.690 35.490 ;
        RECT 38.750 35.230 39.010 35.490 ;
        RECT 39.070 35.230 39.330 35.490 ;
        RECT 39.390 35.230 39.650 35.490 ;
        RECT 39.710 35.230 39.970 35.490 ;
        RECT 40.030 35.230 40.290 35.490 ;
        RECT 40.350 35.230 40.610 35.490 ;
        RECT 40.670 35.230 40.930 35.490 ;
        RECT -10.570 29.790 -10.310 30.050 ;
        RECT -10.250 29.790 -9.990 30.050 ;
        RECT -9.930 29.790 -9.670 30.050 ;
        RECT -9.610 29.790 -9.350 30.050 ;
        RECT -9.290 29.790 -9.030 30.050 ;
        RECT -8.970 29.790 -8.710 30.050 ;
        RECT -8.650 29.790 -8.390 30.050 ;
        RECT -8.330 29.790 -8.070 30.050 ;
        RECT -8.010 29.790 -7.750 30.050 ;
        RECT -7.690 29.790 -7.430 30.050 ;
        RECT -7.370 29.790 -7.110 30.050 ;
        RECT -7.050 29.790 -6.790 30.050 ;
        RECT -6.730 29.790 -6.470 30.050 ;
        RECT 14.180 29.790 14.440 30.050 ;
        RECT 14.500 29.790 14.760 30.050 ;
        RECT 14.820 29.790 15.080 30.050 ;
        RECT 15.140 29.790 15.400 30.050 ;
        RECT 15.460 29.790 15.720 30.050 ;
        RECT 36.830 29.790 37.090 30.050 ;
        RECT 37.150 29.790 37.410 30.050 ;
        RECT 37.470 29.790 37.730 30.050 ;
        RECT 37.790 29.790 38.050 30.050 ;
        RECT 38.110 29.790 38.370 30.050 ;
        RECT 38.430 29.790 38.690 30.050 ;
        RECT 38.750 29.790 39.010 30.050 ;
        RECT 39.070 29.790 39.330 30.050 ;
        RECT 39.390 29.790 39.650 30.050 ;
        RECT 39.710 29.790 39.970 30.050 ;
        RECT 40.030 29.790 40.290 30.050 ;
        RECT 40.350 29.790 40.610 30.050 ;
        RECT 40.670 29.790 40.930 30.050 ;
        RECT -10.570 24.350 -10.310 24.610 ;
        RECT -10.250 24.350 -9.990 24.610 ;
        RECT -9.930 24.350 -9.670 24.610 ;
        RECT -9.610 24.350 -9.350 24.610 ;
        RECT -9.290 24.350 -9.030 24.610 ;
        RECT -8.970 24.350 -8.710 24.610 ;
        RECT -8.650 24.350 -8.390 24.610 ;
        RECT -8.330 24.350 -8.070 24.610 ;
        RECT -8.010 24.350 -7.750 24.610 ;
        RECT -7.690 24.350 -7.430 24.610 ;
        RECT -7.370 24.350 -7.110 24.610 ;
        RECT -7.050 24.350 -6.790 24.610 ;
        RECT -6.730 24.350 -6.470 24.610 ;
        RECT 14.180 24.350 14.440 24.610 ;
        RECT 14.500 24.350 14.760 24.610 ;
        RECT 14.820 24.350 15.080 24.610 ;
        RECT 15.140 24.350 15.400 24.610 ;
        RECT 15.460 24.350 15.720 24.610 ;
        RECT 36.830 24.350 37.090 24.610 ;
        RECT 37.150 24.350 37.410 24.610 ;
        RECT 37.470 24.350 37.730 24.610 ;
        RECT 37.790 24.350 38.050 24.610 ;
        RECT 38.110 24.350 38.370 24.610 ;
        RECT 38.430 24.350 38.690 24.610 ;
        RECT 38.750 24.350 39.010 24.610 ;
        RECT 39.070 24.350 39.330 24.610 ;
        RECT 39.390 24.350 39.650 24.610 ;
        RECT 39.710 24.350 39.970 24.610 ;
        RECT 40.030 24.350 40.290 24.610 ;
        RECT 40.350 24.350 40.610 24.610 ;
        RECT 40.670 24.350 40.930 24.610 ;
        RECT -10.570 18.910 -10.310 19.170 ;
        RECT -10.250 18.910 -9.990 19.170 ;
        RECT -9.930 18.910 -9.670 19.170 ;
        RECT -9.610 18.910 -9.350 19.170 ;
        RECT -9.290 18.910 -9.030 19.170 ;
        RECT -8.970 18.910 -8.710 19.170 ;
        RECT -8.650 18.910 -8.390 19.170 ;
        RECT -8.330 18.910 -8.070 19.170 ;
        RECT -8.010 18.910 -7.750 19.170 ;
        RECT -7.690 18.910 -7.430 19.170 ;
        RECT -7.370 18.910 -7.110 19.170 ;
        RECT -7.050 18.910 -6.790 19.170 ;
        RECT -6.730 18.910 -6.470 19.170 ;
        RECT 14.180 18.910 14.440 19.170 ;
        RECT 14.500 18.910 14.760 19.170 ;
        RECT 14.820 18.910 15.080 19.170 ;
        RECT 15.140 18.910 15.400 19.170 ;
        RECT 15.460 18.910 15.720 19.170 ;
        RECT 36.830 18.910 37.090 19.170 ;
        RECT 37.150 18.910 37.410 19.170 ;
        RECT 37.470 18.910 37.730 19.170 ;
        RECT 37.790 18.910 38.050 19.170 ;
        RECT 38.110 18.910 38.370 19.170 ;
        RECT 38.430 18.910 38.690 19.170 ;
        RECT 38.750 18.910 39.010 19.170 ;
        RECT 39.070 18.910 39.330 19.170 ;
        RECT 39.390 18.910 39.650 19.170 ;
        RECT 39.710 18.910 39.970 19.170 ;
        RECT 40.030 18.910 40.290 19.170 ;
        RECT 40.350 18.910 40.610 19.170 ;
        RECT 40.670 18.910 40.930 19.170 ;
        RECT -10.570 13.470 -10.310 13.730 ;
        RECT -10.250 13.470 -9.990 13.730 ;
        RECT -9.930 13.470 -9.670 13.730 ;
        RECT -9.610 13.470 -9.350 13.730 ;
        RECT -9.290 13.470 -9.030 13.730 ;
        RECT -8.970 13.470 -8.710 13.730 ;
        RECT -8.650 13.470 -8.390 13.730 ;
        RECT -8.330 13.470 -8.070 13.730 ;
        RECT -8.010 13.470 -7.750 13.730 ;
        RECT -7.690 13.470 -7.430 13.730 ;
        RECT -7.370 13.470 -7.110 13.730 ;
        RECT -7.050 13.470 -6.790 13.730 ;
        RECT -6.730 13.470 -6.470 13.730 ;
        RECT 14.180 13.470 14.440 13.730 ;
        RECT 14.500 13.470 14.760 13.730 ;
        RECT 14.820 13.470 15.080 13.730 ;
        RECT 15.140 13.470 15.400 13.730 ;
        RECT 15.460 13.470 15.720 13.730 ;
        RECT 36.830 13.470 37.090 13.730 ;
        RECT 37.150 13.470 37.410 13.730 ;
        RECT 37.470 13.470 37.730 13.730 ;
        RECT 37.790 13.470 38.050 13.730 ;
        RECT 38.110 13.470 38.370 13.730 ;
        RECT 38.430 13.470 38.690 13.730 ;
        RECT 38.750 13.470 39.010 13.730 ;
        RECT 39.070 13.470 39.330 13.730 ;
        RECT 39.390 13.470 39.650 13.730 ;
        RECT 39.710 13.470 39.970 13.730 ;
        RECT 40.030 13.470 40.290 13.730 ;
        RECT 40.350 13.470 40.610 13.730 ;
        RECT 40.670 13.470 40.930 13.730 ;
        RECT -10.570 8.030 -10.310 8.290 ;
        RECT -10.250 8.030 -9.990 8.290 ;
        RECT -9.930 8.030 -9.670 8.290 ;
        RECT -9.610 8.030 -9.350 8.290 ;
        RECT -9.290 8.030 -9.030 8.290 ;
        RECT -8.970 8.030 -8.710 8.290 ;
        RECT -8.650 8.030 -8.390 8.290 ;
        RECT -8.330 8.030 -8.070 8.290 ;
        RECT -8.010 8.030 -7.750 8.290 ;
        RECT -7.690 8.030 -7.430 8.290 ;
        RECT -7.370 8.030 -7.110 8.290 ;
        RECT -7.050 8.030 -6.790 8.290 ;
        RECT -6.730 8.030 -6.470 8.290 ;
        RECT 14.180 8.030 14.440 8.290 ;
        RECT 14.500 8.030 14.760 8.290 ;
        RECT 14.820 8.030 15.080 8.290 ;
        RECT 15.140 8.030 15.400 8.290 ;
        RECT 15.460 8.030 15.720 8.290 ;
        RECT 36.830 8.030 37.090 8.290 ;
        RECT 37.150 8.030 37.410 8.290 ;
        RECT 37.470 8.030 37.730 8.290 ;
        RECT 37.790 8.030 38.050 8.290 ;
        RECT 38.110 8.030 38.370 8.290 ;
        RECT 38.430 8.030 38.690 8.290 ;
        RECT 38.750 8.030 39.010 8.290 ;
        RECT 39.070 8.030 39.330 8.290 ;
        RECT 39.390 8.030 39.650 8.290 ;
        RECT 39.710 8.030 39.970 8.290 ;
        RECT 40.030 8.030 40.290 8.290 ;
        RECT 40.350 8.030 40.610 8.290 ;
        RECT 40.670 8.030 40.930 8.290 ;
        RECT -10.570 2.590 -10.310 2.850 ;
        RECT -10.250 2.590 -9.990 2.850 ;
        RECT -9.930 2.590 -9.670 2.850 ;
        RECT -9.610 2.590 -9.350 2.850 ;
        RECT -9.290 2.590 -9.030 2.850 ;
        RECT -8.970 2.590 -8.710 2.850 ;
        RECT -8.650 2.590 -8.390 2.850 ;
        RECT -8.330 2.590 -8.070 2.850 ;
        RECT -8.010 2.590 -7.750 2.850 ;
        RECT -7.690 2.590 -7.430 2.850 ;
        RECT -7.370 2.590 -7.110 2.850 ;
        RECT -7.050 2.590 -6.790 2.850 ;
        RECT -6.730 2.590 -6.470 2.850 ;
        RECT 14.180 2.590 14.440 2.850 ;
        RECT 14.500 2.590 14.760 2.850 ;
        RECT 14.820 2.590 15.080 2.850 ;
        RECT 15.140 2.590 15.400 2.850 ;
        RECT 15.460 2.590 15.720 2.850 ;
        RECT 36.830 2.590 37.090 2.850 ;
        RECT 37.150 2.590 37.410 2.850 ;
        RECT 37.470 2.590 37.730 2.850 ;
        RECT 37.790 2.590 38.050 2.850 ;
        RECT 38.110 2.590 38.370 2.850 ;
        RECT 38.430 2.590 38.690 2.850 ;
        RECT 38.750 2.590 39.010 2.850 ;
        RECT 39.070 2.590 39.330 2.850 ;
        RECT 39.390 2.590 39.650 2.850 ;
        RECT 39.710 2.590 39.970 2.850 ;
        RECT 40.030 2.590 40.290 2.850 ;
        RECT 40.350 2.590 40.610 2.850 ;
        RECT 40.670 2.590 40.930 2.850 ;
      LAYER met2 ;
        RECT -10.570 35.120 -6.470 35.600 ;
        RECT 14.180 35.120 15.720 35.600 ;
        RECT 36.830 35.120 40.930 35.600 ;
        RECT -10.570 29.680 -6.470 30.160 ;
        RECT 14.180 29.680 15.720 30.160 ;
        RECT 36.830 29.680 40.930 30.160 ;
        RECT -10.570 24.240 -6.470 24.720 ;
        RECT 14.180 24.240 15.720 24.720 ;
        RECT 36.830 24.240 40.930 24.720 ;
        RECT -10.570 18.800 -6.470 19.280 ;
        RECT 14.180 18.800 15.720 19.280 ;
        RECT 36.830 18.800 40.930 19.280 ;
        RECT -10.570 13.360 -6.470 13.840 ;
        RECT 14.180 13.360 15.720 13.840 ;
        RECT 36.830 13.360 40.930 13.840 ;
        RECT -10.570 7.920 -6.470 8.400 ;
        RECT 14.180 7.920 15.720 8.400 ;
        RECT 36.830 7.920 40.930 8.400 ;
        RECT -10.570 2.480 -6.470 2.960 ;
        RECT 14.180 2.480 15.720 2.960 ;
        RECT 36.830 2.480 40.930 2.960 ;
      LAYER via2 ;
        RECT -10.460 35.220 -10.180 35.500 ;
        RECT -10.060 35.220 -9.780 35.500 ;
        RECT -9.660 35.220 -9.380 35.500 ;
        RECT -9.260 35.220 -8.980 35.500 ;
        RECT -8.860 35.220 -8.580 35.500 ;
        RECT -8.460 35.220 -8.180 35.500 ;
        RECT -8.060 35.220 -7.780 35.500 ;
        RECT -7.660 35.220 -7.380 35.500 ;
        RECT -7.260 35.220 -6.980 35.500 ;
        RECT -6.860 35.220 -6.580 35.500 ;
        RECT 14.210 35.220 14.490 35.500 ;
        RECT 14.610 35.220 14.890 35.500 ;
        RECT 15.010 35.220 15.290 35.500 ;
        RECT 15.410 35.220 15.690 35.500 ;
        RECT 36.940 35.220 37.220 35.500 ;
        RECT 37.340 35.220 37.620 35.500 ;
        RECT 37.740 35.220 38.020 35.500 ;
        RECT 38.140 35.220 38.420 35.500 ;
        RECT 38.540 35.220 38.820 35.500 ;
        RECT 38.940 35.220 39.220 35.500 ;
        RECT 39.340 35.220 39.620 35.500 ;
        RECT 39.740 35.220 40.020 35.500 ;
        RECT 40.140 35.220 40.420 35.500 ;
        RECT 40.540 35.220 40.820 35.500 ;
        RECT -10.460 29.780 -10.180 30.060 ;
        RECT -10.060 29.780 -9.780 30.060 ;
        RECT -9.660 29.780 -9.380 30.060 ;
        RECT -9.260 29.780 -8.980 30.060 ;
        RECT -8.860 29.780 -8.580 30.060 ;
        RECT -8.460 29.780 -8.180 30.060 ;
        RECT -8.060 29.780 -7.780 30.060 ;
        RECT -7.660 29.780 -7.380 30.060 ;
        RECT -7.260 29.780 -6.980 30.060 ;
        RECT -6.860 29.780 -6.580 30.060 ;
        RECT 14.210 29.780 14.490 30.060 ;
        RECT 14.610 29.780 14.890 30.060 ;
        RECT 15.010 29.780 15.290 30.060 ;
        RECT 15.410 29.780 15.690 30.060 ;
        RECT 36.940 29.780 37.220 30.060 ;
        RECT 37.340 29.780 37.620 30.060 ;
        RECT 37.740 29.780 38.020 30.060 ;
        RECT 38.140 29.780 38.420 30.060 ;
        RECT 38.540 29.780 38.820 30.060 ;
        RECT 38.940 29.780 39.220 30.060 ;
        RECT 39.340 29.780 39.620 30.060 ;
        RECT 39.740 29.780 40.020 30.060 ;
        RECT 40.140 29.780 40.420 30.060 ;
        RECT 40.540 29.780 40.820 30.060 ;
        RECT -10.460 24.340 -10.180 24.620 ;
        RECT -10.060 24.340 -9.780 24.620 ;
        RECT -9.660 24.340 -9.380 24.620 ;
        RECT -9.260 24.340 -8.980 24.620 ;
        RECT -8.860 24.340 -8.580 24.620 ;
        RECT -8.460 24.340 -8.180 24.620 ;
        RECT -8.060 24.340 -7.780 24.620 ;
        RECT -7.660 24.340 -7.380 24.620 ;
        RECT -7.260 24.340 -6.980 24.620 ;
        RECT -6.860 24.340 -6.580 24.620 ;
        RECT 14.210 24.340 14.490 24.620 ;
        RECT 14.610 24.340 14.890 24.620 ;
        RECT 15.010 24.340 15.290 24.620 ;
        RECT 15.410 24.340 15.690 24.620 ;
        RECT 36.940 24.340 37.220 24.620 ;
        RECT 37.340 24.340 37.620 24.620 ;
        RECT 37.740 24.340 38.020 24.620 ;
        RECT 38.140 24.340 38.420 24.620 ;
        RECT 38.540 24.340 38.820 24.620 ;
        RECT 38.940 24.340 39.220 24.620 ;
        RECT 39.340 24.340 39.620 24.620 ;
        RECT 39.740 24.340 40.020 24.620 ;
        RECT 40.140 24.340 40.420 24.620 ;
        RECT 40.540 24.340 40.820 24.620 ;
        RECT -10.460 18.900 -10.180 19.180 ;
        RECT -10.060 18.900 -9.780 19.180 ;
        RECT -9.660 18.900 -9.380 19.180 ;
        RECT -9.260 18.900 -8.980 19.180 ;
        RECT -8.860 18.900 -8.580 19.180 ;
        RECT -8.460 18.900 -8.180 19.180 ;
        RECT -8.060 18.900 -7.780 19.180 ;
        RECT -7.660 18.900 -7.380 19.180 ;
        RECT -7.260 18.900 -6.980 19.180 ;
        RECT -6.860 18.900 -6.580 19.180 ;
        RECT 14.210 18.900 14.490 19.180 ;
        RECT 14.610 18.900 14.890 19.180 ;
        RECT 15.010 18.900 15.290 19.180 ;
        RECT 15.410 18.900 15.690 19.180 ;
        RECT 36.940 18.900 37.220 19.180 ;
        RECT 37.340 18.900 37.620 19.180 ;
        RECT 37.740 18.900 38.020 19.180 ;
        RECT 38.140 18.900 38.420 19.180 ;
        RECT 38.540 18.900 38.820 19.180 ;
        RECT 38.940 18.900 39.220 19.180 ;
        RECT 39.340 18.900 39.620 19.180 ;
        RECT 39.740 18.900 40.020 19.180 ;
        RECT 40.140 18.900 40.420 19.180 ;
        RECT 40.540 18.900 40.820 19.180 ;
        RECT -10.460 13.460 -10.180 13.740 ;
        RECT -10.060 13.460 -9.780 13.740 ;
        RECT -9.660 13.460 -9.380 13.740 ;
        RECT -9.260 13.460 -8.980 13.740 ;
        RECT -8.860 13.460 -8.580 13.740 ;
        RECT -8.460 13.460 -8.180 13.740 ;
        RECT -8.060 13.460 -7.780 13.740 ;
        RECT -7.660 13.460 -7.380 13.740 ;
        RECT -7.260 13.460 -6.980 13.740 ;
        RECT -6.860 13.460 -6.580 13.740 ;
        RECT 14.210 13.460 14.490 13.740 ;
        RECT 14.610 13.460 14.890 13.740 ;
        RECT 15.010 13.460 15.290 13.740 ;
        RECT 15.410 13.460 15.690 13.740 ;
        RECT 36.940 13.460 37.220 13.740 ;
        RECT 37.340 13.460 37.620 13.740 ;
        RECT 37.740 13.460 38.020 13.740 ;
        RECT 38.140 13.460 38.420 13.740 ;
        RECT 38.540 13.460 38.820 13.740 ;
        RECT 38.940 13.460 39.220 13.740 ;
        RECT 39.340 13.460 39.620 13.740 ;
        RECT 39.740 13.460 40.020 13.740 ;
        RECT 40.140 13.460 40.420 13.740 ;
        RECT 40.540 13.460 40.820 13.740 ;
        RECT -10.460 8.020 -10.180 8.300 ;
        RECT -10.060 8.020 -9.780 8.300 ;
        RECT -9.660 8.020 -9.380 8.300 ;
        RECT -9.260 8.020 -8.980 8.300 ;
        RECT -8.860 8.020 -8.580 8.300 ;
        RECT -8.460 8.020 -8.180 8.300 ;
        RECT -8.060 8.020 -7.780 8.300 ;
        RECT -7.660 8.020 -7.380 8.300 ;
        RECT -7.260 8.020 -6.980 8.300 ;
        RECT -6.860 8.020 -6.580 8.300 ;
        RECT 14.210 8.020 14.490 8.300 ;
        RECT 14.610 8.020 14.890 8.300 ;
        RECT 15.010 8.020 15.290 8.300 ;
        RECT 15.410 8.020 15.690 8.300 ;
        RECT 36.940 8.020 37.220 8.300 ;
        RECT 37.340 8.020 37.620 8.300 ;
        RECT 37.740 8.020 38.020 8.300 ;
        RECT 38.140 8.020 38.420 8.300 ;
        RECT 38.540 8.020 38.820 8.300 ;
        RECT 38.940 8.020 39.220 8.300 ;
        RECT 39.340 8.020 39.620 8.300 ;
        RECT 39.740 8.020 40.020 8.300 ;
        RECT 40.140 8.020 40.420 8.300 ;
        RECT 40.540 8.020 40.820 8.300 ;
        RECT -10.460 2.580 -10.180 2.860 ;
        RECT -10.060 2.580 -9.780 2.860 ;
        RECT -9.660 2.580 -9.380 2.860 ;
        RECT -9.260 2.580 -8.980 2.860 ;
        RECT -8.860 2.580 -8.580 2.860 ;
        RECT -8.460 2.580 -8.180 2.860 ;
        RECT -8.060 2.580 -7.780 2.860 ;
        RECT -7.660 2.580 -7.380 2.860 ;
        RECT -7.260 2.580 -6.980 2.860 ;
        RECT -6.860 2.580 -6.580 2.860 ;
        RECT 14.210 2.580 14.490 2.860 ;
        RECT 14.610 2.580 14.890 2.860 ;
        RECT 15.010 2.580 15.290 2.860 ;
        RECT 15.410 2.580 15.690 2.860 ;
        RECT 36.940 2.580 37.220 2.860 ;
        RECT 37.340 2.580 37.620 2.860 ;
        RECT 37.740 2.580 38.020 2.860 ;
        RECT 38.140 2.580 38.420 2.860 ;
        RECT 38.540 2.580 38.820 2.860 ;
        RECT 38.940 2.580 39.220 2.860 ;
        RECT 39.340 2.580 39.620 2.860 ;
        RECT 39.740 2.580 40.020 2.860 ;
        RECT 40.140 2.580 40.420 2.860 ;
        RECT 40.540 2.580 40.820 2.860 ;
      LAYER met3 ;
        RECT -10.620 35.195 -6.420 35.525 ;
        RECT 14.150 35.195 15.750 35.525 ;
        RECT 36.780 35.195 40.980 35.525 ;
        RECT -10.620 29.755 -6.420 30.085 ;
        RECT 14.150 29.755 15.750 30.085 ;
        RECT 36.780 29.755 40.980 30.085 ;
        RECT -10.620 24.315 -6.420 24.645 ;
        RECT 14.150 24.315 15.750 24.645 ;
        RECT 36.780 24.315 40.980 24.645 ;
        RECT -10.620 18.875 -6.420 19.205 ;
        RECT 14.150 18.875 15.750 19.205 ;
        RECT 36.780 18.875 40.980 19.205 ;
        RECT -10.620 13.435 -6.420 13.765 ;
        RECT 14.150 13.435 15.750 13.765 ;
        RECT 36.780 13.435 40.980 13.765 ;
        RECT -10.620 7.995 -6.420 8.325 ;
        RECT 14.150 7.995 15.750 8.325 ;
        RECT 36.780 7.995 40.980 8.325 ;
        RECT -10.620 2.555 -6.420 2.885 ;
        RECT 14.150 2.555 15.750 2.885 ;
        RECT 36.780 2.555 40.980 2.885 ;
      LAYER via3 ;
        RECT -10.480 35.200 -10.160 35.520 ;
        RECT -10.080 35.200 -9.760 35.520 ;
        RECT -9.680 35.200 -9.360 35.520 ;
        RECT -9.280 35.200 -8.960 35.520 ;
        RECT -8.880 35.200 -8.560 35.520 ;
        RECT -8.480 35.200 -8.160 35.520 ;
        RECT -8.080 35.200 -7.760 35.520 ;
        RECT -7.680 35.200 -7.360 35.520 ;
        RECT -7.280 35.200 -6.960 35.520 ;
        RECT -6.880 35.200 -6.560 35.520 ;
        RECT 14.190 35.200 14.510 35.520 ;
        RECT 14.590 35.200 14.910 35.520 ;
        RECT 14.990 35.200 15.310 35.520 ;
        RECT 15.390 35.200 15.710 35.520 ;
        RECT 36.920 35.200 37.240 35.520 ;
        RECT 37.320 35.200 37.640 35.520 ;
        RECT 37.720 35.200 38.040 35.520 ;
        RECT 38.120 35.200 38.440 35.520 ;
        RECT 38.520 35.200 38.840 35.520 ;
        RECT 38.920 35.200 39.240 35.520 ;
        RECT 39.320 35.200 39.640 35.520 ;
        RECT 39.720 35.200 40.040 35.520 ;
        RECT 40.120 35.200 40.440 35.520 ;
        RECT 40.520 35.200 40.840 35.520 ;
        RECT -10.480 29.760 -10.160 30.080 ;
        RECT -10.080 29.760 -9.760 30.080 ;
        RECT -9.680 29.760 -9.360 30.080 ;
        RECT -9.280 29.760 -8.960 30.080 ;
        RECT -8.880 29.760 -8.560 30.080 ;
        RECT -8.480 29.760 -8.160 30.080 ;
        RECT -8.080 29.760 -7.760 30.080 ;
        RECT -7.680 29.760 -7.360 30.080 ;
        RECT -7.280 29.760 -6.960 30.080 ;
        RECT -6.880 29.760 -6.560 30.080 ;
        RECT 14.190 29.760 14.510 30.080 ;
        RECT 14.590 29.760 14.910 30.080 ;
        RECT 14.990 29.760 15.310 30.080 ;
        RECT 15.390 29.760 15.710 30.080 ;
        RECT 36.920 29.760 37.240 30.080 ;
        RECT 37.320 29.760 37.640 30.080 ;
        RECT 37.720 29.760 38.040 30.080 ;
        RECT 38.120 29.760 38.440 30.080 ;
        RECT 38.520 29.760 38.840 30.080 ;
        RECT 38.920 29.760 39.240 30.080 ;
        RECT 39.320 29.760 39.640 30.080 ;
        RECT 39.720 29.760 40.040 30.080 ;
        RECT 40.120 29.760 40.440 30.080 ;
        RECT 40.520 29.760 40.840 30.080 ;
        RECT -10.480 24.320 -10.160 24.640 ;
        RECT -10.080 24.320 -9.760 24.640 ;
        RECT -9.680 24.320 -9.360 24.640 ;
        RECT -9.280 24.320 -8.960 24.640 ;
        RECT -8.880 24.320 -8.560 24.640 ;
        RECT -8.480 24.320 -8.160 24.640 ;
        RECT -8.080 24.320 -7.760 24.640 ;
        RECT -7.680 24.320 -7.360 24.640 ;
        RECT -7.280 24.320 -6.960 24.640 ;
        RECT -6.880 24.320 -6.560 24.640 ;
        RECT 14.190 24.320 14.510 24.640 ;
        RECT 14.590 24.320 14.910 24.640 ;
        RECT 14.990 24.320 15.310 24.640 ;
        RECT 15.390 24.320 15.710 24.640 ;
        RECT 36.920 24.320 37.240 24.640 ;
        RECT 37.320 24.320 37.640 24.640 ;
        RECT 37.720 24.320 38.040 24.640 ;
        RECT 38.120 24.320 38.440 24.640 ;
        RECT 38.520 24.320 38.840 24.640 ;
        RECT 38.920 24.320 39.240 24.640 ;
        RECT 39.320 24.320 39.640 24.640 ;
        RECT 39.720 24.320 40.040 24.640 ;
        RECT 40.120 24.320 40.440 24.640 ;
        RECT 40.520 24.320 40.840 24.640 ;
        RECT -10.480 18.880 -10.160 19.200 ;
        RECT -10.080 18.880 -9.760 19.200 ;
        RECT -9.680 18.880 -9.360 19.200 ;
        RECT -9.280 18.880 -8.960 19.200 ;
        RECT -8.880 18.880 -8.560 19.200 ;
        RECT -8.480 18.880 -8.160 19.200 ;
        RECT -8.080 18.880 -7.760 19.200 ;
        RECT -7.680 18.880 -7.360 19.200 ;
        RECT -7.280 18.880 -6.960 19.200 ;
        RECT -6.880 18.880 -6.560 19.200 ;
        RECT 14.190 18.880 14.510 19.200 ;
        RECT 14.590 18.880 14.910 19.200 ;
        RECT 14.990 18.880 15.310 19.200 ;
        RECT 15.390 18.880 15.710 19.200 ;
        RECT 36.920 18.880 37.240 19.200 ;
        RECT 37.320 18.880 37.640 19.200 ;
        RECT 37.720 18.880 38.040 19.200 ;
        RECT 38.120 18.880 38.440 19.200 ;
        RECT 38.520 18.880 38.840 19.200 ;
        RECT 38.920 18.880 39.240 19.200 ;
        RECT 39.320 18.880 39.640 19.200 ;
        RECT 39.720 18.880 40.040 19.200 ;
        RECT 40.120 18.880 40.440 19.200 ;
        RECT 40.520 18.880 40.840 19.200 ;
        RECT -10.480 13.440 -10.160 13.760 ;
        RECT -10.080 13.440 -9.760 13.760 ;
        RECT -9.680 13.440 -9.360 13.760 ;
        RECT -9.280 13.440 -8.960 13.760 ;
        RECT -8.880 13.440 -8.560 13.760 ;
        RECT -8.480 13.440 -8.160 13.760 ;
        RECT -8.080 13.440 -7.760 13.760 ;
        RECT -7.680 13.440 -7.360 13.760 ;
        RECT -7.280 13.440 -6.960 13.760 ;
        RECT -6.880 13.440 -6.560 13.760 ;
        RECT 14.190 13.440 14.510 13.760 ;
        RECT 14.590 13.440 14.910 13.760 ;
        RECT 14.990 13.440 15.310 13.760 ;
        RECT 15.390 13.440 15.710 13.760 ;
        RECT 36.920 13.440 37.240 13.760 ;
        RECT 37.320 13.440 37.640 13.760 ;
        RECT 37.720 13.440 38.040 13.760 ;
        RECT 38.120 13.440 38.440 13.760 ;
        RECT 38.520 13.440 38.840 13.760 ;
        RECT 38.920 13.440 39.240 13.760 ;
        RECT 39.320 13.440 39.640 13.760 ;
        RECT 39.720 13.440 40.040 13.760 ;
        RECT 40.120 13.440 40.440 13.760 ;
        RECT 40.520 13.440 40.840 13.760 ;
        RECT -10.480 8.000 -10.160 8.320 ;
        RECT -10.080 8.000 -9.760 8.320 ;
        RECT -9.680 8.000 -9.360 8.320 ;
        RECT -9.280 8.000 -8.960 8.320 ;
        RECT -8.880 8.000 -8.560 8.320 ;
        RECT -8.480 8.000 -8.160 8.320 ;
        RECT -8.080 8.000 -7.760 8.320 ;
        RECT -7.680 8.000 -7.360 8.320 ;
        RECT -7.280 8.000 -6.960 8.320 ;
        RECT -6.880 8.000 -6.560 8.320 ;
        RECT 14.190 8.000 14.510 8.320 ;
        RECT 14.590 8.000 14.910 8.320 ;
        RECT 14.990 8.000 15.310 8.320 ;
        RECT 15.390 8.000 15.710 8.320 ;
        RECT 36.920 8.000 37.240 8.320 ;
        RECT 37.320 8.000 37.640 8.320 ;
        RECT 37.720 8.000 38.040 8.320 ;
        RECT 38.120 8.000 38.440 8.320 ;
        RECT 38.520 8.000 38.840 8.320 ;
        RECT 38.920 8.000 39.240 8.320 ;
        RECT 39.320 8.000 39.640 8.320 ;
        RECT 39.720 8.000 40.040 8.320 ;
        RECT 40.120 8.000 40.440 8.320 ;
        RECT 40.520 8.000 40.840 8.320 ;
        RECT -10.480 2.560 -10.160 2.880 ;
        RECT -10.080 2.560 -9.760 2.880 ;
        RECT -9.680 2.560 -9.360 2.880 ;
        RECT -9.280 2.560 -8.960 2.880 ;
        RECT -8.880 2.560 -8.560 2.880 ;
        RECT -8.480 2.560 -8.160 2.880 ;
        RECT -8.080 2.560 -7.760 2.880 ;
        RECT -7.680 2.560 -7.360 2.880 ;
        RECT -7.280 2.560 -6.960 2.880 ;
        RECT -6.880 2.560 -6.560 2.880 ;
        RECT 14.190 2.560 14.510 2.880 ;
        RECT 14.590 2.560 14.910 2.880 ;
        RECT 14.990 2.560 15.310 2.880 ;
        RECT 15.390 2.560 15.710 2.880 ;
        RECT 36.920 2.560 37.240 2.880 ;
        RECT 37.320 2.560 37.640 2.880 ;
        RECT 37.720 2.560 38.040 2.880 ;
        RECT 38.120 2.560 38.440 2.880 ;
        RECT 38.520 2.560 38.840 2.880 ;
        RECT 38.920 2.560 39.240 2.880 ;
        RECT 39.320 2.560 39.640 2.880 ;
        RECT 39.720 2.560 40.040 2.880 ;
        RECT 40.120 2.560 40.440 2.880 ;
        RECT 40.520 2.560 40.840 2.880 ;
      LAYER met4 ;
        RECT -10.620 -9.280 -6.420 50.080 ;
        RECT 14.150 -9.280 15.750 50.080 ;
        RECT 36.780 -9.280 40.980 50.080 ;
      LAYER via4 ;
        RECT -9.910 46.590 -7.130 49.370 ;
        RECT -9.910 15.490 -8.730 16.670 ;
        RECT -8.310 15.490 -7.130 16.670 ;
        RECT -9.910 -8.570 -7.130 -5.790 ;
        RECT 14.360 48.190 15.540 49.370 ;
        RECT 14.360 46.590 15.540 47.770 ;
        RECT 14.360 15.490 15.540 16.670 ;
        RECT 14.360 -6.970 15.540 -5.790 ;
        RECT 14.360 -8.570 15.540 -7.390 ;
        RECT 37.490 46.590 40.270 49.370 ;
        RECT 37.490 15.490 38.670 16.670 ;
        RECT 39.090 15.490 40.270 16.670 ;
        RECT 37.490 -8.570 40.270 -5.790 ;
      LAYER met5 ;
        RECT -10.620 45.880 40.980 50.080 ;
        RECT -10.620 15.280 40.980 16.880 ;
        RECT -10.620 -9.280 40.980 -5.080 ;
    END
  END VGND
  PIN a[0]
    ANTENNAGATEAREA 0.196500 ;
    PORT
      LAYER li1 ;
        RECT 16.585 3.705 16.915 4.075 ;
      LAYER mcon ;
        RECT 16.705 3.825 16.875 3.995 ;
      LAYER met1 ;
        RECT 16.630 3.980 16.950 4.040 ;
        RECT 16.435 3.840 16.950 3.980 ;
        RECT 16.630 3.780 16.950 3.840 ;
      LAYER via ;
        RECT 16.660 3.780 16.920 4.040 ;
      LAYER met2 ;
        RECT 16.660 3.750 16.920 4.070 ;
        RECT 16.720 0.000 16.860 3.750 ;
    END
  END a[0]
  PIN a[1]
    ANTENNAGATEAREA 0.196500 ;
    PORT
      LAYER li1 ;
        RECT 17.505 6.805 17.835 7.175 ;
      LAYER mcon ;
        RECT 17.625 6.885 17.795 7.055 ;
      LAYER met1 ;
        RECT 17.550 7.040 17.870 7.100 ;
        RECT 17.355 6.900 17.870 7.040 ;
        RECT 17.550 6.840 17.870 6.900 ;
      LAYER via ;
        RECT 17.580 6.840 17.840 7.100 ;
      LAYER met2 ;
        RECT 17.580 6.810 17.840 7.130 ;
        RECT 17.640 0.000 17.780 6.810 ;
    END
  END a[1]
  PIN a[2]
    ANTENNAGATEAREA 0.126000 ;
    PORT
      LAYER li1 ;
        RECT 24.465 3.715 24.950 4.420 ;
      LAYER mcon ;
        RECT 24.525 3.825 24.695 3.995 ;
      LAYER met1 ;
        RECT 18.470 3.980 18.790 4.040 ;
        RECT 24.465 3.980 24.755 4.025 ;
        RECT 18.470 3.840 24.755 3.980 ;
        RECT 18.470 3.780 18.790 3.840 ;
        RECT 24.465 3.795 24.755 3.840 ;
      LAYER via ;
        RECT 18.500 3.780 18.760 4.040 ;
      LAYER met2 ;
        RECT 18.500 3.750 18.760 4.070 ;
        RECT 18.560 0.000 18.700 3.750 ;
    END
  END a[2]
  PIN a[3]
    ANTENNAGATEAREA 0.213000 ;
    PORT
      LAYER li1 ;
        RECT 17.445 3.465 17.805 4.045 ;
      LAYER mcon ;
        RECT 17.625 3.485 17.795 3.655 ;
      LAYER met1 ;
        RECT 17.565 3.640 17.855 3.685 ;
        RECT 18.930 3.640 19.250 3.700 ;
        RECT 17.565 3.500 19.250 3.640 ;
        RECT 17.565 3.455 17.855 3.500 ;
        RECT 18.930 3.440 19.250 3.500 ;
      LAYER via ;
        RECT 18.960 3.440 19.220 3.700 ;
      LAYER met2 ;
        RECT 18.960 3.410 19.220 3.730 ;
        RECT 19.020 1.770 19.160 3.410 ;
        RECT 19.020 1.630 19.620 1.770 ;
        RECT 19.480 0.000 19.620 1.630 ;
    END
  END a[3]
  PIN a[4]
    ANTENNAGATEAREA 0.213000 ;
    PORT
      LAYER li1 ;
        RECT 19.285 3.465 19.645 4.045 ;
      LAYER mcon ;
        RECT 19.465 3.485 19.635 3.655 ;
      LAYER met1 ;
        RECT 19.405 3.640 19.695 3.685 ;
        RECT 20.310 3.640 20.630 3.700 ;
        RECT 19.405 3.500 20.630 3.640 ;
        RECT 19.405 3.455 19.695 3.500 ;
        RECT 20.310 3.440 20.630 3.500 ;
      LAYER via ;
        RECT 20.340 3.440 20.600 3.700 ;
      LAYER met2 ;
        RECT 20.340 3.410 20.600 3.730 ;
        RECT 20.400 0.000 20.540 3.410 ;
    END
  END a[4]
  PIN a[5]
    ANTENNAGATEAREA 0.213000 ;
    PORT
      LAYER li1 ;
        RECT 21.125 3.465 21.485 4.045 ;
      LAYER mcon ;
        RECT 21.305 3.485 21.475 3.655 ;
      LAYER met1 ;
        RECT 21.230 3.640 21.550 3.700 ;
        RECT 21.035 3.500 21.550 3.640 ;
        RECT 21.230 3.440 21.550 3.500 ;
      LAYER via ;
        RECT 21.260 3.440 21.520 3.700 ;
      LAYER met2 ;
        RECT 21.260 3.410 21.520 3.730 ;
        RECT 21.320 0.000 21.460 3.410 ;
    END
  END a[5]
  PIN s[0]
    ANTENNADIFFAREA 0.340600 ;
    PORT
      LAYER li1 ;
        RECT 18.485 36.920 18.755 37.825 ;
        RECT 18.485 36.120 18.655 36.920 ;
        RECT 18.485 35.615 18.745 36.120 ;
      LAYER mcon ;
        RECT 18.545 37.485 18.715 37.655 ;
      LAYER met1 ;
        RECT 18.470 37.640 18.790 37.700 ;
        RECT 18.275 37.500 18.790 37.640 ;
        RECT 18.470 37.440 18.790 37.500 ;
      LAYER via ;
        RECT 18.500 37.440 18.760 37.700 ;
      LAYER met2 ;
        RECT 18.560 37.730 18.700 40.000 ;
        RECT 18.500 37.410 18.760 37.730 ;
    END
  END s[0]
  PIN s[10]
    ANTENNADIFFAREA 0.340600 ;
    PORT
      LAYER li1 ;
        RECT 6.985 36.920 7.255 37.825 ;
        RECT 6.985 36.120 7.155 36.920 ;
        RECT 6.985 35.615 7.245 36.120 ;
      LAYER mcon ;
        RECT 7.045 37.485 7.215 37.655 ;
      LAYER met1 ;
        RECT 6.985 37.640 7.275 37.685 ;
        RECT 9.270 37.640 9.590 37.700 ;
        RECT 6.985 37.500 9.590 37.640 ;
        RECT 6.985 37.455 7.275 37.500 ;
        RECT 9.270 37.440 9.590 37.500 ;
      LAYER via ;
        RECT 9.300 37.440 9.560 37.700 ;
      LAYER met2 ;
        RECT 9.360 37.730 9.500 40.000 ;
        RECT 9.300 37.410 9.560 37.730 ;
    END
  END s[10]
  PIN s[11]
    ANTENNADIFFAREA 0.340600 ;
    PORT
      LAYER li1 ;
        RECT 5.605 36.920 5.875 37.825 ;
        RECT 5.605 36.120 5.775 36.920 ;
        RECT 5.605 35.615 5.865 36.120 ;
      LAYER mcon ;
        RECT 5.665 37.485 5.835 37.655 ;
      LAYER met1 ;
        RECT 5.605 37.640 5.895 37.685 ;
        RECT 6.510 37.640 6.830 37.700 ;
        RECT 5.605 37.500 6.830 37.640 ;
        RECT 5.605 37.455 5.895 37.500 ;
        RECT 6.510 37.440 6.830 37.500 ;
      LAYER via ;
        RECT 6.540 37.440 6.800 37.700 ;
      LAYER met2 ;
        RECT 6.600 39.710 8.120 39.850 ;
        RECT 6.600 37.730 6.740 39.710 ;
        RECT 7.980 39.170 8.120 39.710 ;
        RECT 8.440 39.170 8.580 40.000 ;
        RECT 7.980 39.030 8.580 39.170 ;
        RECT 6.540 37.410 6.800 37.730 ;
    END
  END s[11]
  PIN s[1]
    ANTENNADIFFAREA 0.340600 ;
    PORT
      LAYER li1 ;
        RECT 17.105 36.920 17.375 37.825 ;
        RECT 17.105 36.120 17.275 36.920 ;
        RECT 17.105 35.615 17.365 36.120 ;
      LAYER mcon ;
        RECT 17.165 37.485 17.335 37.655 ;
      LAYER met1 ;
        RECT 17.105 37.640 17.395 37.685 ;
        RECT 17.550 37.640 17.870 37.700 ;
        RECT 17.105 37.500 17.870 37.640 ;
        RECT 17.105 37.455 17.395 37.500 ;
        RECT 17.550 37.440 17.870 37.500 ;
      LAYER via ;
        RECT 17.580 37.440 17.840 37.700 ;
      LAYER met2 ;
        RECT 17.640 37.730 17.780 40.000 ;
        RECT 17.580 37.410 17.840 37.730 ;
    END
  END s[1]
  PIN s[2]
    ANTENNADIFFAREA 0.340600 ;
    PORT
      LAYER li1 ;
        RECT 21.245 36.920 21.515 37.825 ;
        RECT 21.245 36.120 21.415 36.920 ;
        RECT 21.245 35.615 21.505 36.120 ;
      LAYER mcon ;
        RECT 21.305 35.785 21.475 35.955 ;
      LAYER met1 ;
        RECT 16.630 35.940 16.950 36.000 ;
        RECT 21.245 35.940 21.535 35.985 ;
        RECT 16.630 35.800 21.535 35.940 ;
        RECT 16.630 35.740 16.950 35.800 ;
        RECT 21.245 35.755 21.535 35.800 ;
      LAYER via ;
        RECT 16.660 35.740 16.920 36.000 ;
      LAYER met2 ;
        RECT 16.720 36.030 16.860 40.000 ;
        RECT 16.660 35.710 16.920 36.030 ;
    END
  END s[2]
  PIN s[3]
    ANTENNADIFFAREA 0.340600 ;
    PORT
      LAYER li1 ;
        RECT 19.865 36.920 20.135 37.825 ;
        RECT 19.865 36.120 20.035 36.920 ;
        RECT 19.865 35.615 20.125 36.120 ;
      LAYER mcon ;
        RECT 19.925 37.145 20.095 37.315 ;
      LAYER met1 ;
        RECT 16.170 37.300 16.490 37.360 ;
        RECT 19.865 37.300 20.155 37.345 ;
        RECT 16.170 37.160 20.155 37.300 ;
        RECT 16.170 37.100 16.490 37.160 ;
        RECT 19.865 37.115 20.155 37.160 ;
      LAYER via ;
        RECT 16.200 37.100 16.460 37.360 ;
      LAYER met2 ;
        RECT 15.800 37.810 15.940 40.000 ;
        RECT 15.800 37.670 16.400 37.810 ;
        RECT 16.260 37.390 16.400 37.670 ;
        RECT 16.200 37.070 16.460 37.390 ;
    END
  END s[3]
  PIN s[4]
    ANTENNADIFFAREA 0.340600 ;
    PORT
      LAYER li1 ;
        RECT 15.725 36.920 15.995 37.825 ;
        RECT 15.725 36.120 15.895 36.920 ;
        RECT 15.725 35.615 15.985 36.120 ;
      LAYER mcon ;
        RECT 15.785 37.485 15.955 37.655 ;
      LAYER met1 ;
        RECT 14.790 37.640 15.110 37.700 ;
        RECT 15.725 37.640 16.015 37.685 ;
        RECT 14.790 37.500 16.015 37.640 ;
        RECT 14.790 37.440 15.110 37.500 ;
        RECT 15.725 37.455 16.015 37.500 ;
      LAYER via ;
        RECT 14.820 37.440 15.080 37.700 ;
      LAYER met2 ;
        RECT 14.880 37.730 15.020 40.000 ;
        RECT 14.820 37.410 15.080 37.730 ;
    END
  END s[4]
  PIN s[5]
    ANTENNADIFFAREA 0.340600 ;
    PORT
      LAYER li1 ;
        RECT 13.885 36.920 14.155 37.825 ;
        RECT 13.885 36.120 14.055 36.920 ;
        RECT 13.885 35.615 14.145 36.120 ;
      LAYER mcon ;
        RECT 13.945 37.485 14.115 37.655 ;
      LAYER met1 ;
        RECT 13.870 37.640 14.190 37.700 ;
        RECT 13.675 37.500 14.190 37.640 ;
        RECT 13.870 37.440 14.190 37.500 ;
      LAYER via ;
        RECT 13.900 37.440 14.160 37.700 ;
      LAYER met2 ;
        RECT 13.960 37.730 14.100 40.000 ;
        RECT 13.900 37.410 14.160 37.730 ;
    END
  END s[5]
  PIN s[6]
    ANTENNADIFFAREA 0.340600 ;
    PORT
      LAYER li1 ;
        RECT 12.045 34.600 12.305 35.105 ;
        RECT 12.045 33.800 12.215 34.600 ;
        RECT 12.045 32.895 12.315 33.800 ;
      LAYER mcon ;
        RECT 12.105 33.405 12.275 33.575 ;
      LAYER met1 ;
        RECT 12.045 33.560 12.335 33.605 ;
        RECT 12.950 33.560 13.270 33.620 ;
        RECT 12.045 33.420 13.270 33.560 ;
        RECT 12.045 33.375 12.335 33.420 ;
        RECT 12.950 33.360 13.270 33.420 ;
      LAYER via ;
        RECT 12.980 33.360 13.240 33.620 ;
      LAYER met2 ;
        RECT 13.040 33.650 13.180 40.000 ;
        RECT 12.980 33.330 13.240 33.650 ;
    END
  END s[6]
  PIN s[7]
    ANTENNADIFFAREA 0.340600 ;
    PORT
      LAYER li1 ;
        RECT 11.125 36.920 11.395 37.825 ;
        RECT 11.125 36.120 11.295 36.920 ;
        RECT 11.125 35.615 11.385 36.120 ;
      LAYER mcon ;
        RECT 11.185 37.485 11.355 37.655 ;
      LAYER met1 ;
        RECT 11.125 37.640 11.415 37.685 ;
        RECT 12.030 37.640 12.350 37.700 ;
        RECT 11.125 37.500 12.350 37.640 ;
        RECT 11.125 37.455 11.415 37.500 ;
        RECT 12.030 37.440 12.350 37.500 ;
      LAYER via ;
        RECT 12.060 37.440 12.320 37.700 ;
      LAYER met2 ;
        RECT 12.120 37.730 12.260 40.000 ;
        RECT 12.060 37.410 12.320 37.730 ;
    END
  END s[7]
  PIN s[8]
    ANTENNADIFFAREA 0.340600 ;
    PORT
      LAYER li1 ;
        RECT 9.745 36.920 10.015 37.825 ;
        RECT 9.745 36.120 9.915 36.920 ;
        RECT 9.745 35.615 10.005 36.120 ;
      LAYER mcon ;
        RECT 9.805 37.485 9.975 37.655 ;
      LAYER met1 ;
        RECT 9.745 37.640 10.035 37.685 ;
        RECT 10.650 37.640 10.970 37.700 ;
        RECT 9.745 37.500 10.970 37.640 ;
        RECT 9.745 37.455 10.035 37.500 ;
        RECT 10.650 37.440 10.970 37.500 ;
      LAYER via ;
        RECT 10.680 37.440 10.940 37.700 ;
      LAYER met2 ;
        RECT 11.200 37.810 11.340 40.000 ;
        RECT 10.740 37.730 11.340 37.810 ;
        RECT 10.680 37.670 11.340 37.730 ;
        RECT 10.680 37.410 10.940 37.670 ;
    END
  END s[8]
  PIN s[9]
    ANTENNADIFFAREA 0.340600 ;
    PORT
      LAYER li1 ;
        RECT 8.365 36.920 8.635 37.825 ;
        RECT 8.365 36.120 8.535 36.920 ;
        RECT 8.365 35.615 8.625 36.120 ;
      LAYER mcon ;
        RECT 8.425 37.145 8.595 37.315 ;
      LAYER met1 ;
        RECT 8.365 37.300 8.655 37.345 ;
        RECT 10.190 37.300 10.510 37.360 ;
        RECT 8.365 37.160 10.510 37.300 ;
        RECT 8.365 37.115 8.655 37.160 ;
        RECT 10.190 37.100 10.510 37.160 ;
      LAYER via ;
        RECT 10.220 37.100 10.480 37.360 ;
      LAYER met2 ;
        RECT 10.280 37.390 10.420 40.000 ;
        RECT 10.220 37.070 10.480 37.390 ;
    END
  END s[9]
  OBS
      LAYER pwell ;
        RECT 1.510 35.240 1.730 35.480 ;
        RECT 5.525 35.465 6.895 36.245 ;
        RECT 6.905 35.465 8.275 36.245 ;
        RECT 8.285 35.465 9.655 36.245 ;
        RECT 9.665 35.465 11.035 36.245 ;
        RECT 11.045 35.465 12.415 36.245 ;
        RECT 12.630 35.465 13.560 36.375 ;
        RECT 13.805 35.465 15.175 36.245 ;
        RECT 15.645 35.465 17.015 36.245 ;
        RECT 17.025 35.465 18.395 36.245 ;
        RECT 18.405 35.465 19.775 36.245 ;
        RECT 19.785 35.465 21.155 36.245 ;
        RECT 21.165 35.465 22.535 36.245 ;
        RECT 5.235 35.415 5.345 35.420 ;
        RECT 5.200 35.305 5.345 35.415 ;
        RECT 5.235 35.300 5.345 35.305 ;
        RECT 6.585 35.275 6.755 35.465 ;
        RECT 7.040 35.305 7.160 35.415 ;
        RECT 7.505 35.275 7.675 35.445 ;
        RECT 7.965 35.275 8.135 35.465 ;
        RECT 7.570 35.255 7.675 35.275 ;
        RECT 8.880 35.255 9.050 35.445 ;
        RECT 9.345 35.275 9.515 35.465 ;
        RECT 10.265 35.255 10.435 35.445 ;
        RECT 10.725 35.275 10.895 35.465 ;
        RECT 12.105 35.275 12.275 35.465 ;
        RECT 12.630 35.445 12.735 35.465 ;
        RECT 12.565 35.275 12.735 35.445 ;
        RECT 13.025 35.255 13.195 35.445 ;
        RECT 13.490 35.255 13.660 35.445 ;
        RECT 14.865 35.275 15.035 35.465 ;
        RECT 16.705 35.275 16.875 35.465 ;
        RECT 18.085 35.275 18.255 35.465 ;
        RECT 19.465 35.445 19.635 35.465 ;
        RECT 20.845 35.445 21.015 35.465 ;
        RECT 18.150 35.255 18.255 35.275 ;
        RECT 19.460 35.275 19.635 35.445 ;
        RECT 20.840 35.275 21.015 35.445 ;
        RECT 22.225 35.275 22.395 35.465 ;
        RECT 19.460 35.255 19.630 35.275 ;
        RECT 20.840 35.255 21.010 35.275 ;
        RECT 22.290 35.255 22.395 35.275 ;
        RECT 22.670 35.255 22.890 35.410 ;
        RECT 23.600 35.255 23.770 35.445 ;
        RECT 24.970 35.310 25.190 35.480 ;
        RECT 26.395 35.300 26.505 35.420 ;
        RECT 28.215 35.310 28.375 35.420 ;
        RECT 28.660 35.305 28.780 35.415 ;
        RECT 7.570 34.345 8.500 35.255 ;
        RECT 8.765 34.345 10.115 35.255 ;
        RECT 10.140 34.345 11.955 35.255 ;
        RECT 11.965 34.475 13.335 35.255 ;
        RECT 13.345 34.575 17.935 35.255 ;
        RECT 13.345 34.345 14.275 34.575 ;
        RECT 17.015 34.345 17.935 34.575 ;
        RECT 18.150 34.345 19.080 35.255 ;
        RECT 19.345 34.345 20.695 35.255 ;
        RECT 20.725 34.345 22.075 35.255 ;
        RECT 22.290 34.345 23.220 35.255 ;
        RECT 23.485 34.345 24.835 35.255 ;
        RECT 1.510 29.800 1.730 30.040 ;
        RECT 5.190 29.870 5.410 30.040 ;
        RECT 7.845 30.025 9.195 30.935 ;
        RECT 9.225 30.025 10.575 30.935 ;
        RECT 10.585 30.255 13.335 30.935 ;
        RECT 10.725 30.040 13.335 30.255 ;
        RECT 10.710 30.025 13.335 30.040 ;
        RECT 7.055 29.870 7.215 29.980 ;
        RECT 5.235 29.860 5.345 29.870 ;
        RECT 7.960 29.835 8.130 30.025 ;
        RECT 8.880 29.865 9.000 29.975 ;
        RECT 9.340 29.815 9.510 30.025 ;
        RECT 10.710 29.870 10.930 30.025 ;
        RECT 10.725 29.835 10.895 29.870 ;
        RECT 13.515 29.860 13.625 29.980 ;
        RECT 14.390 29.870 14.610 30.040 ;
        RECT 18.405 30.025 20.695 30.935 ;
        RECT 20.705 30.025 22.535 30.935 ;
        RECT 15.815 29.860 15.925 29.980 ;
        RECT 17.635 29.870 17.795 29.980 ;
        RECT 18.095 29.860 18.255 29.970 ;
        RECT 18.550 29.835 18.720 30.025 ;
        RECT 19.005 29.815 19.175 30.005 ;
        RECT 20.390 29.815 20.560 30.005 ;
        RECT 20.850 29.835 21.020 30.025 ;
        RECT 22.210 29.870 22.430 30.025 ;
        RECT 9.225 28.905 10.575 29.815 ;
        RECT 18.875 28.905 20.225 29.815 ;
        RECT 20.245 28.905 22.075 29.815 ;
        RECT 22.670 29.800 22.890 29.970 ;
        RECT 25.935 29.860 26.045 29.980 ;
        RECT 26.395 29.860 26.505 29.980 ;
        RECT 27.755 29.860 27.915 29.970 ;
        RECT 28.215 29.870 28.375 29.980 ;
        RECT 28.660 29.865 28.780 29.975 ;
        RECT 1.510 24.360 1.730 24.600 ;
        RECT 5.190 24.360 5.410 24.600 ;
        RECT 8.870 24.430 9.090 24.600 ;
        RECT 10.130 24.585 11.495 25.265 ;
        RECT 13.345 24.585 15.115 25.495 ;
        RECT 16.580 24.585 18.395 25.495 ;
        RECT 18.610 24.585 19.540 25.495 ;
        RECT 13.490 24.565 13.660 24.585 ;
        RECT 9.805 24.395 9.975 24.565 ;
        RECT 11.675 24.420 11.785 24.540 ;
        RECT 12.575 24.420 12.735 24.530 ;
        RECT 13.485 24.395 13.660 24.565 ;
        RECT 15.795 24.535 15.955 24.540 ;
        RECT 14.875 24.420 15.035 24.530 ;
        RECT 15.780 24.430 15.955 24.535 ;
        RECT 15.780 24.425 15.900 24.430 ;
        RECT 13.550 24.375 13.655 24.395 ;
        RECT 16.250 24.375 16.420 24.565 ;
        RECT 16.705 24.395 16.875 24.585 ;
        RECT 18.610 24.565 18.715 24.585 ;
        RECT 18.090 24.375 18.260 24.565 ;
        RECT 18.545 24.395 18.715 24.565 ;
        RECT 13.550 23.465 14.480 24.375 ;
        RECT 16.105 23.465 17.935 24.375 ;
        RECT 17.945 23.465 19.775 24.375 ;
        RECT 19.910 24.360 20.130 24.600 ;
        RECT 23.590 24.360 23.810 24.600 ;
        RECT 27.315 24.420 27.425 24.540 ;
        RECT 1.510 18.920 1.730 19.160 ;
        RECT 5.190 18.990 5.410 19.160 ;
        RECT 8.030 19.145 8.960 20.055 ;
        RECT 9.225 19.145 10.575 20.055 ;
        RECT 8.030 19.125 8.135 19.145 ;
        RECT 7.055 18.990 7.215 19.100 ;
        RECT 5.235 18.980 5.345 18.990 ;
        RECT 7.965 18.955 8.135 19.125 ;
        RECT 8.880 18.985 9.000 19.095 ;
        RECT 9.340 18.935 9.510 19.145 ;
        RECT 9.225 18.025 10.575 18.935 ;
        RECT 10.710 18.920 10.930 19.160 ;
        RECT 16.125 19.145 17.475 20.055 ;
        RECT 17.505 19.145 18.855 20.055 ;
        RECT 18.885 19.145 20.235 20.055 ;
        RECT 20.265 19.145 21.615 20.055 ;
        RECT 14.415 18.990 14.575 19.100 ;
        RECT 14.435 18.980 14.545 18.990 ;
        RECT 15.780 18.985 15.900 19.095 ;
        RECT 16.240 19.090 16.410 19.145 ;
        RECT 16.240 18.980 16.415 19.090 ;
        RECT 16.240 18.955 16.410 18.980 ;
        RECT 17.165 18.955 17.335 19.125 ;
        RECT 17.620 18.955 17.790 19.145 ;
        RECT 18.530 18.990 18.750 19.145 ;
        RECT 19.000 18.955 19.170 19.145 ;
        RECT 20.380 18.955 20.550 19.145 ;
        RECT 21.775 18.990 21.935 19.100 ;
        RECT 22.210 18.990 22.430 19.160 ;
        RECT 22.565 19.145 23.915 20.055 ;
        RECT 22.680 18.955 22.850 19.145 ;
        RECT 17.230 18.935 17.335 18.955 ;
        RECT 17.230 18.025 18.160 18.935 ;
        RECT 24.050 18.920 24.270 19.090 ;
        RECT 25.935 18.980 26.045 19.100 ;
        RECT 27.755 18.980 27.915 19.100 ;
        RECT 28.660 18.985 28.780 19.095 ;
        RECT 1.510 13.480 1.730 13.720 ;
        RECT 5.190 13.480 5.410 13.720 ;
        RECT 9.665 13.705 11.435 14.615 ;
        RECT 11.505 13.705 12.855 14.615 ;
        RECT 16.565 13.705 18.855 14.615 ;
        RECT 18.865 13.705 20.695 14.615 ;
        RECT 8.895 13.655 9.055 13.660 ;
        RECT 8.880 13.550 9.055 13.655 ;
        RECT 8.880 13.545 9.000 13.550 ;
        RECT 9.350 13.495 9.520 13.685 ;
        RECT 9.810 13.515 9.980 13.705 ;
        RECT 11.630 13.550 11.850 13.705 ;
        RECT 16.705 13.685 16.875 13.705 ;
        RECT 11.650 13.515 11.820 13.550 ;
        RECT 13.055 13.540 13.165 13.660 ;
        RECT 14.860 13.545 14.980 13.655 ;
        RECT 15.335 13.540 15.495 13.650 ;
        RECT 15.795 13.550 15.955 13.660 ;
        RECT 16.240 13.545 16.360 13.655 ;
        RECT 16.700 13.515 16.875 13.685 ;
        RECT 16.700 13.495 16.870 13.515 ;
        RECT 18.085 13.495 18.255 13.685 ;
        RECT 19.010 13.515 19.180 13.705 ;
        RECT 19.920 13.545 20.040 13.655 ;
        RECT 20.390 13.495 20.560 13.685 ;
        RECT 20.830 13.495 21.050 13.650 ;
        RECT 22.210 13.550 22.430 13.720 ;
        RECT 9.205 12.585 11.395 13.495 ;
        RECT 16.585 12.585 17.935 13.495 ;
        RECT 17.970 12.815 19.770 13.495 ;
        RECT 20.245 12.585 22.075 13.495 ;
        RECT 24.510 13.480 24.730 13.650 ;
        RECT 25.935 13.540 26.045 13.660 ;
        RECT 27.755 13.540 27.915 13.650 ;
        RECT 28.215 13.550 28.375 13.660 ;
        RECT 28.660 13.545 28.780 13.655 ;
        RECT 1.510 8.040 1.730 8.280 ;
        RECT 8.310 8.265 10.110 8.945 ;
        RECT 10.605 8.265 11.955 9.175 ;
        RECT 12.430 8.265 13.795 8.945 ;
        RECT 17.230 8.265 18.160 9.175 ;
        RECT 18.905 8.265 22.075 9.175 ;
        RECT 22.105 8.265 23.455 9.175 ;
        RECT 5.235 8.100 5.345 8.220 ;
        RECT 7.055 8.100 7.215 8.220 ;
        RECT 7.960 8.055 8.130 8.245 ;
        RECT 8.425 8.075 8.595 8.265 ;
        RECT 9.375 8.100 9.485 8.220 ;
        RECT 10.260 8.105 10.380 8.215 ;
        RECT 10.720 8.075 10.890 8.265 ;
        RECT 17.230 8.245 17.335 8.265 ;
        RECT 11.195 8.100 11.355 8.210 ;
        RECT 12.105 8.075 12.275 8.245 ;
        RECT 12.170 8.055 12.275 8.075 ;
        RECT 13.480 8.055 13.650 8.245 ;
        RECT 13.955 8.110 14.115 8.220 ;
        RECT 14.860 8.105 14.980 8.215 ;
        RECT 15.320 8.055 15.490 8.245 ;
        RECT 15.795 8.110 15.955 8.220 ;
        RECT 16.700 8.105 16.820 8.215 ;
        RECT 17.165 8.075 17.335 8.245 ;
        RECT 17.625 8.055 17.795 8.245 ;
        RECT 18.085 8.075 18.255 8.245 ;
        RECT 18.540 8.105 18.660 8.215 ;
        RECT 19.005 8.075 19.175 8.265 ;
        RECT 18.150 8.055 18.255 8.075 ;
        RECT 19.465 8.055 19.635 8.245 ;
        RECT 21.310 8.055 21.480 8.245 ;
        RECT 22.220 8.075 22.390 8.265 ;
        RECT 23.140 8.055 23.310 8.245 ;
        RECT 23.590 8.055 23.810 8.210 ;
        RECT 24.510 8.110 24.730 8.280 ;
        RECT 27.315 8.100 27.425 8.220 ;
        RECT 28.215 8.100 28.375 8.210 ;
        RECT 7.845 7.145 9.195 8.055 ;
        RECT 12.170 7.145 13.100 8.055 ;
        RECT 13.365 7.145 14.715 8.055 ;
        RECT 15.205 7.145 16.555 8.055 ;
        RECT 16.565 7.275 17.935 8.055 ;
        RECT 18.150 7.145 19.080 8.055 ;
        RECT 19.350 7.375 21.150 8.055 ;
        RECT 21.165 7.145 22.995 8.055 ;
        RECT 23.025 7.145 24.375 8.055 ;
        RECT 15.645 2.825 17.015 3.605 ;
        RECT 25.045 3.505 28.975 3.735 ;
        RECT 17.025 2.825 18.855 3.505 ;
        RECT 18.865 2.825 20.695 3.505 ;
        RECT 20.705 2.825 22.535 3.505 ;
        RECT 24.560 2.825 28.975 3.505 ;
        RECT 1.510 2.600 1.730 2.770 ;
        RECT 5.190 2.600 5.410 2.770 ;
        RECT 8.870 2.600 9.090 2.770 ;
        RECT 12.595 2.660 12.705 2.780 ;
        RECT 14.415 2.670 14.575 2.780 ;
        RECT 16.705 2.635 16.875 2.825 ;
        RECT 17.165 2.635 17.335 2.825 ;
        RECT 19.005 2.635 19.175 2.825 ;
        RECT 20.845 2.635 21.015 2.825 ;
        RECT 24.560 2.805 24.670 2.825 ;
        RECT 22.715 2.660 22.825 2.780 ;
        RECT 24.500 2.635 24.670 2.805 ;
      LAYER li1 ;
        RECT 6.555 37.065 6.725 37.825 ;
        RECT 7.935 37.065 8.105 37.825 ;
        RECT 9.315 37.065 9.485 37.825 ;
        RECT 10.695 37.065 10.865 37.825 ;
        RECT 12.075 37.065 12.245 37.825 ;
        RECT 6.060 36.895 6.725 37.065 ;
        RECT 7.440 36.895 8.105 37.065 ;
        RECT 8.820 36.895 9.485 37.065 ;
        RECT 10.200 36.895 10.865 37.065 ;
        RECT 11.580 36.895 12.245 37.065 ;
        RECT 6.060 36.750 6.230 36.895 ;
        RECT 7.440 36.750 7.610 36.895 ;
        RECT 8.820 36.750 8.990 36.895 ;
        RECT 10.200 36.750 10.370 36.895 ;
        RECT 11.580 36.750 11.750 36.895 ;
        RECT 13.140 36.845 13.470 37.825 ;
        RECT 14.835 37.065 15.005 37.825 ;
        RECT 16.675 37.065 16.845 37.825 ;
        RECT 18.055 37.065 18.225 37.825 ;
        RECT 19.435 37.065 19.605 37.825 ;
        RECT 20.815 37.065 20.985 37.825 ;
        RECT 22.195 37.065 22.365 37.825 ;
        RECT 5.945 36.420 6.230 36.750 ;
        RECT 6.060 36.165 6.230 36.420 ;
        RECT 6.465 36.345 6.795 36.715 ;
        RECT 7.325 36.420 7.610 36.750 ;
        RECT 7.440 36.165 7.610 36.420 ;
        RECT 7.845 36.345 8.175 36.715 ;
        RECT 8.705 36.420 8.990 36.750 ;
        RECT 8.820 36.165 8.990 36.420 ;
        RECT 9.225 36.345 9.555 36.715 ;
        RECT 10.085 36.420 10.370 36.750 ;
        RECT 10.200 36.165 10.370 36.420 ;
        RECT 10.605 36.345 10.935 36.715 ;
        RECT 11.465 36.420 11.750 36.750 ;
        RECT 11.580 36.165 11.750 36.420 ;
        RECT 11.985 36.345 12.315 36.715 ;
        RECT 12.740 36.435 13.070 36.675 ;
        RECT 13.240 36.245 13.470 36.845 ;
        RECT 14.340 36.895 15.005 37.065 ;
        RECT 16.180 36.895 16.845 37.065 ;
        RECT 17.560 36.895 18.225 37.065 ;
        RECT 18.940 36.895 19.605 37.065 ;
        RECT 20.320 36.895 20.985 37.065 ;
        RECT 21.700 36.895 22.365 37.065 ;
        RECT 14.340 36.750 14.510 36.895 ;
        RECT 16.180 36.750 16.350 36.895 ;
        RECT 17.560 36.750 17.730 36.895 ;
        RECT 18.940 36.750 19.110 36.895 ;
        RECT 20.320 36.750 20.490 36.895 ;
        RECT 21.700 36.750 21.870 36.895 ;
        RECT 14.225 36.420 14.510 36.750 ;
        RECT 6.060 35.995 6.725 36.165 ;
        RECT 7.440 35.995 8.105 36.165 ;
        RECT 8.820 35.995 9.485 36.165 ;
        RECT 10.200 35.995 10.865 36.165 ;
        RECT 11.580 35.995 12.245 36.165 ;
        RECT 6.555 35.615 6.725 35.995 ;
        RECT 7.935 35.615 8.105 35.995 ;
        RECT 9.315 35.615 9.485 35.995 ;
        RECT 10.695 35.615 10.865 35.995 ;
        RECT 12.075 35.615 12.245 35.995 ;
        RECT 13.140 35.615 13.470 36.245 ;
        RECT 14.340 36.165 14.510 36.420 ;
        RECT 14.745 36.345 15.075 36.715 ;
        RECT 16.065 36.420 16.350 36.750 ;
        RECT 16.180 36.165 16.350 36.420 ;
        RECT 16.585 36.345 16.915 36.715 ;
        RECT 17.445 36.420 17.730 36.750 ;
        RECT 17.560 36.165 17.730 36.420 ;
        RECT 17.965 36.345 18.295 36.715 ;
        RECT 18.825 36.420 19.110 36.750 ;
        RECT 18.940 36.165 19.110 36.420 ;
        RECT 19.345 36.345 19.675 36.715 ;
        RECT 20.205 36.420 20.490 36.750 ;
        RECT 20.320 36.165 20.490 36.420 ;
        RECT 20.725 36.345 21.055 36.715 ;
        RECT 21.585 36.420 21.870 36.750 ;
        RECT 21.700 36.165 21.870 36.420 ;
        RECT 22.105 36.345 22.435 36.715 ;
        RECT 14.340 35.995 15.005 36.165 ;
        RECT 16.180 35.995 16.845 36.165 ;
        RECT 17.560 35.995 18.225 36.165 ;
        RECT 18.940 35.995 19.605 36.165 ;
        RECT 20.320 35.995 20.985 36.165 ;
        RECT 21.700 35.995 22.365 36.165 ;
        RECT 14.835 35.615 15.005 35.995 ;
        RECT 16.675 35.615 16.845 35.995 ;
        RECT 18.055 35.615 18.225 35.995 ;
        RECT 19.435 35.615 19.605 35.995 ;
        RECT 20.815 35.615 20.985 35.995 ;
        RECT 22.195 35.615 22.365 35.995 ;
        RECT 8.080 34.475 8.410 35.105 ;
        RECT 7.680 34.045 8.010 34.285 ;
        RECT 8.180 33.875 8.410 34.475 ;
        RECT 9.340 34.475 10.035 35.105 ;
        RECT 10.730 34.715 10.955 35.095 ;
        RECT 8.835 34.035 9.170 34.305 ;
        RECT 9.340 33.875 9.510 34.475 ;
        RECT 9.680 34.035 10.015 34.285 ;
        RECT 10.215 34.035 10.455 34.685 ;
        RECT 10.625 34.535 10.955 34.715 ;
        RECT 8.080 32.895 8.410 33.875 ;
        RECT 9.275 32.895 9.605 33.875 ;
        RECT 10.625 33.865 10.800 34.535 ;
        RECT 11.155 34.365 11.385 34.985 ;
        RECT 12.995 34.725 13.165 35.105 ;
        RECT 12.500 34.555 13.165 34.725 ;
        RECT 10.970 34.035 11.385 34.365 ;
        RECT 11.565 34.035 11.860 34.365 ;
        RECT 12.500 34.300 12.670 34.555 ;
        RECT 13.430 34.535 13.765 35.045 ;
        RECT 14.300 34.685 14.625 35.015 ;
        RECT 14.875 34.725 15.045 35.015 ;
        RECT 15.715 34.725 15.885 35.015 ;
        RECT 12.385 33.970 12.670 34.300 ;
        RECT 12.905 34.005 13.235 34.375 ;
        RECT 10.215 33.675 10.800 33.865 ;
        RECT 10.215 32.905 10.490 33.675 ;
        RECT 10.970 33.505 11.865 33.835 ;
        RECT 12.500 33.825 12.670 33.970 ;
        RECT 12.500 33.655 13.165 33.825 ;
        RECT 10.660 33.335 11.865 33.505 ;
        RECT 10.660 32.905 10.990 33.335 ;
        RECT 11.535 32.905 11.865 33.335 ;
        RECT 12.995 32.895 13.165 33.655 ;
        RECT 13.430 33.795 13.660 34.535 ;
        RECT 14.300 34.285 14.470 34.685 ;
        RECT 14.875 34.555 15.885 34.725 ;
        RECT 16.340 34.645 16.510 35.015 ;
        RECT 16.340 34.475 17.345 34.645 ;
        RECT 17.515 34.535 17.855 35.045 ;
        RECT 16.340 34.385 16.510 34.475 ;
        RECT 13.830 34.115 14.470 34.285 ;
        RECT 13.430 32.945 13.765 33.795 ;
        RECT 14.300 33.425 14.470 34.115 ;
        RECT 14.640 34.215 16.510 34.385 ;
        RECT 17.175 34.365 17.345 34.475 ;
        RECT 14.640 34.035 14.810 34.215 ;
        RECT 16.700 34.045 16.925 34.305 ;
        RECT 15.190 33.705 15.495 34.015 ;
        RECT 15.675 33.875 16.925 34.045 ;
        RECT 16.700 33.745 16.925 33.875 ;
        RECT 17.175 34.035 17.500 34.365 ;
        RECT 15.190 33.535 16.505 33.705 ;
        RECT 17.175 33.575 17.345 34.035 ;
        RECT 17.670 33.915 17.855 34.535 ;
        RECT 18.660 34.475 18.990 35.105 ;
        RECT 18.260 34.045 18.590 34.285 ;
        RECT 17.625 33.795 17.855 33.915 ;
        RECT 18.760 33.875 18.990 34.475 ;
        RECT 19.920 34.475 20.615 35.105 ;
        RECT 21.300 34.475 21.995 35.105 ;
        RECT 22.800 34.475 23.130 35.105 ;
        RECT 19.415 34.035 19.750 34.305 ;
        RECT 19.920 33.875 20.090 34.475 ;
        RECT 20.260 34.035 20.595 34.285 ;
        RECT 20.795 34.035 21.130 34.305 ;
        RECT 21.300 33.875 21.470 34.475 ;
        RECT 21.640 34.035 21.975 34.285 ;
        RECT 22.400 34.045 22.730 34.285 ;
        RECT 22.900 33.875 23.130 34.475 ;
        RECT 24.060 34.475 24.755 35.105 ;
        RECT 24.060 34.425 24.235 34.475 ;
        RECT 23.555 34.035 23.890 34.305 ;
        RECT 24.060 33.875 24.230 34.425 ;
        RECT 24.400 34.035 24.735 34.285 ;
        RECT 14.300 33.255 15.020 33.425 ;
        RECT 14.850 33.005 15.020 33.255 ;
        RECT 15.190 32.985 15.495 33.535 ;
        RECT 16.690 33.405 17.345 33.575 ;
        RECT 16.690 33.005 16.860 33.405 ;
        RECT 17.515 32.945 17.855 33.795 ;
        RECT 18.660 32.895 18.990 33.875 ;
        RECT 19.855 32.895 20.185 33.875 ;
        RECT 21.235 32.895 21.565 33.875 ;
        RECT 22.800 32.895 23.130 33.875 ;
        RECT 23.995 32.895 24.325 33.875 ;
        RECT 8.355 31.405 8.685 32.385 ;
        RECT 9.735 31.405 10.065 32.385 ;
        RECT 7.915 30.975 8.250 31.245 ;
        RECT 8.420 30.805 8.590 31.405 ;
        RECT 8.760 30.995 9.095 31.245 ;
        RECT 9.295 30.975 9.630 31.245 ;
        RECT 9.800 30.805 9.970 31.405 ;
        RECT 10.665 31.265 10.935 32.365 ;
        RECT 11.105 31.625 11.380 32.130 ;
        RECT 11.105 31.455 11.595 31.625 ;
        RECT 12.050 31.545 12.375 32.385 ;
        RECT 10.140 30.995 10.475 31.245 ;
        RECT 10.665 30.915 11.115 31.265 ;
        RECT 11.300 30.915 11.595 31.455 ;
        RECT 11.765 31.375 12.375 31.545 ;
        RECT 18.915 31.585 19.245 32.385 ;
        RECT 19.785 31.585 20.115 32.385 ;
        RECT 21.215 31.585 21.545 32.385 ;
        RECT 22.115 31.585 22.445 32.385 ;
        RECT 18.915 31.415 20.195 31.585 ;
        RECT 8.420 30.175 9.115 30.805 ;
        RECT 9.800 30.175 10.495 30.805 ;
        RECT 11.300 30.745 11.470 30.915 ;
        RECT 11.765 30.745 11.935 31.375 ;
        RECT 12.105 30.995 12.605 31.205 ;
        RECT 12.775 30.995 13.255 31.205 ;
        RECT 18.510 30.915 18.795 31.245 ;
        RECT 18.995 30.915 19.375 31.245 ;
        RECT 19.545 30.915 19.855 31.245 ;
        RECT 11.160 30.575 11.470 30.745 ;
        RECT 11.160 30.415 11.350 30.575 ;
        RECT 11.695 30.565 11.935 30.745 ;
        RECT 12.150 30.655 13.245 30.825 ;
        RECT 11.695 30.175 11.865 30.565 ;
        RECT 12.150 30.405 12.320 30.655 ;
        RECT 12.070 30.175 12.400 30.405 ;
        RECT 12.915 30.190 13.245 30.655 ;
        RECT 18.995 30.220 19.210 30.915 ;
        RECT 19.545 30.745 19.750 30.915 ;
        RECT 20.025 30.745 20.195 31.415 ;
        RECT 20.375 30.915 20.615 31.585 ;
        RECT 21.215 31.415 22.445 31.585 ;
        RECT 19.400 30.220 19.750 30.745 ;
        RECT 19.920 30.175 20.615 30.745 ;
        RECT 20.810 30.665 21.030 31.245 ;
        RECT 21.215 30.515 21.395 31.415 ;
        RECT 21.565 30.685 21.940 31.245 ;
        RECT 22.145 30.915 22.455 31.245 ;
        RECT 22.115 30.515 22.445 30.745 ;
        RECT 21.215 30.175 22.445 30.515 ;
        RECT 9.800 29.035 10.495 29.665 ;
        RECT 19.385 29.035 19.715 29.665 ;
        RECT 20.755 29.325 21.985 29.665 ;
        RECT 9.295 28.595 9.630 28.865 ;
        RECT 9.800 28.435 9.970 29.035 ;
        RECT 10.140 28.595 10.475 28.845 ;
        RECT 18.965 28.595 19.295 28.845 ;
        RECT 19.465 28.435 19.715 29.035 ;
        RECT 20.350 28.595 20.570 29.175 ;
        RECT 9.735 27.455 10.065 28.435 ;
        RECT 19.385 27.455 19.715 28.435 ;
        RECT 20.755 28.425 20.935 29.325 ;
        RECT 21.105 28.595 21.480 29.155 ;
        RECT 21.655 29.095 21.985 29.325 ;
        RECT 21.685 28.595 21.995 28.925 ;
        RECT 20.755 28.255 21.985 28.425 ;
        RECT 20.755 27.455 21.085 28.255 ;
        RECT 21.655 27.455 21.985 28.255 ;
        RECT 9.815 26.110 10.070 26.915 ;
        RECT 10.670 26.110 10.930 26.915 ;
        RECT 13.430 26.775 14.510 26.930 ;
        RECT 13.430 26.760 14.575 26.775 ;
        RECT 9.815 25.940 11.415 26.110 ;
        RECT 13.430 25.975 13.765 26.760 ;
        RECT 14.340 26.605 14.575 26.760 ;
        RECT 9.745 25.545 10.965 25.770 ;
        RECT 11.135 25.375 11.415 25.940 ;
        RECT 13.935 25.805 14.170 26.485 ;
        RECT 14.340 26.145 14.510 26.605 ;
        RECT 16.655 26.165 16.930 26.935 ;
        RECT 17.100 26.505 17.430 26.935 ;
        RECT 17.975 26.505 18.305 26.935 ;
        RECT 17.100 26.335 18.305 26.505 ;
        RECT 14.340 25.975 14.655 26.145 ;
        RECT 13.430 25.475 13.765 25.805 ;
        RECT 13.935 25.475 14.315 25.805 ;
        RECT 10.685 25.205 11.415 25.375 ;
        RECT 14.485 25.305 14.655 25.975 ;
        RECT 10.685 24.760 10.910 25.205 ;
        RECT 13.430 25.135 14.655 25.305 ;
        RECT 14.825 25.135 15.095 26.145 ;
        RECT 16.655 25.975 17.240 26.165 ;
        RECT 17.410 26.005 18.305 26.335 ;
        RECT 16.655 25.155 16.895 25.805 ;
        RECT 17.065 25.305 17.240 25.975 ;
        RECT 19.120 25.965 19.450 26.945 ;
        RECT 17.410 25.475 17.825 25.805 ;
        RECT 18.005 25.475 18.300 25.805 ;
        RECT 18.720 25.555 19.050 25.795 ;
        RECT 13.430 24.865 13.685 25.135 ;
        RECT 14.355 24.865 14.525 25.135 ;
        RECT 17.065 25.125 17.395 25.305 ;
        RECT 17.170 24.745 17.395 25.125 ;
        RECT 17.595 24.855 17.825 25.475 ;
        RECT 19.220 25.365 19.450 25.965 ;
        RECT 19.120 24.735 19.450 25.365 ;
        RECT 14.060 23.595 14.390 24.225 ;
        RECT 16.190 23.865 16.480 24.215 ;
        RECT 17.175 23.865 17.405 24.170 ;
        RECT 16.190 23.695 17.405 23.865 ;
        RECT 13.660 23.165 13.990 23.405 ;
        RECT 14.160 22.995 14.390 23.595 ;
        RECT 17.595 23.525 17.765 24.090 ;
        RECT 18.455 23.885 19.685 24.225 ;
        RECT 16.250 23.375 16.510 23.485 ;
        RECT 16.245 23.205 16.510 23.375 ;
        RECT 16.250 23.155 16.510 23.205 ;
        RECT 16.690 23.155 17.075 23.485 ;
        RECT 17.245 23.355 17.765 23.525 ;
        RECT 14.060 22.015 14.390 22.995 ;
        RECT 16.690 22.105 16.885 23.155 ;
        RECT 17.245 22.975 17.415 23.355 ;
        RECT 17.065 22.695 17.415 22.975 ;
        RECT 17.605 22.825 17.850 23.185 ;
        RECT 18.050 23.155 18.270 23.735 ;
        RECT 18.455 22.985 18.635 23.885 ;
        RECT 18.805 23.155 19.180 23.715 ;
        RECT 19.355 23.655 19.685 23.885 ;
        RECT 19.385 23.155 19.695 23.485 ;
        RECT 18.455 22.815 19.685 22.985 ;
        RECT 17.065 22.015 17.395 22.695 ;
        RECT 18.455 22.015 18.785 22.815 ;
        RECT 19.355 22.015 19.685 22.815 ;
        RECT 8.540 20.525 8.870 21.505 ;
        RECT 9.735 20.525 10.065 21.505 ;
        RECT 16.635 20.525 16.965 21.505 ;
        RECT 18.015 20.525 18.345 21.505 ;
        RECT 19.395 20.525 19.725 21.505 ;
        RECT 20.775 20.525 21.105 21.505 ;
        RECT 23.075 20.525 23.405 21.505 ;
        RECT 8.140 20.115 8.470 20.355 ;
        RECT 8.640 19.925 8.870 20.525 ;
        RECT 9.800 20.485 9.975 20.525 ;
        RECT 16.700 20.485 16.875 20.525 ;
        RECT 9.295 20.095 9.630 20.365 ;
        RECT 8.540 19.295 8.870 19.925 ;
        RECT 9.800 19.925 9.970 20.485 ;
        RECT 10.140 20.115 10.475 20.365 ;
        RECT 16.195 20.095 16.530 20.365 ;
        RECT 16.700 19.925 16.870 20.485 ;
        RECT 17.040 20.115 17.375 20.365 ;
        RECT 17.575 20.095 17.910 20.365 ;
        RECT 18.080 19.925 18.250 20.525 ;
        RECT 19.460 20.485 19.635 20.525 ;
        RECT 18.420 20.115 18.755 20.365 ;
        RECT 18.955 20.095 19.290 20.365 ;
        RECT 19.460 19.925 19.630 20.485 ;
        RECT 19.800 20.115 20.135 20.365 ;
        RECT 20.335 20.095 20.670 20.365 ;
        RECT 20.840 19.925 21.010 20.525 ;
        RECT 21.180 20.115 21.515 20.365 ;
        RECT 22.635 20.095 22.970 20.365 ;
        RECT 23.140 19.975 23.310 20.525 ;
        RECT 23.480 20.115 23.815 20.365 ;
        RECT 23.140 19.925 23.315 19.975 ;
        RECT 9.800 19.295 10.495 19.925 ;
        RECT 16.700 19.295 17.395 19.925 ;
        RECT 18.080 19.295 18.775 19.925 ;
        RECT 19.460 19.295 20.155 19.925 ;
        RECT 20.840 19.295 21.535 19.925 ;
        RECT 23.140 19.295 23.835 19.925 ;
        RECT 9.800 18.155 10.495 18.785 ;
        RECT 17.740 18.155 18.070 18.785 ;
        RECT 9.295 17.715 9.630 17.985 ;
        RECT 9.800 17.555 9.970 18.155 ;
        RECT 10.140 17.715 10.475 17.965 ;
        RECT 17.340 17.725 17.670 17.965 ;
        RECT 17.840 17.555 18.070 18.155 ;
        RECT 9.735 16.575 10.065 17.555 ;
        RECT 17.740 16.575 18.070 17.555 ;
        RECT 9.750 15.880 10.830 16.050 ;
        RECT 9.750 15.095 10.085 15.880 ;
        RECT 10.255 14.925 10.490 15.605 ;
        RECT 10.660 15.265 10.830 15.880 ;
        RECT 11.595 15.265 11.925 16.050 ;
        RECT 17.395 15.645 17.895 16.065 ;
        RECT 10.660 15.095 10.975 15.265 ;
        RECT 9.750 14.595 10.085 14.925 ;
        RECT 10.255 14.595 10.635 14.925 ;
        RECT 10.805 14.425 10.975 15.095 ;
        RECT 9.750 14.255 10.975 14.425 ;
        RECT 11.145 14.255 11.415 15.265 ;
        RECT 11.595 15.095 12.275 15.265 ;
        RECT 11.585 14.675 11.935 14.925 ;
        RECT 12.105 14.495 12.275 15.095 ;
        RECT 12.445 14.675 12.795 14.925 ;
        RECT 9.750 13.985 10.005 14.255 ;
        RECT 10.675 13.985 10.845 14.255 ;
        RECT 12.015 13.855 12.345 14.495 ;
        RECT 16.645 14.265 16.885 15.590 ;
        RECT 17.055 15.435 17.895 15.645 ;
        RECT 17.055 14.425 17.225 15.435 ;
        RECT 17.395 15.015 17.795 15.265 ;
        RECT 18.085 15.215 18.285 16.005 ;
        RECT 17.965 15.045 18.285 15.215 ;
        RECT 19.375 15.265 19.705 16.065 ;
        RECT 20.275 15.265 20.605 16.065 ;
        RECT 19.375 15.095 20.605 15.265 ;
        RECT 17.395 14.595 17.565 15.015 ;
        RECT 17.965 14.845 18.145 15.045 ;
        RECT 17.780 14.675 18.145 14.845 ;
        RECT 18.315 14.675 18.775 14.875 ;
        RECT 17.745 14.425 18.775 14.465 ;
        RECT 17.055 14.245 17.405 14.425 ;
        RECT 17.575 14.295 18.775 14.425 ;
        RECT 18.970 14.345 19.190 14.925 ;
        RECT 17.575 14.075 17.905 14.295 ;
        RECT 16.645 13.895 17.905 14.075 ;
        RECT 18.435 13.880 18.775 14.295 ;
        RECT 19.375 14.195 19.555 15.095 ;
        RECT 19.725 14.365 20.100 14.925 ;
        RECT 20.305 14.595 20.615 14.925 ;
        RECT 20.275 14.195 20.605 14.425 ;
        RECT 19.375 13.855 20.605 14.195 ;
        RECT 9.285 12.885 9.625 13.345 ;
        RECT 10.135 13.135 11.305 13.345 ;
        RECT 10.135 12.885 10.385 13.135 ;
        RECT 10.975 13.115 11.305 13.135 ;
        RECT 9.285 12.715 10.385 12.885 ;
        RECT 10.555 12.695 11.415 12.945 ;
        RECT 9.285 12.275 10.045 12.525 ;
        RECT 10.215 12.275 10.965 12.525 ;
        RECT 11.135 12.105 11.415 12.695 ;
        RECT 17.160 12.715 17.855 13.345 ;
        RECT 18.060 12.985 18.320 13.320 ;
        RECT 18.990 12.985 19.225 13.320 ;
        RECT 18.060 12.815 19.225 12.985 ;
        RECT 17.160 12.665 17.335 12.715 ;
        RECT 16.655 12.275 16.990 12.545 ;
        RECT 17.160 12.115 17.330 12.665 ;
        RECT 19.395 12.645 19.680 13.320 ;
        RECT 20.755 13.005 21.985 13.345 ;
        RECT 17.500 12.275 17.835 12.525 ;
        RECT 9.715 11.935 11.415 12.105 ;
        RECT 9.715 11.135 10.045 11.935 ;
        RECT 10.555 11.135 10.885 11.935 ;
        RECT 17.095 11.135 17.425 12.115 ;
        RECT 18.025 11.985 18.355 12.645 ;
        RECT 18.545 12.260 18.945 12.500 ;
        RECT 19.115 12.475 19.680 12.645 ;
        RECT 18.545 11.955 18.715 12.260 ;
        RECT 19.115 12.090 19.285 12.475 ;
        RECT 20.350 12.275 20.570 12.855 ;
        RECT 18.905 11.920 19.285 12.090 ;
        RECT 18.905 11.135 19.240 11.920 ;
        RECT 19.455 11.915 19.670 12.245 ;
        RECT 20.755 12.105 20.935 13.005 ;
        RECT 21.105 12.275 21.480 12.835 ;
        RECT 21.655 12.775 21.985 13.005 ;
        RECT 21.685 12.275 21.995 12.605 ;
        RECT 20.755 11.935 21.985 12.105 ;
        RECT 20.755 11.135 21.085 11.935 ;
        RECT 21.655 11.135 21.985 11.935 ;
        RECT 9.245 9.840 9.580 10.625 ;
        RECT 8.365 9.115 8.695 9.775 ;
        RECT 8.885 9.500 9.055 9.805 ;
        RECT 9.245 9.670 9.625 9.840 ;
        RECT 8.885 9.260 9.285 9.500 ;
        RECT 9.455 9.285 9.625 9.670 ;
        RECT 9.795 9.515 10.010 9.845 ;
        RECT 11.115 9.645 11.445 10.625 ;
        RECT 12.115 10.115 12.370 10.595 ;
        RECT 12.105 9.945 12.370 10.115 ;
        RECT 12.115 9.790 12.370 9.945 ;
        RECT 12.970 9.790 13.230 10.595 ;
        RECT 9.455 9.115 10.020 9.285 ;
        RECT 10.675 9.215 11.010 9.485 ;
        RECT 8.400 8.775 9.565 8.945 ;
        RECT 8.400 8.440 8.660 8.775 ;
        RECT 9.330 8.440 9.565 8.775 ;
        RECT 9.735 8.440 10.020 9.115 ;
        RECT 11.180 9.095 11.350 9.645 ;
        RECT 12.115 9.620 13.715 9.790 ;
        RECT 17.740 9.645 18.070 10.625 ;
        RECT 11.520 9.235 11.855 9.485 ;
        RECT 12.045 9.225 13.265 9.450 ;
        RECT 11.180 9.045 11.355 9.095 ;
        RECT 13.435 9.055 13.715 9.620 ;
        RECT 17.340 9.235 17.670 9.475 ;
        RECT 11.180 8.415 11.875 9.045 ;
        RECT 12.985 8.885 13.715 9.055 ;
        RECT 17.840 9.045 18.070 9.645 ;
        RECT 12.985 8.440 13.210 8.885 ;
        RECT 17.740 8.415 18.070 9.045 ;
        RECT 18.945 9.945 19.325 10.625 ;
        RECT 20.255 10.115 20.585 10.625 ;
        RECT 21.095 10.115 21.495 10.625 ;
        RECT 20.255 9.945 21.495 10.115 ;
        RECT 18.945 8.985 19.115 9.945 ;
        RECT 19.285 9.605 20.590 9.775 ;
        RECT 21.675 9.695 21.995 10.625 ;
        RECT 19.285 9.155 19.530 9.605 ;
        RECT 19.700 9.235 20.250 9.435 ;
        RECT 20.420 9.405 20.590 9.605 ;
        RECT 21.365 9.525 21.995 9.695 ;
        RECT 22.615 9.645 22.945 10.625 ;
        RECT 20.420 9.235 20.795 9.405 ;
        RECT 20.965 8.985 21.195 9.485 ;
        RECT 18.945 8.815 21.195 8.985 ;
        RECT 19.495 8.495 19.665 8.815 ;
        RECT 21.365 8.645 21.535 9.525 ;
        RECT 22.175 9.215 22.510 9.485 ;
        RECT 20.580 8.475 21.535 8.645 ;
        RECT 22.680 9.045 22.850 9.645 ;
        RECT 23.020 9.235 23.355 9.485 ;
        RECT 22.680 8.415 23.375 9.045 ;
        RECT 8.420 7.275 9.115 7.905 ;
        RECT 12.680 7.275 13.010 7.905 ;
        RECT 7.915 6.835 8.250 7.105 ;
        RECT 8.420 6.675 8.590 7.275 ;
        RECT 8.760 6.835 9.095 7.085 ;
        RECT 12.280 6.845 12.610 7.085 ;
        RECT 12.780 6.675 13.010 7.275 ;
        RECT 13.940 7.275 14.635 7.905 ;
        RECT 15.780 7.275 16.475 7.905 ;
        RECT 16.645 7.400 16.905 7.905 ;
        RECT 17.595 7.525 17.765 7.905 ;
        RECT 13.435 6.835 13.770 7.105 ;
        RECT 13.940 6.675 14.110 7.275 ;
        RECT 15.780 7.225 15.955 7.275 ;
        RECT 14.280 6.835 14.615 7.085 ;
        RECT 15.275 6.835 15.610 7.105 ;
        RECT 15.780 6.675 15.950 7.225 ;
        RECT 16.120 6.835 16.455 7.085 ;
        RECT 8.355 5.695 8.685 6.675 ;
        RECT 12.680 5.695 13.010 6.675 ;
        RECT 13.875 5.695 14.205 6.675 ;
        RECT 15.715 5.695 16.045 6.675 ;
        RECT 16.645 6.600 16.815 7.400 ;
        RECT 17.100 7.355 17.765 7.525 ;
        RECT 17.100 7.100 17.270 7.355 ;
        RECT 18.660 7.275 18.990 7.905 ;
        RECT 19.440 7.545 19.700 7.880 ;
        RECT 20.370 7.545 20.605 7.880 ;
        RECT 19.440 7.375 20.605 7.545 ;
        RECT 16.985 6.770 17.270 7.100 ;
        RECT 18.260 6.845 18.590 7.085 ;
        RECT 17.100 6.625 17.270 6.770 ;
        RECT 18.760 6.675 18.990 7.275 ;
        RECT 20.775 7.205 21.060 7.880 ;
        RECT 21.675 7.565 22.905 7.905 ;
        RECT 16.645 5.695 16.915 6.600 ;
        RECT 17.100 6.455 17.765 6.625 ;
        RECT 17.595 5.695 17.765 6.455 ;
        RECT 18.660 5.695 18.990 6.675 ;
        RECT 19.405 6.545 19.735 7.205 ;
        RECT 19.925 6.820 20.325 7.060 ;
        RECT 20.495 7.035 21.060 7.205 ;
        RECT 19.925 6.515 20.095 6.820 ;
        RECT 20.495 6.650 20.665 7.035 ;
        RECT 21.270 6.835 21.490 7.415 ;
        RECT 20.285 6.480 20.665 6.650 ;
        RECT 20.285 5.695 20.620 6.480 ;
        RECT 20.835 6.475 21.050 6.805 ;
        RECT 21.675 6.665 21.855 7.565 ;
        RECT 22.025 6.835 22.400 7.395 ;
        RECT 22.575 7.335 22.905 7.565 ;
        RECT 23.600 7.275 24.295 7.905 ;
        RECT 22.605 6.835 22.915 7.165 ;
        RECT 23.095 6.835 23.430 7.105 ;
        RECT 23.600 6.675 23.770 7.275 ;
        RECT 23.940 6.835 24.275 7.085 ;
        RECT 21.675 6.495 22.905 6.665 ;
        RECT 21.675 5.695 22.005 6.495 ;
        RECT 22.575 5.695 22.905 6.495 ;
        RECT 23.535 5.695 23.865 6.675 ;
        RECT 15.725 4.280 15.995 5.185 ;
        RECT 16.675 4.425 16.845 5.185 ;
        RECT 15.725 3.480 15.895 4.280 ;
        RECT 16.180 4.255 16.845 4.425 ;
        RECT 17.105 4.385 17.375 5.155 ;
        RECT 18.080 4.750 18.265 5.155 ;
        RECT 18.080 4.575 18.745 4.750 ;
        RECT 16.180 4.110 16.350 4.255 ;
        RECT 16.065 3.780 16.350 4.110 ;
        RECT 16.180 3.525 16.350 3.780 ;
        RECT 17.105 4.215 18.235 4.385 ;
        RECT 15.725 2.975 15.985 3.480 ;
        RECT 16.180 3.355 16.845 3.525 ;
        RECT 16.675 2.975 16.845 3.355 ;
        RECT 17.105 3.305 17.275 4.215 ;
        RECT 17.985 3.715 18.235 4.215 ;
        RECT 18.405 3.545 18.745 4.575 ;
        RECT 18.060 3.375 18.745 3.545 ;
        RECT 18.945 4.385 19.215 5.155 ;
        RECT 19.920 4.750 20.105 5.155 ;
        RECT 19.920 4.575 20.585 4.750 ;
        RECT 18.945 4.215 20.075 4.385 ;
        RECT 17.105 2.975 17.365 3.305 ;
        RECT 18.060 2.975 18.265 3.375 ;
        RECT 18.945 3.305 19.115 4.215 ;
        RECT 19.825 3.715 20.075 4.215 ;
        RECT 20.245 3.545 20.585 4.575 ;
        RECT 19.900 3.375 20.585 3.545 ;
        RECT 20.785 4.385 21.055 5.155 ;
        RECT 21.760 4.750 21.945 5.155 ;
        RECT 24.465 4.760 24.900 5.185 ;
        RECT 21.760 4.575 22.425 4.750 ;
        RECT 24.465 4.590 25.455 4.760 ;
        RECT 20.785 4.215 21.915 4.385 ;
        RECT 18.945 2.975 19.205 3.305 ;
        RECT 19.900 2.975 20.105 3.375 ;
        RECT 20.785 3.305 20.955 4.215 ;
        RECT 21.665 3.715 21.915 4.215 ;
        RECT 22.085 3.545 22.425 4.575 ;
        RECT 25.120 4.045 25.455 4.590 ;
        RECT 25.625 4.395 26.050 5.185 ;
        RECT 26.220 4.760 26.495 5.185 ;
        RECT 26.220 4.565 27.050 4.760 ;
        RECT 25.625 4.215 26.530 4.395 ;
        RECT 25.120 3.715 25.530 4.045 ;
        RECT 25.700 3.715 26.530 4.215 ;
        RECT 26.700 4.045 27.050 4.565 ;
        RECT 27.220 4.395 27.465 5.185 ;
        RECT 27.655 4.760 27.910 5.185 ;
        RECT 27.655 4.565 28.465 4.760 ;
        RECT 27.220 4.215 27.945 4.395 ;
        RECT 26.700 3.715 27.125 4.045 ;
        RECT 27.295 3.715 27.945 4.215 ;
        RECT 28.115 4.045 28.465 4.565 ;
        RECT 28.635 4.215 28.895 5.185 ;
        RECT 28.115 3.715 28.540 4.045 ;
        RECT 25.120 3.545 25.455 3.715 ;
        RECT 25.700 3.545 26.050 3.715 ;
        RECT 26.700 3.545 27.050 3.715 ;
        RECT 27.295 3.545 27.465 3.715 ;
        RECT 28.115 3.545 28.465 3.715 ;
        RECT 28.710 3.545 28.895 4.215 ;
        RECT 21.740 3.375 22.425 3.545 ;
        RECT 24.465 3.375 25.455 3.545 ;
        RECT 20.785 2.975 21.045 3.305 ;
        RECT 21.740 2.975 21.945 3.375 ;
        RECT 24.465 2.975 24.900 3.375 ;
        RECT 25.625 2.975 26.050 3.545 ;
        RECT 26.240 3.375 27.050 3.545 ;
        RECT 26.240 2.975 26.495 3.375 ;
        RECT 27.220 2.975 27.465 3.545 ;
        RECT 27.655 3.375 28.465 3.545 ;
        RECT 27.655 2.975 27.910 3.375 ;
        RECT 28.635 2.975 28.895 3.545 ;
      LAYER mcon ;
        RECT 6.585 36.465 6.755 36.635 ;
        RECT 7.965 36.465 8.135 36.635 ;
        RECT 9.345 36.465 9.515 36.635 ;
        RECT 10.725 36.465 10.895 36.635 ;
        RECT 12.105 36.465 12.275 36.635 ;
        RECT 12.740 36.465 12.910 36.635 ;
        RECT 13.255 36.465 13.425 36.635 ;
        RECT 14.865 36.465 15.035 36.635 ;
        RECT 16.705 36.465 16.875 36.635 ;
        RECT 18.085 36.465 18.255 36.635 ;
        RECT 19.465 36.465 19.635 36.635 ;
        RECT 20.845 36.465 21.015 36.635 ;
        RECT 22.225 36.465 22.395 36.635 ;
        RECT 8.195 34.765 8.365 34.935 ;
        RECT 7.840 34.085 8.010 34.255 ;
        RECT 9.345 34.765 9.515 34.935 ;
        RECT 8.885 34.085 9.055 34.255 ;
        RECT 10.265 34.425 10.435 34.595 ;
        RECT 9.805 34.085 9.975 34.255 ;
        RECT 11.185 34.425 11.355 34.595 ;
        RECT 13.485 34.765 13.655 34.935 ;
        RECT 11.645 34.085 11.815 34.255 ;
        RECT 13.025 34.085 13.195 34.255 ;
        RECT 10.265 33.065 10.435 33.235 ;
        RECT 16.705 33.745 16.875 33.915 ;
        RECT 18.775 34.765 18.945 34.935 ;
        RECT 18.420 34.085 18.590 34.255 ;
        RECT 15.325 33.065 15.495 33.235 ;
        RECT 17.625 33.745 17.795 33.915 ;
        RECT 19.925 34.765 20.095 34.935 ;
        RECT 21.305 34.765 21.475 34.935 ;
        RECT 19.465 34.085 19.635 34.255 ;
        RECT 20.385 34.085 20.555 34.255 ;
        RECT 20.845 34.085 21.015 34.255 ;
        RECT 21.765 34.085 21.935 34.255 ;
        RECT 22.400 34.085 22.570 34.255 ;
        RECT 24.065 34.425 24.235 34.595 ;
        RECT 22.915 34.085 23.085 34.255 ;
        RECT 23.605 34.085 23.775 34.255 ;
        RECT 24.525 34.085 24.695 34.255 ;
        RECT 8.425 32.045 8.595 32.215 ;
        RECT 9.805 32.045 9.975 32.215 ;
        RECT 7.965 31.025 8.135 31.195 ;
        RECT 8.885 31.025 9.055 31.195 ;
        RECT 9.345 31.025 9.515 31.195 ;
        RECT 10.725 31.365 10.895 31.535 ;
        RECT 12.105 32.045 12.275 32.215 ;
        RECT 10.265 31.025 10.435 31.195 ;
        RECT 19.925 32.045 20.095 32.215 ;
        RECT 22.225 32.045 22.395 32.215 ;
        RECT 12.105 31.025 12.275 31.195 ;
        RECT 13.025 31.025 13.195 31.195 ;
        RECT 18.545 31.025 18.715 31.195 ;
        RECT 19.005 30.685 19.175 30.855 ;
        RECT 20.385 31.025 20.555 31.195 ;
        RECT 19.465 30.345 19.635 30.515 ;
        RECT 20.845 30.685 21.015 30.855 ;
        RECT 22.225 31.025 22.395 31.195 ;
        RECT 21.765 30.685 21.935 30.855 ;
        RECT 9.805 29.325 9.975 29.495 ;
        RECT 20.845 29.325 21.015 29.495 ;
        RECT 9.345 28.645 9.515 28.815 ;
        RECT 10.265 28.645 10.435 28.815 ;
        RECT 19.005 28.645 19.175 28.815 ;
        RECT 20.385 28.645 20.555 28.815 ;
        RECT 19.465 27.625 19.635 27.795 ;
        RECT 21.305 28.645 21.475 28.815 ;
        RECT 21.765 28.645 21.935 28.815 ;
        RECT 10.725 26.605 10.895 26.775 ;
        RECT 14.405 26.605 14.575 26.775 ;
        RECT 16.705 26.605 16.875 26.775 ;
        RECT 13.945 26.265 14.115 26.435 ;
        RECT 10.725 25.585 10.895 25.755 ;
        RECT 13.510 25.585 13.680 25.755 ;
        RECT 19.235 26.605 19.405 26.775 ;
        RECT 14.865 25.245 15.035 25.415 ;
        RECT 16.705 25.585 16.875 25.755 ;
        RECT 18.085 25.585 18.255 25.755 ;
        RECT 18.720 25.585 18.890 25.755 ;
        RECT 17.625 24.905 17.795 25.075 ;
        RECT 14.175 23.545 14.345 23.715 ;
        RECT 13.740 23.205 13.910 23.375 ;
        RECT 18.545 23.885 18.715 24.055 ;
        RECT 16.705 22.865 16.875 23.035 ;
        RECT 18.085 23.205 18.255 23.375 ;
        RECT 17.625 22.865 17.795 23.035 ;
        RECT 19.005 23.205 19.175 23.375 ;
        RECT 19.465 23.205 19.635 23.375 ;
        RECT 17.165 22.525 17.335 22.695 ;
        RECT 8.140 20.145 8.310 20.315 ;
        RECT 9.805 20.485 9.975 20.655 ;
        RECT 16.705 20.485 16.875 20.655 ;
        RECT 18.085 21.165 18.255 21.335 ;
        RECT 8.655 20.145 8.825 20.315 ;
        RECT 9.345 20.145 9.515 20.315 ;
        RECT 10.265 20.145 10.435 20.315 ;
        RECT 16.245 20.145 16.415 20.315 ;
        RECT 17.165 20.145 17.335 20.315 ;
        RECT 17.625 20.145 17.795 20.315 ;
        RECT 19.465 20.485 19.635 20.655 ;
        RECT 18.545 20.145 18.715 20.315 ;
        RECT 19.005 20.145 19.175 20.315 ;
        RECT 19.925 20.145 20.095 20.315 ;
        RECT 20.385 20.145 20.555 20.315 ;
        RECT 21.305 20.145 21.475 20.315 ;
        RECT 22.685 20.145 22.855 20.315 ;
        RECT 23.605 20.145 23.775 20.315 ;
        RECT 21.305 19.465 21.475 19.635 ;
        RECT 23.145 19.805 23.315 19.975 ;
        RECT 9.805 18.445 9.975 18.615 ;
        RECT 17.855 18.445 18.025 18.615 ;
        RECT 9.345 17.765 9.515 17.935 ;
        RECT 10.265 17.765 10.435 17.935 ;
        RECT 17.500 17.765 17.670 17.935 ;
        RECT 9.805 15.725 9.975 15.895 ;
        RECT 10.265 15.385 10.435 15.555 ;
        RECT 11.645 15.725 11.815 15.895 ;
        RECT 17.625 15.725 17.795 15.895 ;
        RECT 9.805 14.705 9.975 14.875 ;
        RECT 11.645 14.705 11.815 14.875 ;
        RECT 11.185 14.365 11.355 14.535 ;
        RECT 16.705 15.045 16.875 15.215 ;
        RECT 12.565 14.705 12.735 14.875 ;
        RECT 17.625 15.045 17.795 15.215 ;
        RECT 18.085 15.045 18.255 15.215 ;
        RECT 19.465 15.725 19.635 15.895 ;
        RECT 18.545 14.705 18.715 14.875 ;
        RECT 19.005 14.365 19.175 14.535 ;
        RECT 20.385 14.705 20.555 14.875 ;
        RECT 19.925 14.365 20.095 14.535 ;
        RECT 9.345 12.325 9.515 12.495 ;
        RECT 10.265 12.325 10.435 12.495 ;
        RECT 17.165 12.665 17.335 12.835 ;
        RECT 19.465 13.005 19.635 13.175 ;
        RECT 16.705 12.325 16.875 12.495 ;
        RECT 11.185 11.985 11.355 12.155 ;
        RECT 20.845 13.005 21.015 13.175 ;
        RECT 17.625 12.325 17.795 12.495 ;
        RECT 18.085 11.985 18.255 12.155 ;
        RECT 18.545 11.985 18.715 12.155 ;
        RECT 20.385 12.325 20.555 12.495 ;
        RECT 19.465 11.985 19.635 12.155 ;
        RECT 21.305 12.325 21.475 12.495 ;
        RECT 21.765 12.325 21.935 12.495 ;
        RECT 9.345 10.285 9.515 10.455 ;
        RECT 8.425 9.265 8.595 9.435 ;
        RECT 8.885 9.265 9.055 9.435 ;
        RECT 9.805 9.605 9.975 9.775 ;
        RECT 12.105 9.945 12.275 10.115 ;
        RECT 17.855 10.285 18.025 10.455 ;
        RECT 10.725 9.265 10.895 9.435 ;
        RECT 11.645 9.265 11.815 9.435 ;
        RECT 13.025 9.265 13.195 9.435 ;
        RECT 11.185 8.925 11.355 9.095 ;
        RECT 17.340 9.265 17.510 9.435 ;
        RECT 19.465 9.605 19.635 9.775 ;
        RECT 19.925 9.265 20.095 9.435 ;
        RECT 21.765 9.605 21.935 9.775 ;
        RECT 22.685 10.285 22.855 10.455 ;
        RECT 22.225 9.265 22.395 9.435 ;
        RECT 23.145 9.265 23.315 9.435 ;
        RECT 8.425 7.565 8.595 7.735 ;
        RECT 7.965 6.885 8.135 7.055 ;
        RECT 8.885 6.885 9.055 7.055 ;
        RECT 12.280 6.885 12.450 7.055 ;
        RECT 14.405 7.565 14.575 7.735 ;
        RECT 12.795 6.885 12.965 7.055 ;
        RECT 13.485 6.885 13.655 7.055 ;
        RECT 15.785 7.225 15.955 7.395 ;
        RECT 14.405 6.885 14.575 7.055 ;
        RECT 15.325 6.885 15.495 7.055 ;
        RECT 16.245 6.885 16.415 7.055 ;
        RECT 21.765 7.565 21.935 7.735 ;
        RECT 18.420 6.885 18.590 7.055 ;
        RECT 20.845 7.225 21.015 7.395 ;
        RECT 16.705 6.205 16.875 6.375 ;
        RECT 19.465 6.885 19.635 7.055 ;
        RECT 19.925 6.545 20.095 6.715 ;
        RECT 21.305 6.885 21.475 7.055 ;
        RECT 18.775 6.205 18.945 6.375 ;
        RECT 20.845 6.545 21.015 6.715 ;
        RECT 23.605 7.565 23.775 7.735 ;
        RECT 22.225 6.885 22.395 7.055 ;
        RECT 22.685 6.885 22.855 7.055 ;
        RECT 23.145 6.885 23.315 7.055 ;
        RECT 24.065 6.885 24.235 7.055 ;
        RECT 15.785 4.845 15.955 5.015 ;
        RECT 18.545 4.505 18.715 4.675 ;
        RECT 19.925 4.845 20.095 5.015 ;
        RECT 21.765 4.845 21.935 5.015 ;
        RECT 25.905 4.165 26.075 4.335 ;
      LAYER met1 ;
        RECT 6.510 36.620 6.830 36.680 ;
        RECT 6.315 36.480 6.830 36.620 ;
        RECT 6.510 36.420 6.830 36.480 ;
        RECT 7.905 36.620 8.195 36.665 ;
        RECT 8.350 36.620 8.670 36.680 ;
        RECT 9.270 36.620 9.590 36.680 ;
        RECT 7.905 36.480 8.670 36.620 ;
        RECT 9.075 36.480 9.590 36.620 ;
        RECT 7.905 36.435 8.195 36.480 ;
        RECT 8.350 36.420 8.670 36.480 ;
        RECT 9.270 36.420 9.590 36.480 ;
        RECT 10.190 36.620 10.510 36.680 ;
        RECT 10.665 36.620 10.955 36.665 ;
        RECT 12.030 36.620 12.350 36.680 ;
        RECT 10.190 36.480 10.955 36.620 ;
        RECT 11.835 36.480 12.350 36.620 ;
        RECT 10.190 36.420 10.510 36.480 ;
        RECT 10.665 36.435 10.955 36.480 ;
        RECT 12.030 36.420 12.350 36.480 ;
        RECT 12.490 36.665 12.810 36.680 ;
        RECT 12.490 36.435 12.970 36.665 ;
        RECT 13.195 36.620 13.485 36.665 ;
        RECT 14.805 36.620 15.095 36.665 ;
        RECT 13.195 36.480 15.095 36.620 ;
        RECT 13.195 36.435 13.485 36.480 ;
        RECT 14.805 36.435 15.095 36.480 ;
        RECT 16.645 36.435 16.935 36.665 ;
        RECT 18.010 36.620 18.330 36.680 ;
        RECT 17.815 36.480 18.330 36.620 ;
        RECT 12.490 36.420 12.810 36.435 ;
        RECT 16.720 36.280 16.860 36.435 ;
        RECT 18.010 36.420 18.330 36.480 ;
        RECT 19.405 36.620 19.695 36.665 ;
        RECT 19.850 36.620 20.170 36.680 ;
        RECT 19.405 36.480 20.170 36.620 ;
        RECT 19.405 36.435 19.695 36.480 ;
        RECT 19.850 36.420 20.170 36.480 ;
        RECT 20.785 36.620 21.075 36.665 ;
        RECT 21.230 36.620 21.550 36.680 ;
        RECT 20.785 36.480 21.550 36.620 ;
        RECT 20.785 36.435 21.075 36.480 ;
        RECT 21.230 36.420 21.550 36.480 ;
        RECT 22.165 36.620 22.455 36.665 ;
        RECT 24.450 36.620 24.770 36.680 ;
        RECT 22.165 36.480 24.770 36.620 ;
        RECT 22.165 36.435 22.455 36.480 ;
        RECT 24.450 36.420 24.770 36.480 ;
        RECT 17.550 36.280 17.870 36.340 ;
        RECT 16.720 36.140 17.870 36.280 ;
        RECT 17.550 36.080 17.870 36.140 ;
        RECT 6.510 34.920 6.830 34.980 ;
        RECT 8.135 34.920 8.425 34.965 ;
        RECT 9.270 34.920 9.590 34.980 ;
        RECT 12.490 34.920 12.810 34.980 ;
        RECT 13.425 34.920 13.715 34.965 ;
        RECT 6.510 34.780 8.425 34.920 ;
        RECT 9.075 34.780 9.590 34.920 ;
        RECT 6.510 34.720 6.830 34.780 ;
        RECT 8.135 34.735 8.425 34.780 ;
        RECT 9.270 34.720 9.590 34.780 ;
        RECT 10.280 34.780 12.260 34.920 ;
        RECT 10.280 34.625 10.420 34.780 ;
        RECT 10.205 34.395 10.495 34.625 ;
        RECT 11.125 34.580 11.415 34.625 ;
        RECT 10.740 34.440 11.415 34.580 ;
        RECT 7.780 34.240 8.070 34.285 ;
        RECT 8.350 34.240 8.670 34.300 ;
        RECT 7.780 34.100 8.670 34.240 ;
        RECT 7.780 34.055 8.070 34.100 ;
        RECT 8.350 34.040 8.670 34.100 ;
        RECT 8.825 34.055 9.115 34.285 ;
        RECT 9.270 34.240 9.590 34.300 ;
        RECT 9.745 34.240 10.035 34.285 ;
        RECT 9.270 34.235 10.035 34.240 ;
        RECT 10.740 34.235 10.880 34.440 ;
        RECT 11.125 34.395 11.415 34.440 ;
        RECT 11.585 34.235 11.875 34.285 ;
        RECT 9.270 34.100 10.880 34.235 ;
        RECT 8.900 33.900 9.040 34.055 ;
        RECT 9.270 34.040 9.590 34.100 ;
        RECT 9.745 34.095 10.880 34.100 ;
        RECT 11.200 34.095 11.875 34.235 ;
        RECT 12.120 34.240 12.260 34.780 ;
        RECT 12.490 34.780 13.715 34.920 ;
        RECT 12.490 34.720 12.810 34.780 ;
        RECT 13.425 34.735 13.715 34.780 ;
        RECT 18.010 34.920 18.330 34.980 ;
        RECT 18.715 34.920 19.005 34.965 ;
        RECT 19.850 34.920 20.170 34.980 ;
        RECT 21.230 34.920 21.550 34.980 ;
        RECT 18.010 34.780 19.005 34.920 ;
        RECT 19.655 34.780 20.170 34.920 ;
        RECT 21.035 34.780 21.550 34.920 ;
        RECT 18.010 34.720 18.330 34.780 ;
        RECT 18.715 34.735 19.005 34.780 ;
        RECT 19.850 34.720 20.170 34.780 ;
        RECT 21.230 34.720 21.550 34.780 ;
        RECT 24.005 34.580 24.295 34.625 ;
        RECT 21.780 34.440 24.295 34.580 ;
        RECT 12.965 34.240 13.255 34.285 ;
        RECT 13.410 34.240 13.730 34.300 ;
        RECT 18.470 34.285 18.790 34.300 ;
        RECT 18.360 34.240 18.790 34.285 ;
        RECT 19.405 34.240 19.695 34.285 ;
        RECT 20.310 34.240 20.630 34.300 ;
        RECT 21.780 34.285 21.920 34.440 ;
        RECT 24.005 34.395 24.295 34.440 ;
        RECT 20.785 34.240 21.075 34.285 ;
        RECT 12.120 34.100 13.730 34.240 ;
        RECT 18.035 34.100 19.695 34.240 ;
        RECT 20.115 34.100 21.075 34.240 ;
        RECT 9.745 34.055 10.035 34.095 ;
        RECT 11.200 33.900 11.340 34.095 ;
        RECT 11.585 34.055 11.875 34.095 ;
        RECT 12.965 34.055 13.255 34.100 ;
        RECT 13.410 34.040 13.730 34.100 ;
        RECT 18.360 34.055 18.790 34.100 ;
        RECT 19.405 34.055 19.695 34.100 ;
        RECT 18.470 34.040 18.790 34.055 ;
        RECT 20.310 34.040 20.630 34.100 ;
        RECT 20.785 34.055 21.075 34.100 ;
        RECT 21.705 34.055 21.995 34.285 ;
        RECT 22.340 34.240 22.630 34.285 ;
        RECT 22.240 34.055 22.630 34.240 ;
        RECT 22.855 34.240 23.145 34.285 ;
        RECT 23.545 34.240 23.835 34.285 ;
        RECT 24.450 34.240 24.770 34.300 ;
        RECT 22.855 34.100 23.835 34.240 ;
        RECT 24.255 34.100 24.770 34.240 ;
        RECT 22.855 34.055 23.145 34.100 ;
        RECT 23.545 34.055 23.835 34.100 ;
        RECT 16.630 33.900 16.950 33.960 ;
        RECT 8.900 33.760 11.340 33.900 ;
        RECT 16.435 33.760 16.950 33.900 ;
        RECT 9.820 33.620 9.960 33.760 ;
        RECT 16.630 33.700 16.950 33.760 ;
        RECT 17.565 33.900 17.855 33.945 ;
        RECT 22.240 33.900 22.380 34.055 ;
        RECT 24.450 34.040 24.770 34.100 ;
        RECT 17.565 33.760 22.380 33.900 ;
        RECT 17.565 33.715 17.855 33.760 ;
        RECT 9.730 33.360 10.050 33.620 ;
        RECT 10.205 33.220 10.495 33.265 ;
        RECT 15.250 33.220 15.570 33.280 ;
        RECT 10.205 33.080 15.570 33.220 ;
        RECT 10.205 33.035 10.495 33.080 ;
        RECT 15.250 33.020 15.570 33.080 ;
        RECT 8.350 32.200 8.670 32.260 ;
        RECT 9.730 32.200 10.050 32.260 ;
        RECT 12.030 32.200 12.350 32.260 ;
        RECT 8.155 32.060 8.670 32.200 ;
        RECT 9.535 32.060 10.050 32.200 ;
        RECT 11.835 32.060 12.350 32.200 ;
        RECT 8.350 32.000 8.670 32.060 ;
        RECT 9.730 32.000 10.050 32.060 ;
        RECT 12.030 32.000 12.350 32.060 ;
        RECT 19.865 32.200 20.155 32.245 ;
        RECT 20.310 32.200 20.630 32.260 ;
        RECT 19.865 32.060 20.630 32.200 ;
        RECT 19.865 32.015 20.155 32.060 ;
        RECT 20.310 32.000 20.630 32.060 ;
        RECT 22.165 32.200 22.455 32.245 ;
        RECT 24.450 32.200 24.770 32.260 ;
        RECT 22.165 32.060 24.770 32.200 ;
        RECT 22.165 32.015 22.455 32.060 ;
        RECT 24.450 32.000 24.770 32.060 ;
        RECT 9.270 31.660 9.590 31.920 ;
        RECT 9.360 31.520 9.500 31.660 ;
        RECT 8.900 31.380 9.500 31.520 ;
        RECT 10.665 31.520 10.955 31.565 ;
        RECT 10.665 31.380 15.480 31.520 ;
        RECT 7.890 31.180 8.210 31.240 ;
        RECT 8.900 31.225 9.040 31.380 ;
        RECT 10.665 31.335 10.955 31.380 ;
        RECT 15.340 31.240 15.480 31.380 ;
        RECT 7.695 31.040 8.210 31.180 ;
        RECT 7.890 30.980 8.210 31.040 ;
        RECT 8.825 30.995 9.115 31.225 ;
        RECT 9.285 30.995 9.575 31.225 ;
        RECT 9.730 31.180 10.050 31.240 ;
        RECT 10.205 31.180 10.495 31.225 ;
        RECT 12.045 31.180 12.335 31.225 ;
        RECT 12.950 31.180 13.270 31.240 ;
        RECT 9.730 31.040 10.495 31.180 ;
        RECT 9.360 30.500 9.500 30.995 ;
        RECT 9.730 30.980 10.050 31.040 ;
        RECT 10.205 30.995 10.495 31.040 ;
        RECT 11.660 31.040 12.335 31.180 ;
        RECT 12.755 31.040 13.270 31.180 ;
        RECT 10.650 30.500 10.970 30.560 ;
        RECT 11.660 30.500 11.800 31.040 ;
        RECT 12.045 30.995 12.335 31.040 ;
        RECT 12.950 30.980 13.270 31.040 ;
        RECT 15.250 31.180 15.570 31.240 ;
        RECT 18.485 31.180 18.775 31.225 ;
        RECT 15.250 31.040 18.775 31.180 ;
        RECT 15.250 30.980 15.570 31.040 ;
        RECT 18.485 30.995 18.775 31.040 ;
        RECT 20.325 31.180 20.615 31.225 ;
        RECT 21.230 31.180 21.550 31.240 ;
        RECT 22.165 31.180 22.455 31.225 ;
        RECT 20.325 31.040 22.455 31.180 ;
        RECT 20.325 30.995 20.615 31.040 ;
        RECT 21.230 30.980 21.550 31.040 ;
        RECT 22.165 30.995 22.455 31.040 ;
        RECT 16.630 30.840 16.950 30.900 ;
        RECT 18.930 30.840 19.250 30.900 ;
        RECT 20.770 30.840 21.090 30.900 ;
        RECT 16.630 30.700 19.250 30.840 ;
        RECT 20.575 30.700 21.090 30.840 ;
        RECT 16.630 30.640 16.950 30.700 ;
        RECT 18.930 30.640 19.250 30.700 ;
        RECT 20.770 30.640 21.090 30.700 ;
        RECT 21.705 30.655 21.995 30.885 ;
        RECT 9.360 30.360 11.800 30.500 ;
        RECT 19.390 30.500 19.710 30.560 ;
        RECT 21.780 30.500 21.920 30.655 ;
        RECT 19.390 30.360 21.920 30.500 ;
        RECT 10.650 30.300 10.970 30.360 ;
        RECT 19.390 30.300 19.710 30.360 ;
        RECT 9.270 29.480 9.590 29.540 ;
        RECT 9.745 29.480 10.035 29.525 ;
        RECT 20.770 29.480 21.090 29.540 ;
        RECT 9.270 29.340 10.035 29.480 ;
        RECT 20.575 29.340 21.090 29.480 ;
        RECT 9.270 29.280 9.590 29.340 ;
        RECT 9.745 29.295 10.035 29.340 ;
        RECT 20.770 29.280 21.090 29.340 ;
        RECT 9.270 28.800 9.590 28.860 ;
        RECT 10.190 28.800 10.510 28.860 ;
        RECT 18.930 28.800 19.250 28.860 ;
        RECT 20.310 28.800 20.630 28.860 ;
        RECT 9.075 28.660 9.590 28.800 ;
        RECT 9.995 28.660 10.510 28.800 ;
        RECT 18.735 28.660 19.250 28.800 ;
        RECT 20.115 28.660 20.630 28.800 ;
        RECT 9.270 28.600 9.590 28.660 ;
        RECT 10.190 28.600 10.510 28.660 ;
        RECT 18.930 28.600 19.250 28.660 ;
        RECT 20.310 28.600 20.630 28.660 ;
        RECT 20.770 28.800 21.090 28.860 ;
        RECT 21.245 28.800 21.535 28.845 ;
        RECT 20.770 28.660 21.535 28.800 ;
        RECT 20.770 28.600 21.090 28.660 ;
        RECT 21.245 28.615 21.535 28.660 ;
        RECT 21.705 28.615 21.995 28.845 ;
        RECT 7.890 28.460 8.210 28.520 ;
        RECT 9.730 28.460 10.050 28.520 ;
        RECT 21.780 28.460 21.920 28.615 ;
        RECT 7.890 28.320 10.050 28.460 ;
        RECT 7.890 28.260 8.210 28.320 ;
        RECT 9.730 28.260 10.050 28.320 ;
        RECT 19.480 28.320 21.920 28.460 ;
        RECT 17.550 27.780 17.870 27.840 ;
        RECT 19.480 27.825 19.620 28.320 ;
        RECT 19.405 27.780 19.695 27.825 ;
        RECT 17.550 27.640 19.695 27.780 ;
        RECT 17.550 27.580 17.870 27.640 ;
        RECT 19.405 27.595 19.695 27.640 ;
        RECT 10.190 26.760 10.510 26.820 ;
        RECT 10.665 26.760 10.955 26.805 ;
        RECT 14.330 26.760 14.650 26.820 ;
        RECT 10.190 26.620 10.955 26.760 ;
        RECT 14.135 26.620 14.650 26.760 ;
        RECT 10.190 26.560 10.510 26.620 ;
        RECT 10.665 26.575 10.955 26.620 ;
        RECT 14.330 26.560 14.650 26.620 ;
        RECT 16.645 26.760 16.935 26.805 ;
        RECT 18.470 26.760 18.790 26.820 ;
        RECT 16.645 26.620 18.790 26.760 ;
        RECT 16.645 26.575 16.935 26.620 ;
        RECT 18.470 26.560 18.790 26.620 ;
        RECT 19.175 26.760 19.465 26.805 ;
        RECT 20.310 26.760 20.630 26.820 ;
        RECT 19.175 26.620 20.630 26.760 ;
        RECT 19.175 26.575 19.465 26.620 ;
        RECT 20.310 26.560 20.630 26.620 ;
        RECT 13.885 26.420 14.175 26.465 ;
        RECT 16.170 26.420 16.490 26.480 ;
        RECT 13.885 26.280 16.490 26.420 ;
        RECT 13.885 26.235 14.175 26.280 ;
        RECT 16.170 26.220 16.490 26.280 ;
        RECT 17.550 26.080 17.870 26.140 ;
        RECT 13.500 25.940 17.870 26.080 ;
        RECT 10.650 25.740 10.970 25.800 ;
        RECT 13.500 25.785 13.640 25.940 ;
        RECT 17.550 25.880 17.870 25.940 ;
        RECT 10.455 25.600 10.970 25.740 ;
        RECT 10.650 25.540 10.970 25.600 ;
        RECT 13.450 25.555 13.740 25.785 ;
        RECT 14.330 25.740 14.650 25.800 ;
        RECT 16.645 25.740 16.935 25.785 ;
        RECT 18.010 25.740 18.330 25.800 ;
        RECT 18.660 25.740 18.950 25.785 ;
        RECT 14.330 25.600 16.935 25.740 ;
        RECT 17.815 25.600 18.330 25.740 ;
        RECT 14.330 25.540 14.650 25.600 ;
        RECT 16.645 25.555 16.935 25.600 ;
        RECT 18.010 25.540 18.330 25.600 ;
        RECT 18.560 25.555 18.950 25.740 ;
        RECT 12.950 25.400 13.270 25.460 ;
        RECT 14.805 25.400 15.095 25.445 ;
        RECT 18.560 25.400 18.700 25.555 ;
        RECT 12.950 25.260 15.095 25.400 ;
        RECT 12.950 25.200 13.270 25.260 ;
        RECT 14.805 25.215 15.095 25.260 ;
        RECT 16.720 25.260 18.700 25.400 ;
        RECT 13.410 25.060 13.730 25.120 ;
        RECT 16.720 25.060 16.860 25.260 ;
        RECT 17.550 25.060 17.870 25.120 ;
        RECT 13.410 24.920 16.860 25.060 ;
        RECT 17.355 24.920 17.870 25.060 ;
        RECT 13.410 24.860 13.730 24.920 ;
        RECT 17.550 24.860 17.870 24.920 ;
        RECT 17.550 24.040 17.870 24.100 ;
        RECT 18.485 24.040 18.775 24.085 ;
        RECT 17.550 23.900 18.775 24.040 ;
        RECT 17.550 23.840 17.870 23.900 ;
        RECT 18.485 23.855 18.775 23.900 ;
        RECT 12.950 23.700 13.270 23.760 ;
        RECT 14.115 23.700 14.405 23.745 ;
        RECT 12.950 23.560 16.400 23.700 ;
        RECT 12.950 23.500 13.270 23.560 ;
        RECT 14.115 23.515 14.405 23.560 ;
        RECT 13.680 23.360 13.970 23.405 ;
        RECT 14.790 23.360 15.110 23.420 ;
        RECT 16.260 23.405 16.400 23.560 ;
        RECT 13.680 23.220 15.110 23.360 ;
        RECT 13.680 23.175 13.970 23.220 ;
        RECT 14.790 23.160 15.110 23.220 ;
        RECT 16.185 23.175 16.475 23.405 ;
        RECT 17.090 23.360 17.410 23.420 ;
        RECT 18.025 23.360 18.315 23.405 ;
        RECT 18.930 23.360 19.250 23.420 ;
        RECT 16.720 23.220 18.315 23.360 ;
        RECT 18.735 23.220 19.250 23.360 ;
        RECT 10.650 23.020 10.970 23.080 ;
        RECT 16.720 23.065 16.860 23.220 ;
        RECT 17.090 23.160 17.410 23.220 ;
        RECT 18.025 23.175 18.315 23.220 ;
        RECT 18.930 23.160 19.250 23.220 ;
        RECT 19.405 23.360 19.695 23.405 ;
        RECT 20.310 23.360 20.630 23.420 ;
        RECT 19.405 23.220 20.630 23.360 ;
        RECT 19.405 23.175 19.695 23.220 ;
        RECT 20.310 23.160 20.630 23.220 ;
        RECT 16.645 23.020 16.935 23.065 ;
        RECT 10.650 22.880 16.935 23.020 ;
        RECT 10.650 22.820 10.970 22.880 ;
        RECT 16.645 22.835 16.935 22.880 ;
        RECT 17.565 23.020 17.855 23.065 ;
        RECT 18.470 23.020 18.790 23.080 ;
        RECT 17.565 22.880 18.790 23.020 ;
        RECT 17.565 22.835 17.855 22.880 ;
        RECT 18.470 22.820 18.790 22.880 ;
        RECT 13.410 22.680 13.730 22.740 ;
        RECT 17.105 22.680 17.395 22.725 ;
        RECT 13.410 22.540 17.395 22.680 ;
        RECT 13.410 22.480 13.730 22.540 ;
        RECT 17.105 22.495 17.395 22.540 ;
        RECT 14.790 22.340 15.110 22.400 ;
        RECT 20.310 22.340 20.630 22.400 ;
        RECT 21.690 22.340 22.010 22.400 ;
        RECT 14.790 22.200 22.010 22.340 ;
        RECT 14.790 22.140 15.110 22.200 ;
        RECT 20.310 22.140 20.630 22.200 ;
        RECT 21.690 22.140 22.010 22.200 ;
        RECT 18.025 21.320 18.315 21.365 ;
        RECT 18.930 21.320 19.250 21.380 ;
        RECT 18.025 21.180 19.250 21.320 ;
        RECT 18.025 21.135 18.315 21.180 ;
        RECT 18.930 21.120 19.250 21.180 ;
        RECT 19.850 20.980 20.170 21.040 ;
        RECT 19.020 20.840 20.170 20.980 ;
        RECT 9.745 20.640 10.035 20.685 ;
        RECT 16.630 20.640 16.950 20.700 ;
        RECT 19.020 20.640 19.160 20.840 ;
        RECT 19.850 20.780 20.170 20.840 ;
        RECT 9.745 20.500 16.400 20.640 ;
        RECT 9.745 20.455 10.035 20.500 ;
        RECT 8.080 20.300 8.370 20.345 ;
        RECT 7.980 20.115 8.370 20.300 ;
        RECT 8.595 20.300 8.885 20.345 ;
        RECT 9.285 20.300 9.575 20.345 ;
        RECT 10.190 20.300 10.510 20.360 ;
        RECT 16.260 20.345 16.400 20.500 ;
        RECT 16.630 20.500 19.160 20.640 ;
        RECT 19.405 20.640 19.695 20.685 ;
        RECT 19.405 20.500 23.760 20.640 ;
        RECT 16.630 20.440 16.950 20.500 ;
        RECT 19.405 20.455 19.695 20.500 ;
        RECT 8.595 20.160 9.575 20.300 ;
        RECT 9.995 20.160 10.510 20.300 ;
        RECT 8.595 20.115 8.885 20.160 ;
        RECT 9.285 20.115 9.575 20.160 ;
        RECT 7.980 19.620 8.120 20.115 ;
        RECT 10.190 20.100 10.510 20.160 ;
        RECT 16.185 20.115 16.475 20.345 ;
        RECT 17.105 20.115 17.395 20.345 ;
        RECT 17.550 20.300 17.870 20.360 ;
        RECT 17.550 20.160 18.065 20.300 ;
        RECT 17.180 19.960 17.320 20.115 ;
        RECT 17.550 20.100 17.870 20.160 ;
        RECT 18.485 20.115 18.775 20.345 ;
        RECT 18.930 20.300 19.250 20.360 ;
        RECT 19.850 20.300 20.170 20.360 ;
        RECT 18.930 20.160 19.445 20.300 ;
        RECT 19.655 20.160 20.170 20.300 ;
        RECT 18.560 19.960 18.700 20.115 ;
        RECT 18.930 20.100 19.250 20.160 ;
        RECT 19.850 20.100 20.170 20.160 ;
        RECT 20.310 20.300 20.630 20.360 ;
        RECT 20.310 20.160 20.825 20.300 ;
        RECT 20.310 20.100 20.630 20.160 ;
        RECT 21.245 20.115 21.535 20.345 ;
        RECT 22.610 20.300 22.930 20.360 ;
        RECT 23.620 20.345 23.760 20.500 ;
        RECT 22.415 20.160 22.930 20.300 ;
        RECT 20.770 19.960 21.090 20.020 ;
        RECT 17.180 19.820 21.090 19.960 ;
        RECT 21.320 19.960 21.460 20.115 ;
        RECT 22.610 20.100 22.930 20.160 ;
        RECT 23.545 20.115 23.835 20.345 ;
        RECT 23.085 19.960 23.375 20.005 ;
        RECT 21.320 19.820 23.375 19.960 ;
        RECT 20.770 19.760 21.090 19.820 ;
        RECT 23.085 19.775 23.375 19.820 ;
        RECT 17.550 19.620 17.870 19.680 ;
        RECT 20.310 19.620 20.630 19.680 ;
        RECT 21.230 19.620 21.550 19.680 ;
        RECT 7.980 19.480 20.630 19.620 ;
        RECT 21.035 19.480 21.550 19.620 ;
        RECT 17.550 19.420 17.870 19.480 ;
        RECT 20.310 19.420 20.630 19.480 ;
        RECT 21.230 19.420 21.550 19.480 ;
        RECT 9.730 18.600 10.050 18.660 ;
        RECT 18.010 18.645 18.330 18.660 ;
        RECT 9.535 18.460 10.050 18.600 ;
        RECT 9.730 18.400 10.050 18.460 ;
        RECT 17.795 18.415 18.330 18.645 ;
        RECT 18.010 18.400 18.330 18.415 ;
        RECT 9.285 17.735 9.575 17.965 ;
        RECT 9.730 17.920 10.050 17.980 ;
        RECT 17.550 17.965 17.870 17.980 ;
        RECT 10.205 17.920 10.495 17.965 ;
        RECT 9.730 17.780 10.495 17.920 ;
        RECT 9.360 17.580 9.500 17.735 ;
        RECT 9.730 17.720 10.050 17.780 ;
        RECT 10.205 17.735 10.495 17.780 ;
        RECT 17.440 17.735 17.870 17.965 ;
        RECT 17.550 17.720 17.870 17.735 ;
        RECT 16.170 17.580 16.490 17.640 ;
        RECT 9.360 17.440 16.490 17.580 ;
        RECT 16.170 17.380 16.490 17.440 ;
        RECT 18.470 17.580 18.790 17.640 ;
        RECT 20.310 17.580 20.630 17.640 ;
        RECT 18.470 17.440 20.630 17.580 ;
        RECT 18.470 17.380 18.790 17.440 ;
        RECT 20.310 17.380 20.630 17.440 ;
        RECT 9.730 15.880 10.050 15.940 ;
        RECT 9.535 15.740 10.050 15.880 ;
        RECT 9.730 15.680 10.050 15.740 ;
        RECT 11.585 15.880 11.875 15.925 ;
        RECT 16.170 15.880 16.490 15.940 ;
        RECT 17.550 15.880 17.870 15.940 ;
        RECT 19.390 15.880 19.710 15.940 ;
        RECT 11.585 15.740 16.490 15.880 ;
        RECT 17.355 15.740 17.870 15.880 ;
        RECT 19.195 15.740 19.710 15.880 ;
        RECT 11.585 15.695 11.875 15.740 ;
        RECT 16.170 15.680 16.490 15.740 ;
        RECT 17.550 15.680 17.870 15.740 ;
        RECT 19.390 15.680 19.710 15.740 ;
        RECT 7.890 15.540 8.210 15.600 ;
        RECT 10.205 15.540 10.495 15.585 ;
        RECT 13.410 15.540 13.730 15.600 ;
        RECT 7.890 15.400 13.730 15.540 ;
        RECT 7.890 15.340 8.210 15.400 ;
        RECT 10.205 15.355 10.495 15.400 ;
        RECT 13.410 15.340 13.730 15.400 ;
        RECT 13.870 15.540 14.190 15.600 ;
        RECT 18.470 15.540 18.790 15.600 ;
        RECT 13.870 15.400 18.790 15.540 ;
        RECT 13.870 15.340 14.190 15.400 ;
        RECT 18.470 15.340 18.790 15.400 ;
        RECT 16.645 15.200 16.935 15.245 ;
        RECT 11.660 15.060 16.935 15.200 ;
        RECT 9.730 14.860 10.050 14.920 ;
        RECT 9.535 14.720 10.050 14.860 ;
        RECT 9.730 14.660 10.050 14.720 ;
        RECT 10.650 14.860 10.970 14.920 ;
        RECT 11.660 14.905 11.800 15.060 ;
        RECT 16.645 15.015 16.935 15.060 ;
        RECT 17.090 15.200 17.410 15.260 ;
        RECT 17.565 15.200 17.855 15.245 ;
        RECT 17.090 15.060 17.855 15.200 ;
        RECT 17.090 15.000 17.410 15.060 ;
        RECT 17.565 15.015 17.855 15.060 ;
        RECT 18.010 15.200 18.330 15.260 ;
        RECT 18.010 15.060 18.525 15.200 ;
        RECT 18.010 15.000 18.330 15.060 ;
        RECT 11.585 14.860 11.875 14.905 ;
        RECT 10.650 14.720 11.875 14.860 ;
        RECT 10.650 14.660 10.970 14.720 ;
        RECT 11.585 14.675 11.875 14.720 ;
        RECT 12.505 14.860 12.795 14.905 ;
        RECT 13.870 14.860 14.190 14.920 ;
        RECT 18.485 14.860 18.775 14.905 ;
        RECT 20.310 14.860 20.630 14.920 ;
        RECT 12.505 14.720 14.190 14.860 ;
        RECT 12.505 14.675 12.795 14.720 ;
        RECT 13.870 14.660 14.190 14.720 ;
        RECT 16.260 14.720 19.620 14.860 ;
        RECT 20.115 14.720 20.630 14.860 ;
        RECT 11.125 14.520 11.415 14.565 ;
        RECT 16.260 14.520 16.400 14.720 ;
        RECT 18.485 14.675 18.775 14.720 ;
        RECT 19.480 14.580 19.620 14.720 ;
        RECT 20.310 14.660 20.630 14.720 ;
        RECT 11.125 14.380 16.400 14.520 ;
        RECT 18.010 14.520 18.330 14.580 ;
        RECT 18.945 14.520 19.235 14.565 ;
        RECT 18.010 14.380 19.235 14.520 ;
        RECT 11.125 14.335 11.415 14.380 ;
        RECT 11.200 14.180 11.340 14.335 ;
        RECT 18.010 14.320 18.330 14.380 ;
        RECT 18.945 14.335 19.235 14.380 ;
        RECT 19.390 14.520 19.710 14.580 ;
        RECT 19.865 14.520 20.155 14.565 ;
        RECT 19.390 14.380 20.155 14.520 ;
        RECT 11.570 14.180 11.890 14.240 ;
        RECT 11.200 14.040 11.890 14.180 ;
        RECT 19.020 14.180 19.160 14.335 ;
        RECT 19.390 14.320 19.710 14.380 ;
        RECT 19.865 14.335 20.155 14.380 ;
        RECT 23.070 14.180 23.390 14.240 ;
        RECT 19.020 14.040 23.390 14.180 ;
        RECT 11.570 13.980 11.890 14.040 ;
        RECT 23.070 13.980 23.390 14.040 ;
        RECT 19.405 13.160 19.695 13.205 ;
        RECT 20.310 13.160 20.630 13.220 ;
        RECT 19.405 13.020 20.630 13.160 ;
        RECT 19.405 12.975 19.695 13.020 ;
        RECT 20.310 12.960 20.630 13.020 ;
        RECT 20.770 13.160 21.090 13.220 ;
        RECT 20.770 13.020 21.285 13.160 ;
        RECT 20.770 12.960 21.090 13.020 ;
        RECT 9.730 12.820 10.050 12.880 ;
        RECT 17.105 12.820 17.395 12.865 ;
        RECT 9.295 12.680 17.395 12.820 ;
        RECT 9.360 12.525 9.500 12.680 ;
        RECT 9.730 12.620 10.050 12.680 ;
        RECT 17.105 12.635 17.395 12.680 ;
        RECT 9.285 12.295 9.575 12.525 ;
        RECT 10.190 12.480 10.510 12.540 ;
        RECT 9.995 12.340 10.510 12.480 ;
        RECT 10.190 12.280 10.510 12.340 ;
        RECT 16.645 12.295 16.935 12.525 ;
        RECT 17.565 12.480 17.855 12.525 ;
        RECT 18.930 12.480 19.250 12.540 ;
        RECT 20.310 12.480 20.630 12.540 ;
        RECT 21.230 12.480 21.550 12.540 ;
        RECT 17.565 12.340 19.250 12.480 ;
        RECT 20.115 12.340 20.630 12.480 ;
        RECT 21.035 12.340 21.550 12.480 ;
        RECT 17.565 12.295 17.855 12.340 ;
        RECT 11.125 11.955 11.415 12.185 ;
        RECT 16.720 12.140 16.860 12.295 ;
        RECT 18.930 12.280 19.250 12.340 ;
        RECT 20.310 12.280 20.630 12.340 ;
        RECT 21.230 12.280 21.550 12.340 ;
        RECT 21.705 12.295 21.995 12.525 ;
        RECT 18.010 12.140 18.330 12.200 ;
        RECT 16.720 12.000 18.330 12.140 ;
        RECT 11.200 11.800 11.340 11.955 ;
        RECT 18.010 11.940 18.330 12.000 ;
        RECT 18.470 12.140 18.790 12.200 ;
        RECT 19.405 12.140 19.695 12.185 ;
        RECT 21.780 12.140 21.920 12.295 ;
        RECT 18.470 12.000 18.985 12.140 ;
        RECT 19.405 12.000 21.920 12.140 ;
        RECT 18.470 11.940 18.790 12.000 ;
        RECT 19.405 11.955 19.695 12.000 ;
        RECT 17.090 11.800 17.410 11.860 ;
        RECT 19.480 11.800 19.620 11.955 ;
        RECT 11.200 11.660 19.620 11.800 ;
        RECT 17.090 11.600 17.410 11.660 ;
        RECT 9.285 10.440 9.575 10.485 ;
        RECT 10.190 10.440 10.510 10.500 ;
        RECT 18.010 10.485 18.330 10.500 ;
        RECT 9.285 10.300 10.510 10.440 ;
        RECT 9.285 10.255 9.575 10.300 ;
        RECT 10.190 10.240 10.510 10.300 ;
        RECT 17.795 10.255 18.330 10.485 ;
        RECT 18.010 10.240 18.330 10.255 ;
        RECT 21.230 10.440 21.550 10.500 ;
        RECT 22.625 10.440 22.915 10.485 ;
        RECT 21.230 10.300 22.915 10.440 ;
        RECT 21.230 10.240 21.550 10.300 ;
        RECT 22.625 10.255 22.915 10.300 ;
        RECT 12.045 9.915 12.335 10.145 ;
        RECT 9.270 9.760 9.590 9.820 ;
        RECT 9.745 9.760 10.035 9.805 ;
        RECT 12.120 9.760 12.260 9.915 ;
        RECT 19.390 9.760 19.710 9.820 ;
        RECT 9.270 9.620 12.260 9.760 ;
        RECT 19.195 9.620 19.710 9.760 ;
        RECT 9.270 9.560 9.590 9.620 ;
        RECT 9.745 9.575 10.035 9.620 ;
        RECT 19.390 9.560 19.710 9.620 ;
        RECT 21.705 9.575 21.995 9.805 ;
        RECT 8.350 9.420 8.670 9.480 ;
        RECT 8.155 9.280 8.670 9.420 ;
        RECT 8.350 9.220 8.670 9.280 ;
        RECT 8.825 9.235 9.115 9.465 ;
        RECT 10.650 9.420 10.970 9.480 ;
        RECT 11.570 9.420 11.890 9.480 ;
        RECT 12.950 9.420 13.270 9.480 ;
        RECT 10.455 9.280 10.970 9.420 ;
        RECT 11.375 9.280 11.890 9.420 ;
        RECT 12.755 9.280 13.270 9.420 ;
        RECT 8.900 9.080 9.040 9.235 ;
        RECT 10.650 9.220 10.970 9.280 ;
        RECT 11.570 9.220 11.890 9.280 ;
        RECT 12.950 9.220 13.270 9.280 ;
        RECT 16.170 9.420 16.490 9.480 ;
        RECT 17.280 9.420 17.570 9.465 ;
        RECT 19.850 9.420 20.170 9.480 ;
        RECT 16.170 9.280 20.170 9.420 ;
        RECT 21.780 9.420 21.920 9.575 ;
        RECT 22.165 9.420 22.455 9.465 ;
        RECT 23.070 9.420 23.390 9.480 ;
        RECT 21.780 9.280 22.455 9.420 ;
        RECT 22.875 9.280 23.390 9.420 ;
        RECT 16.170 9.220 16.490 9.280 ;
        RECT 17.280 9.235 17.570 9.280 ;
        RECT 19.850 9.220 20.170 9.280 ;
        RECT 22.165 9.235 22.455 9.280 ;
        RECT 23.070 9.220 23.390 9.280 ;
        RECT 11.125 9.080 11.415 9.125 ;
        RECT 8.900 8.940 11.415 9.080 ;
        RECT 11.125 8.895 11.415 8.940 ;
        RECT 8.810 8.740 9.130 8.800 ;
        RECT 18.470 8.740 18.790 8.800 ;
        RECT 8.810 8.600 18.790 8.740 ;
        RECT 8.810 8.540 9.130 8.600 ;
        RECT 18.470 8.540 18.790 8.600 ;
        RECT 8.350 7.720 8.670 7.780 ;
        RECT 8.155 7.580 8.670 7.720 ;
        RECT 8.350 7.520 8.670 7.580 ;
        RECT 12.950 7.520 13.270 7.780 ;
        RECT 14.345 7.720 14.635 7.765 ;
        RECT 20.310 7.720 20.630 7.780 ;
        RECT 21.705 7.720 21.995 7.765 ;
        RECT 14.345 7.580 19.620 7.720 ;
        RECT 14.345 7.535 14.635 7.580 ;
        RECT 13.040 7.380 13.180 7.520 ;
        RECT 15.725 7.380 16.015 7.425 ;
        RECT 13.040 7.240 16.015 7.380 ;
        RECT 19.480 7.380 19.620 7.580 ;
        RECT 20.310 7.580 21.995 7.720 ;
        RECT 20.310 7.520 20.630 7.580 ;
        RECT 21.705 7.535 21.995 7.580 ;
        RECT 23.070 7.720 23.390 7.780 ;
        RECT 23.545 7.720 23.835 7.765 ;
        RECT 23.070 7.580 23.835 7.720 ;
        RECT 23.070 7.520 23.390 7.580 ;
        RECT 23.545 7.535 23.835 7.580 ;
        RECT 20.785 7.380 21.075 7.425 ;
        RECT 19.480 7.240 20.080 7.380 ;
        RECT 7.890 7.040 8.210 7.100 ;
        RECT 8.810 7.040 9.130 7.100 ;
        RECT 7.695 6.900 8.210 7.040 ;
        RECT 8.615 6.900 9.130 7.040 ;
        RECT 7.890 6.840 8.210 6.900 ;
        RECT 8.810 6.840 9.130 6.900 ;
        RECT 10.650 7.040 10.970 7.100 ;
        RECT 14.420 7.085 14.560 7.240 ;
        RECT 15.725 7.195 16.015 7.240 ;
        RECT 12.220 7.040 12.510 7.085 ;
        RECT 10.650 6.900 12.510 7.040 ;
        RECT 10.650 6.840 10.970 6.900 ;
        RECT 12.120 6.855 12.510 6.900 ;
        RECT 12.735 7.040 13.025 7.085 ;
        RECT 13.425 7.040 13.715 7.085 ;
        RECT 12.735 6.900 13.715 7.040 ;
        RECT 12.735 6.855 13.025 6.900 ;
        RECT 13.425 6.855 13.715 6.900 ;
        RECT 14.345 6.855 14.635 7.085 ;
        RECT 15.250 7.040 15.570 7.100 ;
        RECT 15.055 6.900 15.570 7.040 ;
        RECT 12.120 6.020 12.260 6.855 ;
        RECT 15.250 6.840 15.570 6.900 ;
        RECT 16.185 7.040 16.475 7.085 ;
        RECT 18.360 7.040 18.650 7.085 ;
        RECT 19.405 7.040 19.695 7.085 ;
        RECT 16.185 6.900 16.860 7.040 ;
        RECT 16.185 6.855 16.475 6.900 ;
        RECT 16.720 6.700 16.860 6.900 ;
        RECT 18.360 6.900 19.695 7.040 ;
        RECT 19.940 7.040 20.080 7.240 ;
        RECT 20.785 7.240 24.220 7.380 ;
        RECT 20.785 7.195 21.075 7.240 ;
        RECT 21.245 7.040 21.535 7.085 ;
        RECT 19.940 6.900 21.535 7.040 ;
        RECT 18.360 6.855 18.700 6.900 ;
        RECT 19.405 6.855 19.695 6.900 ;
        RECT 21.245 6.855 21.535 6.900 ;
        RECT 21.690 7.040 22.010 7.100 ;
        RECT 22.700 7.085 22.840 7.240 ;
        RECT 24.080 7.085 24.220 7.240 ;
        RECT 22.165 7.040 22.455 7.085 ;
        RECT 21.690 6.900 22.455 7.040 ;
        RECT 18.560 6.700 18.700 6.855 ;
        RECT 19.850 6.700 20.170 6.760 ;
        RECT 20.770 6.700 21.090 6.760 ;
        RECT 16.720 6.560 18.700 6.700 ;
        RECT 19.655 6.560 20.170 6.700 ;
        RECT 20.575 6.560 21.090 6.700 ;
        RECT 21.320 6.700 21.460 6.855 ;
        RECT 21.690 6.840 22.010 6.900 ;
        RECT 22.165 6.855 22.455 6.900 ;
        RECT 22.625 6.855 22.915 7.085 ;
        RECT 23.085 6.855 23.375 7.085 ;
        RECT 24.005 6.855 24.295 7.085 ;
        RECT 23.160 6.700 23.300 6.855 ;
        RECT 21.320 6.560 23.300 6.700 ;
        RECT 16.720 6.405 16.860 6.560 ;
        RECT 19.850 6.500 20.170 6.560 ;
        RECT 20.770 6.500 21.090 6.560 ;
        RECT 18.930 6.405 19.250 6.420 ;
        RECT 16.645 6.175 16.935 6.405 ;
        RECT 18.715 6.175 19.250 6.405 ;
        RECT 18.930 6.160 19.250 6.175 ;
        RECT 20.770 6.020 21.090 6.080 ;
        RECT 12.120 5.880 21.090 6.020 ;
        RECT 20.770 5.820 21.090 5.880 ;
        RECT 15.250 5.000 15.570 5.060 ;
        RECT 15.725 5.000 16.015 5.045 ;
        RECT 15.250 4.860 16.015 5.000 ;
        RECT 15.250 4.800 15.570 4.860 ;
        RECT 15.725 4.815 16.015 4.860 ;
        RECT 18.930 5.000 19.250 5.060 ;
        RECT 19.865 5.000 20.155 5.045 ;
        RECT 21.690 5.000 22.010 5.060 ;
        RECT 18.930 4.860 20.155 5.000 ;
        RECT 21.495 4.860 22.010 5.000 ;
        RECT 18.930 4.800 19.250 4.860 ;
        RECT 19.865 4.815 20.155 4.860 ;
        RECT 21.690 4.800 22.010 4.860 ;
        RECT 18.485 4.660 18.775 4.705 ;
        RECT 19.390 4.660 19.710 4.720 ;
        RECT 18.485 4.520 19.710 4.660 ;
        RECT 18.485 4.475 18.775 4.520 ;
        RECT 19.390 4.460 19.710 4.520 ;
        RECT 20.770 4.320 21.090 4.380 ;
        RECT 25.845 4.320 26.135 4.365 ;
        RECT 20.770 4.180 26.135 4.320 ;
        RECT 20.770 4.120 21.090 4.180 ;
        RECT 25.845 4.135 26.135 4.180 ;
      LAYER via ;
        RECT 6.540 36.420 6.800 36.680 ;
        RECT 8.380 36.420 8.640 36.680 ;
        RECT 9.300 36.420 9.560 36.680 ;
        RECT 10.220 36.420 10.480 36.680 ;
        RECT 12.060 36.420 12.320 36.680 ;
        RECT 12.520 36.420 12.780 36.680 ;
        RECT 18.040 36.420 18.300 36.680 ;
        RECT 19.880 36.420 20.140 36.680 ;
        RECT 21.260 36.420 21.520 36.680 ;
        RECT 24.480 36.420 24.740 36.680 ;
        RECT 17.580 36.080 17.840 36.340 ;
        RECT 6.540 34.720 6.800 34.980 ;
        RECT 9.300 34.720 9.560 34.980 ;
        RECT 8.380 34.040 8.640 34.300 ;
        RECT 9.300 34.040 9.560 34.300 ;
        RECT 12.520 34.720 12.780 34.980 ;
        RECT 18.040 34.720 18.300 34.980 ;
        RECT 19.880 34.720 20.140 34.980 ;
        RECT 21.260 34.720 21.520 34.980 ;
        RECT 13.440 34.040 13.700 34.300 ;
        RECT 18.500 34.040 18.760 34.300 ;
        RECT 20.340 34.040 20.600 34.300 ;
        RECT 16.660 33.700 16.920 33.960 ;
        RECT 24.480 34.040 24.740 34.300 ;
        RECT 9.760 33.360 10.020 33.620 ;
        RECT 15.280 33.020 15.540 33.280 ;
        RECT 8.380 32.000 8.640 32.260 ;
        RECT 9.760 32.000 10.020 32.260 ;
        RECT 12.060 32.000 12.320 32.260 ;
        RECT 20.340 32.000 20.600 32.260 ;
        RECT 24.480 32.000 24.740 32.260 ;
        RECT 9.300 31.660 9.560 31.920 ;
        RECT 7.920 30.980 8.180 31.240 ;
        RECT 9.760 30.980 10.020 31.240 ;
        RECT 10.680 30.300 10.940 30.560 ;
        RECT 12.980 30.980 13.240 31.240 ;
        RECT 15.280 30.980 15.540 31.240 ;
        RECT 21.260 30.980 21.520 31.240 ;
        RECT 16.660 30.640 16.920 30.900 ;
        RECT 18.960 30.640 19.220 30.900 ;
        RECT 20.800 30.640 21.060 30.900 ;
        RECT 19.420 30.300 19.680 30.560 ;
        RECT 9.300 29.280 9.560 29.540 ;
        RECT 20.800 29.280 21.060 29.540 ;
        RECT 9.300 28.600 9.560 28.860 ;
        RECT 10.220 28.600 10.480 28.860 ;
        RECT 18.960 28.600 19.220 28.860 ;
        RECT 20.340 28.600 20.600 28.860 ;
        RECT 20.800 28.600 21.060 28.860 ;
        RECT 7.920 28.260 8.180 28.520 ;
        RECT 9.760 28.260 10.020 28.520 ;
        RECT 17.580 27.580 17.840 27.840 ;
        RECT 10.220 26.560 10.480 26.820 ;
        RECT 14.360 26.560 14.620 26.820 ;
        RECT 18.500 26.560 18.760 26.820 ;
        RECT 20.340 26.560 20.600 26.820 ;
        RECT 16.200 26.220 16.460 26.480 ;
        RECT 10.680 25.540 10.940 25.800 ;
        RECT 17.580 25.880 17.840 26.140 ;
        RECT 14.360 25.540 14.620 25.800 ;
        RECT 18.040 25.540 18.300 25.800 ;
        RECT 12.980 25.200 13.240 25.460 ;
        RECT 13.440 24.860 13.700 25.120 ;
        RECT 17.580 24.860 17.840 25.120 ;
        RECT 17.580 23.840 17.840 24.100 ;
        RECT 12.980 23.500 13.240 23.760 ;
        RECT 14.820 23.160 15.080 23.420 ;
        RECT 10.680 22.820 10.940 23.080 ;
        RECT 17.120 23.160 17.380 23.420 ;
        RECT 18.960 23.160 19.220 23.420 ;
        RECT 20.340 23.160 20.600 23.420 ;
        RECT 18.500 22.820 18.760 23.080 ;
        RECT 13.440 22.480 13.700 22.740 ;
        RECT 14.820 22.140 15.080 22.400 ;
        RECT 20.340 22.140 20.600 22.400 ;
        RECT 21.720 22.140 21.980 22.400 ;
        RECT 18.960 21.120 19.220 21.380 ;
        RECT 10.220 20.100 10.480 20.360 ;
        RECT 16.660 20.440 16.920 20.700 ;
        RECT 19.880 20.780 20.140 21.040 ;
        RECT 17.580 20.100 17.840 20.360 ;
        RECT 18.960 20.100 19.220 20.360 ;
        RECT 19.880 20.100 20.140 20.360 ;
        RECT 20.340 20.100 20.600 20.360 ;
        RECT 20.800 19.760 21.060 20.020 ;
        RECT 22.640 20.100 22.900 20.360 ;
        RECT 17.580 19.420 17.840 19.680 ;
        RECT 20.340 19.420 20.600 19.680 ;
        RECT 21.260 19.420 21.520 19.680 ;
        RECT 9.760 18.400 10.020 18.660 ;
        RECT 18.040 18.400 18.300 18.660 ;
        RECT 9.760 17.720 10.020 17.980 ;
        RECT 17.580 17.720 17.840 17.980 ;
        RECT 16.200 17.380 16.460 17.640 ;
        RECT 18.500 17.380 18.760 17.640 ;
        RECT 20.340 17.380 20.600 17.640 ;
        RECT 9.760 15.680 10.020 15.940 ;
        RECT 16.200 15.680 16.460 15.940 ;
        RECT 17.580 15.680 17.840 15.940 ;
        RECT 19.420 15.680 19.680 15.940 ;
        RECT 7.920 15.340 8.180 15.600 ;
        RECT 13.440 15.340 13.700 15.600 ;
        RECT 13.900 15.340 14.160 15.600 ;
        RECT 18.500 15.340 18.760 15.600 ;
        RECT 9.760 14.660 10.020 14.920 ;
        RECT 10.680 14.660 10.940 14.920 ;
        RECT 17.120 15.000 17.380 15.260 ;
        RECT 18.040 15.000 18.300 15.260 ;
        RECT 13.900 14.660 14.160 14.920 ;
        RECT 20.340 14.660 20.600 14.920 ;
        RECT 18.040 14.320 18.300 14.580 ;
        RECT 11.600 13.980 11.860 14.240 ;
        RECT 19.420 14.320 19.680 14.580 ;
        RECT 23.100 13.980 23.360 14.240 ;
        RECT 20.340 12.960 20.600 13.220 ;
        RECT 20.800 12.960 21.060 13.220 ;
        RECT 9.760 12.620 10.020 12.880 ;
        RECT 10.220 12.280 10.480 12.540 ;
        RECT 18.960 12.280 19.220 12.540 ;
        RECT 20.340 12.280 20.600 12.540 ;
        RECT 21.260 12.280 21.520 12.540 ;
        RECT 18.040 11.940 18.300 12.200 ;
        RECT 18.500 11.940 18.760 12.200 ;
        RECT 17.120 11.600 17.380 11.860 ;
        RECT 10.220 10.240 10.480 10.500 ;
        RECT 18.040 10.240 18.300 10.500 ;
        RECT 21.260 10.240 21.520 10.500 ;
        RECT 9.300 9.560 9.560 9.820 ;
        RECT 19.420 9.560 19.680 9.820 ;
        RECT 8.380 9.220 8.640 9.480 ;
        RECT 10.680 9.220 10.940 9.480 ;
        RECT 11.600 9.220 11.860 9.480 ;
        RECT 12.980 9.220 13.240 9.480 ;
        RECT 16.200 9.220 16.460 9.480 ;
        RECT 19.880 9.220 20.140 9.480 ;
        RECT 23.100 9.220 23.360 9.480 ;
        RECT 8.840 8.540 9.100 8.800 ;
        RECT 18.500 8.540 18.760 8.800 ;
        RECT 8.380 7.520 8.640 7.780 ;
        RECT 12.980 7.520 13.240 7.780 ;
        RECT 20.340 7.520 20.600 7.780 ;
        RECT 23.100 7.520 23.360 7.780 ;
        RECT 7.920 6.840 8.180 7.100 ;
        RECT 8.840 6.840 9.100 7.100 ;
        RECT 10.680 6.840 10.940 7.100 ;
        RECT 15.280 6.840 15.540 7.100 ;
        RECT 19.880 6.500 20.140 6.760 ;
        RECT 20.800 6.500 21.060 6.760 ;
        RECT 21.720 6.840 21.980 7.100 ;
        RECT 18.960 6.160 19.220 6.420 ;
        RECT 20.800 5.820 21.060 6.080 ;
        RECT 15.280 4.800 15.540 5.060 ;
        RECT 18.960 4.800 19.220 5.060 ;
        RECT 21.720 4.800 21.980 5.060 ;
        RECT 19.420 4.460 19.680 4.720 ;
        RECT 20.800 4.120 21.060 4.380 ;
      LAYER met2 ;
        RECT 6.540 36.390 6.800 36.710 ;
        RECT 8.380 36.390 8.640 36.710 ;
        RECT 9.300 36.390 9.560 36.710 ;
        RECT 10.220 36.390 10.480 36.710 ;
        RECT 12.060 36.390 12.320 36.710 ;
        RECT 12.520 36.390 12.780 36.710 ;
        RECT 18.040 36.390 18.300 36.710 ;
        RECT 19.880 36.390 20.140 36.710 ;
        RECT 21.260 36.390 21.520 36.710 ;
        RECT 24.480 36.390 24.740 36.710 ;
        RECT 6.600 35.010 6.740 36.390 ;
        RECT 6.540 34.690 6.800 35.010 ;
        RECT 8.440 34.330 8.580 36.390 ;
        RECT 9.360 35.010 9.500 36.390 ;
        RECT 9.300 34.690 9.560 35.010 ;
        RECT 8.380 34.010 8.640 34.330 ;
        RECT 9.300 34.010 9.560 34.330 ;
        RECT 8.440 32.290 8.580 34.010 ;
        RECT 8.380 31.970 8.640 32.290 ;
        RECT 9.360 31.950 9.500 34.010 ;
        RECT 9.760 33.330 10.020 33.650 ;
        RECT 9.820 32.290 9.960 33.330 ;
        RECT 9.760 31.970 10.020 32.290 ;
        RECT 9.300 31.630 9.560 31.950 ;
        RECT 7.920 30.950 8.180 31.270 ;
        RECT 7.980 28.550 8.120 30.950 ;
        RECT 9.360 29.570 9.500 31.630 ;
        RECT 9.760 30.950 10.020 31.270 ;
        RECT 9.300 29.250 9.560 29.570 ;
        RECT 9.300 28.570 9.560 28.890 ;
        RECT 7.920 28.230 8.180 28.550 ;
        RECT 7.920 15.310 8.180 15.630 ;
        RECT 7.980 7.130 8.120 15.310 ;
        RECT 9.360 9.850 9.500 28.570 ;
        RECT 9.820 28.550 9.960 30.950 ;
        RECT 10.280 28.890 10.420 36.390 ;
        RECT 12.120 32.290 12.260 36.390 ;
        RECT 12.580 35.010 12.720 36.390 ;
        RECT 17.580 36.050 17.840 36.370 ;
        RECT 12.520 34.690 12.780 35.010 ;
        RECT 13.440 34.010 13.700 34.330 ;
        RECT 12.060 31.970 12.320 32.290 ;
        RECT 12.980 30.950 13.240 31.270 ;
        RECT 10.680 30.270 10.940 30.590 ;
        RECT 10.220 28.570 10.480 28.890 ;
        RECT 9.760 28.230 10.020 28.550 ;
        RECT 9.820 18.690 9.960 28.230 ;
        RECT 10.280 26.850 10.420 28.570 ;
        RECT 10.220 26.530 10.480 26.850 ;
        RECT 10.280 20.390 10.420 26.530 ;
        RECT 10.740 25.830 10.880 30.270 ;
        RECT 10.680 25.510 10.940 25.830 ;
        RECT 10.740 23.110 10.880 25.510 ;
        RECT 13.040 25.490 13.180 30.950 ;
        RECT 12.980 25.170 13.240 25.490 ;
        RECT 13.040 23.790 13.180 25.170 ;
        RECT 13.500 25.150 13.640 34.010 ;
        RECT 16.660 33.670 16.920 33.990 ;
        RECT 15.280 32.990 15.540 33.310 ;
        RECT 15.340 31.270 15.480 32.990 ;
        RECT 15.280 30.950 15.540 31.270 ;
        RECT 16.720 30.930 16.860 33.670 ;
        RECT 16.660 30.610 16.920 30.930 ;
        RECT 14.360 26.530 14.620 26.850 ;
        RECT 14.420 25.830 14.560 26.530 ;
        RECT 16.200 26.190 16.460 26.510 ;
        RECT 14.360 25.510 14.620 25.830 ;
        RECT 13.440 24.830 13.700 25.150 ;
        RECT 12.980 23.470 13.240 23.790 ;
        RECT 10.680 22.790 10.940 23.110 ;
        RECT 13.500 22.770 13.640 24.830 ;
        RECT 14.820 23.130 15.080 23.450 ;
        RECT 13.440 22.450 13.700 22.770 ;
        RECT 14.880 22.430 15.020 23.130 ;
        RECT 14.820 22.110 15.080 22.430 ;
        RECT 10.220 20.070 10.480 20.390 ;
        RECT 14.880 20.130 15.020 22.110 ;
        RECT 13.500 19.990 15.020 20.130 ;
        RECT 9.760 18.370 10.020 18.690 ;
        RECT 9.760 17.690 10.020 18.010 ;
        RECT 9.820 15.970 9.960 17.690 ;
        RECT 9.760 15.650 10.020 15.970 ;
        RECT 13.500 15.630 13.640 19.990 ;
        RECT 16.260 17.670 16.400 26.190 ;
        RECT 16.720 20.730 16.860 30.610 ;
        RECT 17.640 27.870 17.780 36.050 ;
        RECT 18.100 35.010 18.240 36.390 ;
        RECT 19.940 35.010 20.080 36.390 ;
        RECT 21.320 35.010 21.460 36.390 ;
        RECT 18.040 34.690 18.300 35.010 ;
        RECT 19.880 34.690 20.140 35.010 ;
        RECT 21.260 34.690 21.520 35.010 ;
        RECT 24.540 34.330 24.680 36.390 ;
        RECT 18.500 34.010 18.760 34.330 ;
        RECT 20.340 34.010 20.600 34.330 ;
        RECT 24.480 34.010 24.740 34.330 ;
        RECT 17.580 27.550 17.840 27.870 ;
        RECT 17.640 26.170 17.780 27.550 ;
        RECT 18.560 26.850 18.700 34.010 ;
        RECT 20.400 32.290 20.540 34.010 ;
        RECT 24.540 32.290 24.680 34.010 ;
        RECT 20.340 31.970 20.600 32.290 ;
        RECT 24.480 31.970 24.740 32.290 ;
        RECT 21.260 30.950 21.520 31.270 ;
        RECT 18.960 30.610 19.220 30.930 ;
        RECT 20.800 30.610 21.060 30.930 ;
        RECT 19.020 28.890 19.160 30.610 ;
        RECT 19.420 30.270 19.680 30.590 ;
        RECT 18.960 28.570 19.220 28.890 ;
        RECT 18.500 26.530 18.760 26.850 ;
        RECT 17.580 25.850 17.840 26.170 ;
        RECT 18.040 25.510 18.300 25.830 ;
        RECT 17.580 24.830 17.840 25.150 ;
        RECT 17.640 24.130 17.780 24.830 ;
        RECT 17.580 23.810 17.840 24.130 ;
        RECT 17.120 23.130 17.380 23.450 ;
        RECT 16.660 20.410 16.920 20.730 ;
        RECT 16.200 17.350 16.460 17.670 ;
        RECT 16.260 15.970 16.400 17.350 ;
        RECT 16.200 15.650 16.460 15.970 ;
        RECT 13.440 15.310 13.700 15.630 ;
        RECT 13.900 15.310 14.160 15.630 ;
        RECT 13.960 14.950 14.100 15.310 ;
        RECT 17.180 15.290 17.320 23.130 ;
        RECT 17.580 20.070 17.840 20.390 ;
        RECT 17.640 19.710 17.780 20.070 ;
        RECT 17.580 19.390 17.840 19.710 ;
        RECT 18.100 18.690 18.240 25.510 ;
        RECT 18.960 23.130 19.220 23.450 ;
        RECT 18.500 22.790 18.760 23.110 ;
        RECT 18.040 18.370 18.300 18.690 ;
        RECT 18.560 18.090 18.700 22.790 ;
        RECT 19.020 21.410 19.160 23.130 ;
        RECT 18.960 21.090 19.220 21.410 ;
        RECT 18.960 20.070 19.220 20.390 ;
        RECT 17.580 17.690 17.840 18.010 ;
        RECT 18.100 17.950 18.700 18.090 ;
        RECT 17.640 15.970 17.780 17.690 ;
        RECT 17.580 15.650 17.840 15.970 ;
        RECT 18.100 15.290 18.240 17.950 ;
        RECT 18.500 17.350 18.760 17.670 ;
        RECT 18.560 15.630 18.700 17.350 ;
        RECT 18.500 15.310 18.760 15.630 ;
        RECT 17.120 14.970 17.380 15.290 ;
        RECT 18.040 14.970 18.300 15.290 ;
        RECT 9.760 14.630 10.020 14.950 ;
        RECT 10.680 14.630 10.940 14.950 ;
        RECT 13.900 14.630 14.160 14.950 ;
        RECT 9.820 12.910 9.960 14.630 ;
        RECT 9.760 12.590 10.020 12.910 ;
        RECT 10.220 12.250 10.480 12.570 ;
        RECT 10.280 10.530 10.420 12.250 ;
        RECT 10.220 10.210 10.480 10.530 ;
        RECT 9.300 9.530 9.560 9.850 ;
        RECT 10.740 9.510 10.880 14.630 ;
        RECT 11.600 13.950 11.860 14.270 ;
        RECT 11.660 9.510 11.800 13.950 ;
        RECT 17.180 11.890 17.320 14.970 ;
        RECT 18.100 14.610 18.240 14.970 ;
        RECT 18.040 14.290 18.300 14.610 ;
        RECT 18.560 12.230 18.700 15.310 ;
        RECT 19.020 12.570 19.160 20.070 ;
        RECT 19.480 15.970 19.620 30.270 ;
        RECT 20.860 29.570 21.000 30.610 ;
        RECT 20.800 29.250 21.060 29.570 ;
        RECT 20.340 28.570 20.600 28.890 ;
        RECT 20.800 28.570 21.060 28.890 ;
        RECT 20.400 26.850 20.540 28.570 ;
        RECT 20.340 26.530 20.600 26.850 ;
        RECT 20.400 23.450 20.540 26.530 ;
        RECT 20.340 23.130 20.600 23.450 ;
        RECT 20.860 22.850 21.000 28.570 ;
        RECT 20.400 22.710 21.000 22.850 ;
        RECT 20.400 22.430 20.540 22.710 ;
        RECT 20.340 22.110 20.600 22.430 ;
        RECT 19.880 20.750 20.140 21.070 ;
        RECT 19.940 20.390 20.080 20.750 ;
        RECT 19.880 20.070 20.140 20.390 ;
        RECT 20.340 20.070 20.600 20.390 ;
        RECT 20.400 19.710 20.540 20.070 ;
        RECT 20.800 19.730 21.060 20.050 ;
        RECT 20.340 19.390 20.600 19.710 ;
        RECT 20.400 17.670 20.540 19.390 ;
        RECT 20.340 17.350 20.600 17.670 ;
        RECT 19.420 15.650 19.680 15.970 ;
        RECT 20.340 14.630 20.600 14.950 ;
        RECT 19.420 14.290 19.680 14.610 ;
        RECT 18.960 12.250 19.220 12.570 ;
        RECT 18.040 11.910 18.300 12.230 ;
        RECT 18.500 11.910 18.760 12.230 ;
        RECT 17.120 11.570 17.380 11.890 ;
        RECT 18.100 10.530 18.240 11.910 ;
        RECT 18.040 10.210 18.300 10.530 ;
        RECT 8.380 9.190 8.640 9.510 ;
        RECT 10.680 9.190 10.940 9.510 ;
        RECT 11.600 9.190 11.860 9.510 ;
        RECT 12.980 9.190 13.240 9.510 ;
        RECT 16.200 9.190 16.460 9.510 ;
        RECT 8.440 7.810 8.580 9.190 ;
        RECT 8.840 8.510 9.100 8.830 ;
        RECT 8.380 7.490 8.640 7.810 ;
        RECT 8.900 7.130 9.040 8.510 ;
        RECT 10.740 7.130 10.880 9.190 ;
        RECT 13.040 7.810 13.180 9.190 ;
        RECT 12.980 7.490 13.240 7.810 ;
        RECT 16.260 7.210 16.400 9.190 ;
        RECT 18.560 8.830 18.700 11.910 ;
        RECT 18.500 8.510 18.760 8.830 ;
        RECT 15.340 7.130 16.400 7.210 ;
        RECT 7.920 6.810 8.180 7.130 ;
        RECT 8.840 6.810 9.100 7.130 ;
        RECT 10.680 6.810 10.940 7.130 ;
        RECT 15.280 7.070 16.400 7.130 ;
        RECT 15.280 6.810 15.540 7.070 ;
        RECT 15.340 5.090 15.480 6.810 ;
        RECT 18.560 5.850 18.700 8.510 ;
        RECT 19.020 6.450 19.160 12.250 ;
        RECT 19.480 9.850 19.620 14.290 ;
        RECT 20.400 13.250 20.540 14.630 ;
        RECT 20.860 13.250 21.000 19.730 ;
        RECT 21.320 19.710 21.460 30.950 ;
        RECT 21.720 22.110 21.980 22.430 ;
        RECT 21.260 19.390 21.520 19.710 ;
        RECT 20.340 12.930 20.600 13.250 ;
        RECT 20.800 12.930 21.060 13.250 ;
        RECT 20.340 12.250 20.600 12.570 ;
        RECT 21.260 12.250 21.520 12.570 ;
        RECT 19.420 9.530 19.680 9.850 ;
        RECT 18.960 6.130 19.220 6.450 ;
        RECT 18.560 5.710 19.160 5.850 ;
        RECT 19.020 5.090 19.160 5.710 ;
        RECT 15.280 4.770 15.540 5.090 ;
        RECT 18.960 4.770 19.220 5.090 ;
        RECT 19.480 4.750 19.620 9.530 ;
        RECT 19.880 9.190 20.140 9.510 ;
        RECT 19.940 6.790 20.080 9.190 ;
        RECT 20.400 7.810 20.540 12.250 ;
        RECT 21.320 10.530 21.460 12.250 ;
        RECT 21.260 10.210 21.520 10.530 ;
        RECT 20.340 7.490 20.600 7.810 ;
        RECT 21.780 7.130 21.920 22.110 ;
        RECT 22.640 20.070 22.900 20.390 ;
        RECT 22.700 14.690 22.840 20.070 ;
        RECT 22.700 14.550 23.300 14.690 ;
        RECT 23.160 14.270 23.300 14.550 ;
        RECT 23.100 13.950 23.360 14.270 ;
        RECT 23.160 9.510 23.300 13.950 ;
        RECT 23.100 9.190 23.360 9.510 ;
        RECT 23.160 7.810 23.300 9.190 ;
        RECT 23.100 7.490 23.360 7.810 ;
        RECT 21.720 6.810 21.980 7.130 ;
        RECT 19.880 6.470 20.140 6.790 ;
        RECT 20.800 6.470 21.060 6.790 ;
        RECT 20.860 6.110 21.000 6.470 ;
        RECT 20.800 5.790 21.060 6.110 ;
        RECT 19.420 4.430 19.680 4.750 ;
        RECT 20.860 4.410 21.000 5.790 ;
        RECT 21.780 5.090 21.920 6.810 ;
        RECT 21.720 4.770 21.980 5.090 ;
        RECT 20.800 4.090 21.060 4.410 ;
  END
END dcdc_config
END LIBRARY
